VERSION 5.8 ;
BUSBITCHARS "[]" ;
DIVIDERCHAR "/" ;
UNITS
    DATABASE MICRONS 1000 ;
END UNITS

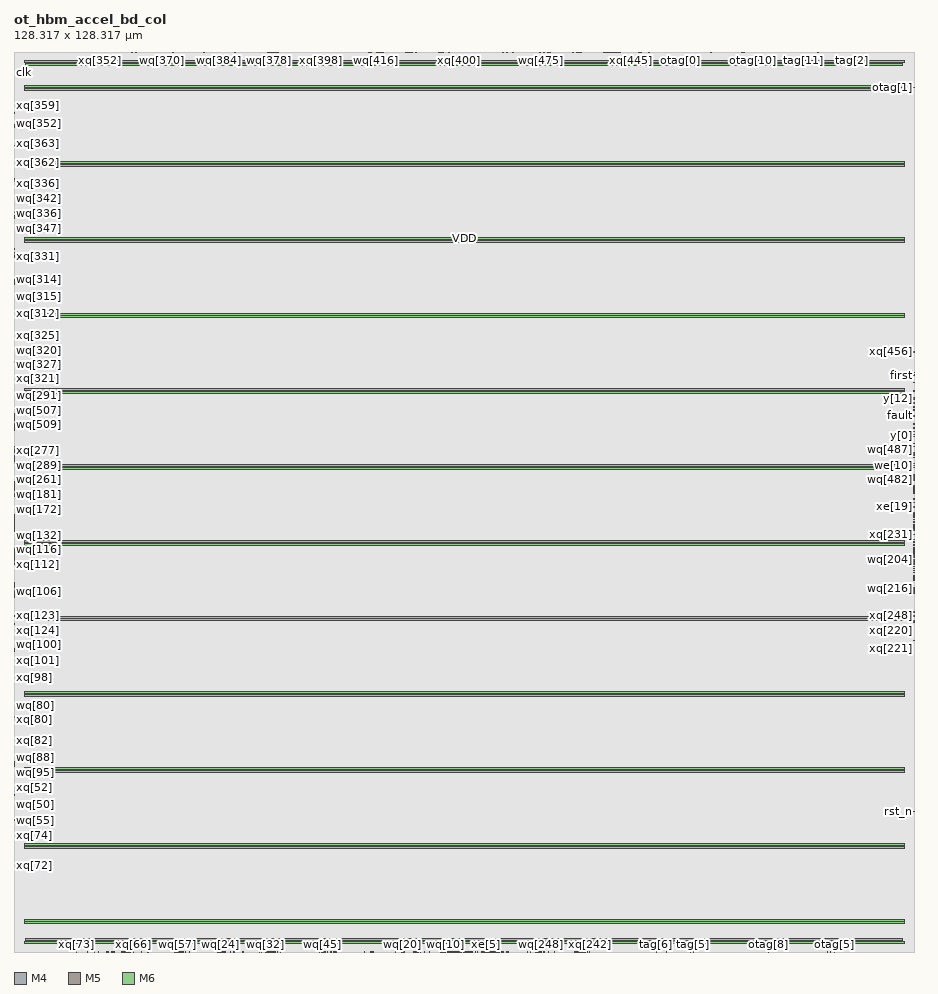
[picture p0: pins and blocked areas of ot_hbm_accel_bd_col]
MACRO ot_hbm_accel_bd_col
  FOREIGN ot_hbm_accel_bd_col 0 0 ;
  CLASS BLOCK ;
  SIZE 128.317 BY 128.317 ;
  PIN clk
    DIRECTION INPUT ;
    USE SIGNAL ;
    PORT
      LAYER M4 ;
        RECT  0 125.376 0.084 125.4 ;
    END
  END clk
  PIN fault
    DIRECTION OUTPUT ;
    USE SIGNAL ;
    PORT
      LAYER M4 ;
        RECT  128.233 76.416 128.317 76.44 ;
    END
  END fault
  PIN first
    DIRECTION INPUT ;
    USE SIGNAL ;
    PORT
      LAYER M4 ;
        RECT  128.233 82.176 128.317 82.2 ;
    END
  END first
  PIN fp4
    DIRECTION INPUT ;
    USE SIGNAL ;
    PORT
      LAYER M4 ;
        RECT  0 66.624 0.084 66.648 ;
    END
  END fp4
  PIN last
    DIRECTION INPUT ;
    USE SIGNAL ;
    PORT
      LAYER M4 ;
        RECT  128.233 82.368 128.317 82.392 ;
    END
  END last
  PIN otag[0]
    DIRECTION OUTPUT ;
    USE SIGNAL ;
    PORT
      LAYER M5 ;
        RECT  95.04 128.233 95.064 128.317 ;
    END
  END otag[0]
  PIN otag[10]
    DIRECTION OUTPUT ;
    USE SIGNAL ;
    PORT
      LAYER M5 ;
        RECT  105.408 128.233 105.432 128.317 ;
    END
  END otag[10]
  PIN otag[11]
    DIRECTION OUTPUT ;
    USE SIGNAL ;
    PORT
      LAYER M5 ;
        RECT  97.536 128.233 97.56 128.317 ;
    END
  END otag[11]
  PIN otag[12]
    DIRECTION OUTPUT ;
    USE SIGNAL ;
    PORT
      LAYER M5 ;
        RECT  97.344 128.233 97.368 128.317 ;
    END
  END otag[12]
  PIN otag[13]
    DIRECTION OUTPUT ;
    USE SIGNAL ;
    PORT
      LAYER M5 ;
        RECT  101.472 128.233 101.496 128.317 ;
    END
  END otag[13]
  PIN otag[14]
    DIRECTION OUTPUT ;
    USE SIGNAL ;
    PORT
      LAYER M5 ;
        RECT  111.744 128.233 111.768 128.317 ;
    END
  END otag[14]
  PIN otag[15]
    DIRECTION OUTPUT ;
    USE SIGNAL ;
    PORT
      LAYER M5 ;
        RECT  99.36 128.233 99.384 128.317 ;
    END
  END otag[15]
  PIN otag[1]
    DIRECTION OUTPUT ;
    USE SIGNAL ;
    PORT
      LAYER M4 ;
        RECT  128.233 123.264 128.317 123.288 ;
    END
  END otag[1]
  PIN otag[2]
    DIRECTION OUTPUT ;
    USE SIGNAL ;
    PORT
      LAYER M5 ;
        RECT  89.376 128.233 89.4 128.317 ;
    END
  END otag[2]
  PIN otag[3]
    DIRECTION OUTPUT ;
    USE SIGNAL ;
    PORT
      LAYER M5 ;
        RECT  90.528 128.233 90.552 128.317 ;
    END
  END otag[3]
  PIN otag[4]
    DIRECTION OUTPUT ;
    USE SIGNAL ;
    PORT
      LAYER M5 ;
        RECT  91.872 128.233 91.896 128.317 ;
    END
  END otag[4]
  PIN otag[5]
    DIRECTION OUTPUT ;
    USE SIGNAL ;
    PORT
      LAYER M5 ;
        RECT  117.024 0 117.048 0.084 ;
    END
  END otag[5]
  PIN otag[6]
    DIRECTION OUTPUT ;
    USE SIGNAL ;
    PORT
      LAYER M5 ;
        RECT  116.352 0 116.376 0.084 ;
    END
  END otag[6]
  PIN otag[7]
    DIRECTION OUTPUT ;
    USE SIGNAL ;
    PORT
      LAYER M5 ;
        RECT  98.976 128.233 99 128.317 ;
    END
  END otag[7]
  PIN otag[8]
    DIRECTION OUTPUT ;
    USE SIGNAL ;
    PORT
      LAYER M5 ;
        RECT  107.616 0 107.64 0.084 ;
    END
  END otag[8]
  PIN otag[9]
    DIRECTION OUTPUT ;
    USE SIGNAL ;
    PORT
      LAYER M5 ;
        RECT  115.968 0 115.992 0.084 ;
    END
  END otag[9]
  PIN ov
    DIRECTION OUTPUT ;
    USE SIGNAL ;
    PORT
      LAYER M4 ;
        RECT  128.233 82.56 128.317 82.584 ;
    END
  END ov
  PIN rst_n
    DIRECTION INPUT ;
    USE SIGNAL ;
    PORT
      LAYER M4 ;
        RECT  128.233 19.968 128.317 19.992 ;
    END
  END rst_n
  PIN tag[0]
    DIRECTION INPUT ;
    USE SIGNAL ;
    PORT
      LAYER M5 ;
        RECT  109.824 128.233 109.848 128.317 ;
    END
  END tag[0]
  PIN tag[10]
    DIRECTION INPUT ;
    USE SIGNAL ;
    PORT
      LAYER M5 ;
        RECT  104.064 128.233 104.088 128.317 ;
    END
  END tag[10]
  PIN tag[11]
    DIRECTION INPUT ;
    USE SIGNAL ;
    PORT
      LAYER M5 ;
        RECT  112.608 128.233 112.632 128.317 ;
    END
  END tag[11]
  PIN tag[12]
    DIRECTION INPUT ;
    USE SIGNAL ;
    PORT
      LAYER M5 ;
        RECT  114.624 128.233 114.648 128.317 ;
    END
  END tag[12]
  PIN tag[13]
    DIRECTION INPUT ;
    USE SIGNAL ;
    PORT
      LAYER M5 ;
        RECT  110.496 128.233 110.52 128.317 ;
    END
  END tag[13]
  PIN tag[14]
    DIRECTION INPUT ;
    USE SIGNAL ;
    PORT
      LAYER M5 ;
        RECT  107.904 128.233 107.928 128.317 ;
    END
  END tag[14]
  PIN tag[15]
    DIRECTION INPUT ;
    USE SIGNAL ;
    PORT
      LAYER M5 ;
        RECT  103.776 128.233 103.8 128.317 ;
    END
  END tag[15]
  PIN tag[1]
    DIRECTION INPUT ;
    USE SIGNAL ;
    PORT
      LAYER M5 ;
        RECT  107.328 128.233 107.352 128.317 ;
    END
  END tag[1]
  PIN tag[2]
    DIRECTION INPUT ;
    USE SIGNAL ;
    PORT
      LAYER M5 ;
        RECT  119.52 128.233 119.544 128.317 ;
    END
  END tag[2]
  PIN tag[3]
    DIRECTION INPUT ;
    USE SIGNAL ;
    PORT
      LAYER M5 ;
        RECT  111.264 128.233 111.288 128.317 ;
    END
  END tag[3]
  PIN tag[4]
    DIRECTION INPUT ;
    USE SIGNAL ;
    PORT
      LAYER M5 ;
        RECT  106.464 128.233 106.488 128.317 ;
    END
  END tag[4]
  PIN tag[5]
    DIRECTION INPUT ;
    USE SIGNAL ;
    PORT
      LAYER M5 ;
        RECT  96.864 0 96.888 0.084 ;
    END
  END tag[5]
  PIN tag[6]
    DIRECTION INPUT ;
    USE SIGNAL ;
    PORT
      LAYER M5 ;
        RECT  91.584 0 91.608 0.084 ;
    END
  END tag[6]
  PIN tag[7]
    DIRECTION INPUT ;
    USE SIGNAL ;
    PORT
      LAYER M5 ;
        RECT  117.024 128.233 117.048 128.317 ;
    END
  END tag[7]
  PIN tag[8]
    DIRECTION INPUT ;
    USE SIGNAL ;
    PORT
      LAYER M5 ;
        RECT  96.48 0 96.504 0.084 ;
    END
  END tag[8]
  PIN tag[9]
    DIRECTION INPUT ;
    USE SIGNAL ;
    PORT
      LAYER M5 ;
        RECT  93.024 0 93.048 0.084 ;
    END
  END tag[9]
  PIN v
    DIRECTION INPUT ;
    USE SIGNAL ;
    PORT
      LAYER M4 ;
        RECT  128.233 82.272 128.317 82.296 ;
    END
  END v
  PIN we[0]
    DIRECTION INPUT ;
    USE SIGNAL ;
    PORT
      LAYER M5 ;
        RECT  70.272 0 70.296 0.084 ;
    END
  END we[0]
  PIN we[10]
    DIRECTION INPUT ;
    USE SIGNAL ;
    PORT
      LAYER M4 ;
        RECT  128.233 69.408 128.317 69.432 ;
    END
  END we[10]
  PIN we[11]
    DIRECTION INPUT ;
    USE SIGNAL ;
    PORT
      LAYER M4 ;
        RECT  128.233 67.968 128.317 67.992 ;
    END
  END we[11]
  PIN we[12]
    DIRECTION INPUT ;
    USE SIGNAL ;
    PORT
      LAYER M4 ;
        RECT  128.233 67.488 128.317 67.512 ;
    END
  END we[12]
  PIN we[13]
    DIRECTION INPUT ;
    USE SIGNAL ;
    PORT
      LAYER M4 ;
        RECT  128.233 66.24 128.317 66.264 ;
    END
  END we[13]
  PIN we[14]
    DIRECTION INPUT ;
    USE SIGNAL ;
    PORT
      LAYER M4 ;
        RECT  128.233 65.376 128.317 65.4 ;
    END
  END we[14]
  PIN we[15]
    DIRECTION INPUT ;
    USE SIGNAL ;
    PORT
      LAYER M4 ;
        RECT  128.233 64.608 128.317 64.632 ;
    END
  END we[15]
  PIN we[16]
    DIRECTION INPUT ;
    USE SIGNAL ;
    PORT
      LAYER M4 ;
        RECT  128.233 64.032 128.317 64.056 ;
    END
  END we[16]
  PIN we[17]
    DIRECTION INPUT ;
    USE SIGNAL ;
    PORT
      LAYER M4 ;
        RECT  128.233 62.208 128.317 62.232 ;
    END
  END we[17]
  PIN we[18]
    DIRECTION INPUT ;
    USE SIGNAL ;
    PORT
      LAYER M4 ;
        RECT  128.233 62.496 128.317 62.52 ;
    END
  END we[18]
  PIN we[19]
    DIRECTION INPUT ;
    USE SIGNAL ;
    PORT
      LAYER M4 ;
        RECT  128.233 63.36 128.317 63.384 ;
    END
  END we[19]
  PIN we[1]
    DIRECTION INPUT ;
    USE SIGNAL ;
    PORT
      LAYER M5 ;
        RECT  69.12 0 69.144 0.084 ;
    END
  END we[1]
  PIN we[2]
    DIRECTION INPUT ;
    USE SIGNAL ;
    PORT
      LAYER M5 ;
        RECT  68.256 0 68.28 0.084 ;
    END
  END we[2]
  PIN we[3]
    DIRECTION INPUT ;
    USE SIGNAL ;
    PORT
      LAYER M5 ;
        RECT  68.928 0 68.952 0.084 ;
    END
  END we[3]
  PIN we[4]
    DIRECTION INPUT ;
    USE SIGNAL ;
    PORT
      LAYER M5 ;
        RECT  67.008 0 67.032 0.084 ;
    END
  END we[4]
  PIN we[5]
    DIRECTION INPUT ;
    USE SIGNAL ;
    PORT
      LAYER M5 ;
        RECT  67.2 0 67.224 0.084 ;
    END
  END we[5]
  PIN we[6]
    DIRECTION INPUT ;
    USE SIGNAL ;
    PORT
      LAYER M5 ;
        RECT  68.544 0 68.568 0.084 ;
    END
  END we[6]
  PIN we[7]
    DIRECTION INPUT ;
    USE SIGNAL ;
    PORT
      LAYER M5 ;
        RECT  66.624 0 66.648 0.084 ;
    END
  END we[7]
  PIN we[8]
    DIRECTION INPUT ;
    USE SIGNAL ;
    PORT
      LAYER M5 ;
        RECT  64.8 0 64.824 0.084 ;
    END
  END we[8]
  PIN we[9]
    DIRECTION INPUT ;
    USE SIGNAL ;
    PORT
      LAYER M5 ;
        RECT  65.088 0 65.112 0.084 ;
    END
  END we[9]
  PIN wq[0]
    DIRECTION INPUT ;
    USE SIGNAL ;
    PORT
      LAYER M5 ;
        RECT  63.84 0 63.864 0.084 ;
    END
  END wq[0]
  PIN wq[100]
    DIRECTION INPUT ;
    USE SIGNAL ;
    PORT
      LAYER M4 ;
        RECT  0 43.776 0.084 43.8 ;
    END
  END wq[100]
  PIN wq[101]
    DIRECTION INPUT ;
    USE SIGNAL ;
    PORT
      LAYER M4 ;
        RECT  0 43.392 0.084 43.416 ;
    END
  END wq[101]
  PIN wq[102]
    DIRECTION INPUT ;
    USE SIGNAL ;
    PORT
      LAYER M4 ;
        RECT  0 43.2 0.084 43.224 ;
    END
  END wq[102]
  PIN wq[103]
    DIRECTION INPUT ;
    USE SIGNAL ;
    PORT
      LAYER M4 ;
        RECT  0 44.64 0.084 44.664 ;
    END
  END wq[103]
  PIN wq[104]
    DIRECTION INPUT ;
    USE SIGNAL ;
    PORT
      LAYER M4 ;
        RECT  0 50.88 0.084 50.904 ;
    END
  END wq[104]
  PIN wq[105]
    DIRECTION INPUT ;
    USE SIGNAL ;
    PORT
      LAYER M4 ;
        RECT  0 51.552 0.084 51.576 ;
    END
  END wq[105]
  PIN wq[106]
    DIRECTION INPUT ;
    USE SIGNAL ;
    PORT
      LAYER M4 ;
        RECT  0 51.456 0.084 51.48 ;
    END
  END wq[106]
  PIN wq[107]
    DIRECTION INPUT ;
    USE SIGNAL ;
    PORT
      LAYER M4 ;
        RECT  0 51.936 0.084 51.96 ;
    END
  END wq[107]
  PIN wq[108]
    DIRECTION INPUT ;
    USE SIGNAL ;
    PORT
      LAYER M4 ;
        RECT  0 50.976 0.084 51 ;
    END
  END wq[108]
  PIN wq[109]
    DIRECTION INPUT ;
    USE SIGNAL ;
    PORT
      LAYER M4 ;
        RECT  0 51.36 0.084 51.384 ;
    END
  END wq[109]
  PIN wq[10]
    DIRECTION INPUT ;
    USE SIGNAL ;
    PORT
      LAYER M5 ;
        RECT  61.536 0 61.56 0.084 ;
    END
  END wq[10]
  PIN wq[110]
    DIRECTION INPUT ;
    USE SIGNAL ;
    PORT
      LAYER M4 ;
        RECT  0 51.648 0.084 51.672 ;
    END
  END wq[110]
  PIN wq[111]
    DIRECTION INPUT ;
    USE SIGNAL ;
    PORT
      LAYER M4 ;
        RECT  0 51.744 0.084 51.768 ;
    END
  END wq[111]
  PIN wq[112]
    DIRECTION INPUT ;
    USE SIGNAL ;
    PORT
      LAYER M4 ;
        RECT  0 52.416 0.084 52.44 ;
    END
  END wq[112]
  PIN wq[113]
    DIRECTION INPUT ;
    USE SIGNAL ;
    PORT
      LAYER M4 ;
        RECT  0 56.544 0.084 56.568 ;
    END
  END wq[113]
  PIN wq[114]
    DIRECTION INPUT ;
    USE SIGNAL ;
    PORT
      LAYER M4 ;
        RECT  0 56.832 0.084 56.856 ;
    END
  END wq[114]
  PIN wq[115]
    DIRECTION INPUT ;
    USE SIGNAL ;
    PORT
      LAYER M4 ;
        RECT  0 54.624 0.084 54.648 ;
    END
  END wq[115]
  PIN wq[116]
    DIRECTION INPUT ;
    USE SIGNAL ;
    PORT
      LAYER M4 ;
        RECT  0 57.312 0.084 57.336 ;
    END
  END wq[116]
  PIN wq[117]
    DIRECTION INPUT ;
    USE SIGNAL ;
    PORT
      LAYER M4 ;
        RECT  0 53.568 0.084 53.592 ;
    END
  END wq[117]
  PIN wq[118]
    DIRECTION INPUT ;
    USE SIGNAL ;
    PORT
      LAYER M4 ;
        RECT  0 56.256 0.084 56.28 ;
    END
  END wq[118]
  PIN wq[119]
    DIRECTION INPUT ;
    USE SIGNAL ;
    PORT
      LAYER M4 ;
        RECT  0 54.912 0.084 54.936 ;
    END
  END wq[119]
  PIN wq[11]
    DIRECTION INPUT ;
    USE SIGNAL ;
    PORT
      LAYER M5 ;
        RECT  64.416 0 64.44 0.084 ;
    END
  END wq[11]
  PIN wq[120]
    DIRECTION INPUT ;
    USE SIGNAL ;
    PORT
      LAYER M4 ;
        RECT  0 52.224 0.084 52.248 ;
    END
  END wq[120]
  PIN wq[121]
    DIRECTION INPUT ;
    USE SIGNAL ;
    PORT
      LAYER M4 ;
        RECT  0 52.32 0.084 52.344 ;
    END
  END wq[121]
  PIN wq[122]
    DIRECTION INPUT ;
    USE SIGNAL ;
    PORT
      LAYER M4 ;
        RECT  0 52.128 0.084 52.152 ;
    END
  END wq[122]
  PIN wq[123]
    DIRECTION INPUT ;
    USE SIGNAL ;
    PORT
      LAYER M4 ;
        RECT  0 50.496 0.084 50.52 ;
    END
  END wq[123]
  PIN wq[124]
    DIRECTION INPUT ;
    USE SIGNAL ;
    PORT
      LAYER M4 ;
        RECT  0 50.688 0.084 50.712 ;
    END
  END wq[124]
  PIN wq[125]
    DIRECTION INPUT ;
    USE SIGNAL ;
    PORT
      LAYER M4 ;
        RECT  0 50.592 0.084 50.616 ;
    END
  END wq[125]
  PIN wq[126]
    DIRECTION INPUT ;
    USE SIGNAL ;
    PORT
      LAYER M4 ;
        RECT  0 52.032 0.084 52.056 ;
    END
  END wq[126]
  PIN wq[127]
    DIRECTION INPUT ;
    USE SIGNAL ;
    PORT
      LAYER M4 ;
        RECT  0 49.824 0.084 49.848 ;
    END
  END wq[127]
  PIN wq[128]
    DIRECTION INPUT ;
    USE SIGNAL ;
    PORT
      LAYER M4 ;
        RECT  0 53.76 0.084 53.784 ;
    END
  END wq[128]
  PIN wq[129]
    DIRECTION INPUT ;
    USE SIGNAL ;
    PORT
      LAYER M4 ;
        RECT  0 58.368 0.084 58.392 ;
    END
  END wq[129]
  PIN wq[12]
    DIRECTION INPUT ;
    USE SIGNAL ;
    PORT
      LAYER M5 ;
        RECT  62.496 0 62.52 0.084 ;
    END
  END wq[12]
  PIN wq[130]
    DIRECTION INPUT ;
    USE SIGNAL ;
    PORT
      LAYER M4 ;
        RECT  0 57.792 0.084 57.816 ;
    END
  END wq[130]
  PIN wq[131]
    DIRECTION INPUT ;
    USE SIGNAL ;
    PORT
      LAYER M4 ;
        RECT  0 53.664 0.084 53.688 ;
    END
  END wq[131]
  PIN wq[132]
    DIRECTION INPUT ;
    USE SIGNAL ;
    PORT
      LAYER M4 ;
        RECT  0 59.328 0.084 59.352 ;
    END
  END wq[132]
  PIN wq[133]
    DIRECTION INPUT ;
    USE SIGNAL ;
    PORT
      LAYER M4 ;
        RECT  0 57.696 0.084 57.72 ;
    END
  END wq[133]
  PIN wq[134]
    DIRECTION INPUT ;
    USE SIGNAL ;
    PORT
      LAYER M4 ;
        RECT  0 58.464 0.084 58.488 ;
    END
  END wq[134]
  PIN wq[135]
    DIRECTION INPUT ;
    USE SIGNAL ;
    PORT
      LAYER M4 ;
        RECT  0 59.136 0.084 59.16 ;
    END
  END wq[135]
  PIN wq[136]
    DIRECTION INPUT ;
    USE SIGNAL ;
    PORT
      LAYER M4 ;
        RECT  0 59.04 0.084 59.064 ;
    END
  END wq[136]
  PIN wq[137]
    DIRECTION INPUT ;
    USE SIGNAL ;
    PORT
      LAYER M4 ;
        RECT  0 58.848 0.084 58.872 ;
    END
  END wq[137]
  PIN wq[138]
    DIRECTION INPUT ;
    USE SIGNAL ;
    PORT
      LAYER M4 ;
        RECT  0 58.752 0.084 58.776 ;
    END
  END wq[138]
  PIN wq[139]
    DIRECTION INPUT ;
    USE SIGNAL ;
    PORT
      LAYER M4 ;
        RECT  0 53.28 0.084 53.304 ;
    END
  END wq[139]
  PIN wq[13]
    DIRECTION INPUT ;
    USE SIGNAL ;
    PORT
      LAYER M5 ;
        RECT  62.592 0 62.616 0.084 ;
    END
  END wq[13]
  PIN wq[140]
    DIRECTION INPUT ;
    USE SIGNAL ;
    PORT
      LAYER M4 ;
        RECT  0 57.888 0.084 57.912 ;
    END
  END wq[140]
  PIN wq[141]
    DIRECTION INPUT ;
    USE SIGNAL ;
    PORT
      LAYER M4 ;
        RECT  0 57.408 0.084 57.432 ;
    END
  END wq[141]
  PIN wq[142]
    DIRECTION INPUT ;
    USE SIGNAL ;
    PORT
      LAYER M4 ;
        RECT  0 56.064 0.084 56.088 ;
    END
  END wq[142]
  PIN wq[143]
    DIRECTION INPUT ;
    USE SIGNAL ;
    PORT
      LAYER M4 ;
        RECT  0 59.808 0.084 59.832 ;
    END
  END wq[143]
  PIN wq[144]
    DIRECTION INPUT ;
    USE SIGNAL ;
    PORT
      LAYER M4 ;
        RECT  0 60.768 0.084 60.792 ;
    END
  END wq[144]
  PIN wq[145]
    DIRECTION INPUT ;
    USE SIGNAL ;
    PORT
      LAYER M4 ;
        RECT  0 60.48 0.084 60.504 ;
    END
  END wq[145]
  PIN wq[146]
    DIRECTION INPUT ;
    USE SIGNAL ;
    PORT
      LAYER M4 ;
        RECT  0 60.384 0.084 60.408 ;
    END
  END wq[146]
  PIN wq[147]
    DIRECTION INPUT ;
    USE SIGNAL ;
    PORT
      LAYER M4 ;
        RECT  0 60.576 0.084 60.6 ;
    END
  END wq[147]
  PIN wq[148]
    DIRECTION INPUT ;
    USE SIGNAL ;
    PORT
      LAYER M4 ;
        RECT  0 60.192 0.084 60.216 ;
    END
  END wq[148]
  PIN wq[149]
    DIRECTION INPUT ;
    USE SIGNAL ;
    PORT
      LAYER M4 ;
        RECT  0 60.288 0.084 60.312 ;
    END
  END wq[149]
  PIN wq[14]
    DIRECTION INPUT ;
    USE SIGNAL ;
    PORT
      LAYER M5 ;
        RECT  61.44 0 61.464 0.084 ;
    END
  END wq[14]
  PIN wq[150]
    DIRECTION INPUT ;
    USE SIGNAL ;
    PORT
      LAYER M4 ;
        RECT  0 60 0.084 60.024 ;
    END
  END wq[150]
  PIN wq[151]
    DIRECTION INPUT ;
    USE SIGNAL ;
    PORT
      LAYER M4 ;
        RECT  0 61.536 0.084 61.56 ;
    END
  END wq[151]
  PIN wq[152]
    DIRECTION INPUT ;
    USE SIGNAL ;
    PORT
      LAYER M4 ;
        RECT  0 57.6 0.084 57.624 ;
    END
  END wq[152]
  PIN wq[153]
    DIRECTION INPUT ;
    USE SIGNAL ;
    PORT
      LAYER M4 ;
        RECT  0 52.608 0.084 52.632 ;
    END
  END wq[153]
  PIN wq[154]
    DIRECTION INPUT ;
    USE SIGNAL ;
    PORT
      LAYER M4 ;
        RECT  0 59.232 0.084 59.256 ;
    END
  END wq[154]
  PIN wq[155]
    DIRECTION INPUT ;
    USE SIGNAL ;
    PORT
      LAYER M4 ;
        RECT  0 57.984 0.084 58.008 ;
    END
  END wq[155]
  PIN wq[156]
    DIRECTION INPUT ;
    USE SIGNAL ;
    PORT
      LAYER M4 ;
        RECT  0 58.176 0.084 58.2 ;
    END
  END wq[156]
  PIN wq[157]
    DIRECTION INPUT ;
    USE SIGNAL ;
    PORT
      LAYER M4 ;
        RECT  0 58.08 0.084 58.104 ;
    END
  END wq[157]
  PIN wq[158]
    DIRECTION INPUT ;
    USE SIGNAL ;
    PORT
      LAYER M4 ;
        RECT  0 53.856 0.084 53.88 ;
    END
  END wq[158]
  PIN wq[159]
    DIRECTION INPUT ;
    USE SIGNAL ;
    PORT
      LAYER M4 ;
        RECT  0 56.736 0.084 56.76 ;
    END
  END wq[159]
  PIN wq[15]
    DIRECTION INPUT ;
    USE SIGNAL ;
    PORT
      LAYER M5 ;
        RECT  64.992 0 65.016 0.084 ;
    END
  END wq[15]
  PIN wq[160]
    DIRECTION INPUT ;
    USE SIGNAL ;
    PORT
      LAYER M4 ;
        RECT  0 52.8 0.084 52.824 ;
    END
  END wq[160]
  PIN wq[161]
    DIRECTION INPUT ;
    USE SIGNAL ;
    PORT
      LAYER M4 ;
        RECT  0 61.248 0.084 61.272 ;
    END
  END wq[161]
  PIN wq[162]
    DIRECTION INPUT ;
    USE SIGNAL ;
    PORT
      LAYER M4 ;
        RECT  0 59.52 0.084 59.544 ;
    END
  END wq[162]
  PIN wq[163]
    DIRECTION INPUT ;
    USE SIGNAL ;
    PORT
      LAYER M4 ;
        RECT  0 62.496 0.084 62.52 ;
    END
  END wq[163]
  PIN wq[164]
    DIRECTION INPUT ;
    USE SIGNAL ;
    PORT
      LAYER M4 ;
        RECT  0 61.728 0.084 61.752 ;
    END
  END wq[164]
  PIN wq[165]
    DIRECTION INPUT ;
    USE SIGNAL ;
    PORT
      LAYER M4 ;
        RECT  0 52.512 0.084 52.536 ;
    END
  END wq[165]
  PIN wq[166]
    DIRECTION INPUT ;
    USE SIGNAL ;
    PORT
      LAYER M4 ;
        RECT  0 62.4 0.084 62.424 ;
    END
  END wq[166]
  PIN wq[167]
    DIRECTION INPUT ;
    USE SIGNAL ;
    PORT
      LAYER M4 ;
        RECT  0 63.36 0.084 63.384 ;
    END
  END wq[167]
  PIN wq[168]
    DIRECTION INPUT ;
    USE SIGNAL ;
    PORT
      LAYER M4 ;
        RECT  0 61.632 0.084 61.656 ;
    END
  END wq[168]
  PIN wq[169]
    DIRECTION INPUT ;
    USE SIGNAL ;
    PORT
      LAYER M4 ;
        RECT  0 64.608 0.084 64.632 ;
    END
  END wq[169]
  PIN wq[16]
    DIRECTION INPUT ;
    USE SIGNAL ;
    PORT
      LAYER M5 ;
        RECT  57.216 0 57.24 0.084 ;
    END
  END wq[16]
  PIN wq[170]
    DIRECTION INPUT ;
    USE SIGNAL ;
    PORT
      LAYER M4 ;
        RECT  0 64.224 0.084 64.248 ;
    END
  END wq[170]
  PIN wq[171]
    DIRECTION INPUT ;
    USE SIGNAL ;
    PORT
      LAYER M4 ;
        RECT  0 62.304 0.084 62.328 ;
    END
  END wq[171]
  PIN wq[172]
    DIRECTION INPUT ;
    USE SIGNAL ;
    PORT
      LAYER M4 ;
        RECT  0 63.072 0.084 63.096 ;
    END
  END wq[172]
  PIN wq[173]
    DIRECTION INPUT ;
    USE SIGNAL ;
    PORT
      LAYER M4 ;
        RECT  0 52.992 0.084 53.016 ;
    END
  END wq[173]
  PIN wq[174]
    DIRECTION INPUT ;
    USE SIGNAL ;
    PORT
      LAYER M4 ;
        RECT  0 63.936 0.084 63.96 ;
    END
  END wq[174]
  PIN wq[175]
    DIRECTION INPUT ;
    USE SIGNAL ;
    PORT
      LAYER M4 ;
        RECT  0 53.088 0.084 53.112 ;
    END
  END wq[175]
  PIN wq[176]
    DIRECTION INPUT ;
    USE SIGNAL ;
    PORT
      LAYER M4 ;
        RECT  0 64.8 0.084 64.824 ;
    END
  END wq[176]
  PIN wq[177]
    DIRECTION INPUT ;
    USE SIGNAL ;
    PORT
      LAYER M4 ;
        RECT  0 64.704 0.084 64.728 ;
    END
  END wq[177]
  PIN wq[178]
    DIRECTION INPUT ;
    USE SIGNAL ;
    PORT
      LAYER M4 ;
        RECT  0 59.424 0.084 59.448 ;
    END
  END wq[178]
  PIN wq[179]
    DIRECTION INPUT ;
    USE SIGNAL ;
    PORT
      LAYER M4 ;
        RECT  0 52.704 0.084 52.728 ;
    END
  END wq[179]
  PIN wq[17]
    DIRECTION INPUT ;
    USE SIGNAL ;
    PORT
      LAYER M5 ;
        RECT  57.312 0 57.336 0.084 ;
    END
  END wq[17]
  PIN wq[180]
    DIRECTION INPUT ;
    USE SIGNAL ;
    PORT
      LAYER M4 ;
        RECT  0 64.32 0.084 64.344 ;
    END
  END wq[180]
  PIN wq[181]
    DIRECTION INPUT ;
    USE SIGNAL ;
    PORT
      LAYER M4 ;
        RECT  0 64.128 0.084 64.152 ;
    END
  END wq[181]
  PIN wq[182]
    DIRECTION INPUT ;
    USE SIGNAL ;
    PORT
      LAYER M4 ;
        RECT  0 62.592 0.084 62.616 ;
    END
  END wq[182]
  PIN wq[183]
    DIRECTION INPUT ;
    USE SIGNAL ;
    PORT
      LAYER M4 ;
        RECT  0 63.168 0.084 63.192 ;
    END
  END wq[183]
  PIN wq[184]
    DIRECTION INPUT ;
    USE SIGNAL ;
    PORT
      LAYER M4 ;
        RECT  0 63.552 0.084 63.576 ;
    END
  END wq[184]
  PIN wq[185]
    DIRECTION INPUT ;
    USE SIGNAL ;
    PORT
      LAYER M4 ;
        RECT  0 60.96 0.084 60.984 ;
    END
  END wq[185]
  PIN wq[186]
    DIRECTION INPUT ;
    USE SIGNAL ;
    PORT
      LAYER M4 ;
        RECT  0 61.92 0.084 61.944 ;
    END
  END wq[186]
  PIN wq[187]
    DIRECTION INPUT ;
    USE SIGNAL ;
    PORT
      LAYER M4 ;
        RECT  0 62.784 0.084 62.808 ;
    END
  END wq[187]
  PIN wq[188]
    DIRECTION INPUT ;
    USE SIGNAL ;
    PORT
      LAYER M4 ;
        RECT  0 62.976 0.084 63 ;
    END
  END wq[188]
  PIN wq[189]
    DIRECTION INPUT ;
    USE SIGNAL ;
    PORT
      LAYER M4 ;
        RECT  0 63.456 0.084 63.48 ;
    END
  END wq[189]
  PIN wq[18]
    DIRECTION INPUT ;
    USE SIGNAL ;
    PORT
      LAYER M5 ;
        RECT  57.408 0 57.432 0.084 ;
    END
  END wq[18]
  PIN wq[190]
    DIRECTION INPUT ;
    USE SIGNAL ;
    PORT
      LAYER M4 ;
        RECT  0 63.648 0.084 63.672 ;
    END
  END wq[190]
  PIN wq[191]
    DIRECTION INPUT ;
    USE SIGNAL ;
    PORT
      LAYER M4 ;
        RECT  0 62.112 0.084 62.136 ;
    END
  END wq[191]
  PIN wq[192]
    DIRECTION INPUT ;
    USE SIGNAL ;
    PORT
      LAYER M5 ;
        RECT  62.4 128.233 62.424 128.317 ;
    END
  END wq[192]
  PIN wq[193]
    DIRECTION INPUT ;
    USE SIGNAL ;
    PORT
      LAYER M5 ;
        RECT  62.688 128.233 62.712 128.317 ;
    END
  END wq[193]
  PIN wq[194]
    DIRECTION INPUT ;
    USE SIGNAL ;
    PORT
      LAYER M5 ;
        RECT  62.496 128.233 62.52 128.317 ;
    END
  END wq[194]
  PIN wq[195]
    DIRECTION INPUT ;
    USE SIGNAL ;
    PORT
      LAYER M4 ;
        RECT  0 63.264 0.084 63.288 ;
    END
  END wq[195]
  PIN wq[196]
    DIRECTION INPUT ;
    USE SIGNAL ;
    PORT
      LAYER M4 ;
        RECT  0 63.84 0.084 63.864 ;
    END
  END wq[196]
  PIN wq[197]
    DIRECTION INPUT ;
    USE SIGNAL ;
    PORT
      LAYER M4 ;
        RECT  0 63.744 0.084 63.768 ;
    END
  END wq[197]
  PIN wq[198]
    DIRECTION INPUT ;
    USE SIGNAL ;
    PORT
      LAYER M4 ;
        RECT  0 62.688 0.084 62.712 ;
    END
  END wq[198]
  PIN wq[199]
    DIRECTION INPUT ;
    USE SIGNAL ;
    PORT
      LAYER M5 ;
        RECT  64.32 0 64.344 0.084 ;
    END
  END wq[199]
  PIN wq[19]
    DIRECTION INPUT ;
    USE SIGNAL ;
    PORT
      LAYER M5 ;
        RECT  51.168 0 51.192 0.084 ;
    END
  END wq[19]
  PIN wq[1]
    DIRECTION INPUT ;
    USE SIGNAL ;
    PORT
      LAYER M5 ;
        RECT  63.648 0 63.672 0.084 ;
    END
  END wq[1]
  PIN wq[200]
    DIRECTION INPUT ;
    USE SIGNAL ;
    PORT
      LAYER M4 ;
        RECT  128.233 56.256 128.317 56.28 ;
    END
  END wq[200]
  PIN wq[201]
    DIRECTION INPUT ;
    USE SIGNAL ;
    PORT
      LAYER M4 ;
        RECT  128.233 56.448 128.317 56.472 ;
    END
  END wq[201]
  PIN wq[202]
    DIRECTION INPUT ;
    USE SIGNAL ;
    PORT
      LAYER M4 ;
        RECT  128.233 56.832 128.317 56.856 ;
    END
  END wq[202]
  PIN wq[203]
    DIRECTION INPUT ;
    USE SIGNAL ;
    PORT
      LAYER M4 ;
        RECT  128.233 57.504 128.317 57.528 ;
    END
  END wq[203]
  PIN wq[204]
    DIRECTION INPUT ;
    USE SIGNAL ;
    PORT
      LAYER M4 ;
        RECT  128.233 55.968 128.317 55.992 ;
    END
  END wq[204]
  PIN wq[205]
    DIRECTION INPUT ;
    USE SIGNAL ;
    PORT
      LAYER M4 ;
        RECT  128.233 55.872 128.317 55.896 ;
    END
  END wq[205]
  PIN wq[206]
    DIRECTION INPUT ;
    USE SIGNAL ;
    PORT
      LAYER M4 ;
        RECT  128.233 56.544 128.317 56.568 ;
    END
  END wq[206]
  PIN wq[207]
    DIRECTION INPUT ;
    USE SIGNAL ;
    PORT
      LAYER M4 ;
        RECT  128.233 57.312 128.317 57.336 ;
    END
  END wq[207]
  PIN wq[208]
    DIRECTION INPUT ;
    USE SIGNAL ;
    PORT
      LAYER M5 ;
        RECT  68.832 0 68.856 0.084 ;
    END
  END wq[208]
  PIN wq[209]
    DIRECTION INPUT ;
    USE SIGNAL ;
    PORT
      LAYER M5 ;
        RECT  68.352 0 68.376 0.084 ;
    END
  END wq[209]
  PIN wq[20]
    DIRECTION INPUT ;
    USE SIGNAL ;
    PORT
      LAYER M5 ;
        RECT  55.392 0 55.416 0.084 ;
    END
  END wq[20]
  PIN wq[210]
    DIRECTION INPUT ;
    USE SIGNAL ;
    PORT
      LAYER M5 ;
        RECT  68.64 0 68.664 0.084 ;
    END
  END wq[210]
  PIN wq[211]
    DIRECTION INPUT ;
    USE SIGNAL ;
    PORT
      LAYER M5 ;
        RECT  69.504 0 69.528 0.084 ;
    END
  END wq[211]
  PIN wq[212]
    DIRECTION INPUT ;
    USE SIGNAL ;
    PORT
      LAYER M5 ;
        RECT  67.392 0 67.416 0.084 ;
    END
  END wq[212]
  PIN wq[213]
    DIRECTION INPUT ;
    USE SIGNAL ;
    PORT
      LAYER M5 ;
        RECT  67.104 0 67.128 0.084 ;
    END
  END wq[213]
  PIN wq[214]
    DIRECTION INPUT ;
    USE SIGNAL ;
    PORT
      LAYER M5 ;
        RECT  67.968 0 67.992 0.084 ;
    END
  END wq[214]
  PIN wq[215]
    DIRECTION INPUT ;
    USE SIGNAL ;
    PORT
      LAYER M5 ;
        RECT  70.464 0 70.488 0.084 ;
    END
  END wq[215]
  PIN wq[216]
    DIRECTION INPUT ;
    USE SIGNAL ;
    PORT
      LAYER M4 ;
        RECT  128.233 51.84 128.317 51.864 ;
    END
  END wq[216]
  PIN wq[217]
    DIRECTION INPUT ;
    USE SIGNAL ;
    PORT
      LAYER M4 ;
        RECT  128.233 51.936 128.317 51.96 ;
    END
  END wq[217]
  PIN wq[218]
    DIRECTION INPUT ;
    USE SIGNAL ;
    PORT
      LAYER M4 ;
        RECT  128.233 51.456 128.317 51.48 ;
    END
  END wq[218]
  PIN wq[219]
    DIRECTION INPUT ;
    USE SIGNAL ;
    PORT
      LAYER M4 ;
        RECT  128.233 51.552 128.317 51.576 ;
    END
  END wq[219]
  PIN wq[21]
    DIRECTION INPUT ;
    USE SIGNAL ;
    PORT
      LAYER M5 ;
        RECT  57.504 0 57.528 0.084 ;
    END
  END wq[21]
  PIN wq[220]
    DIRECTION INPUT ;
    USE SIGNAL ;
    PORT
      LAYER M4 ;
        RECT  128.233 51.264 128.317 51.288 ;
    END
  END wq[220]
  PIN wq[221]
    DIRECTION INPUT ;
    USE SIGNAL ;
    PORT
      LAYER M4 ;
        RECT  128.233 51.072 128.317 51.096 ;
    END
  END wq[221]
  PIN wq[222]
    DIRECTION INPUT ;
    USE SIGNAL ;
    PORT
      LAYER M4 ;
        RECT  128.233 51.168 128.317 51.192 ;
    END
  END wq[222]
  PIN wq[223]
    DIRECTION INPUT ;
    USE SIGNAL ;
    PORT
      LAYER M4 ;
        RECT  128.233 51.744 128.317 51.768 ;
    END
  END wq[223]
  PIN wq[224]
    DIRECTION INPUT ;
    USE SIGNAL ;
    PORT
      LAYER M4 ;
        RECT  128.233 58.368 128.317 58.392 ;
    END
  END wq[224]
  PIN wq[225]
    DIRECTION INPUT ;
    USE SIGNAL ;
    PORT
      LAYER M4 ;
        RECT  128.233 57.888 128.317 57.912 ;
    END
  END wq[225]
  PIN wq[226]
    DIRECTION INPUT ;
    USE SIGNAL ;
    PORT
      LAYER M4 ;
        RECT  128.233 57.408 128.317 57.432 ;
    END
  END wq[226]
  PIN wq[227]
    DIRECTION INPUT ;
    USE SIGNAL ;
    PORT
      LAYER M4 ;
        RECT  128.233 57.984 128.317 58.008 ;
    END
  END wq[227]
  PIN wq[228]
    DIRECTION INPUT ;
    USE SIGNAL ;
    PORT
      LAYER M4 ;
        RECT  128.233 57.216 128.317 57.24 ;
    END
  END wq[228]
  PIN wq[229]
    DIRECTION INPUT ;
    USE SIGNAL ;
    PORT
      LAYER M4 ;
        RECT  128.233 56.928 128.317 56.952 ;
    END
  END wq[229]
  PIN wq[22]
    DIRECTION INPUT ;
    USE SIGNAL ;
    PORT
      LAYER M5 ;
        RECT  57.696 0 57.72 0.084 ;
    END
  END wq[22]
  PIN wq[230]
    DIRECTION INPUT ;
    USE SIGNAL ;
    PORT
      LAYER M4 ;
        RECT  128.233 56.736 128.317 56.76 ;
    END
  END wq[230]
  PIN wq[231]
    DIRECTION INPUT ;
    USE SIGNAL ;
    PORT
      LAYER M4 ;
        RECT  128.233 58.752 128.317 58.776 ;
    END
  END wq[231]
  PIN wq[232]
    DIRECTION INPUT ;
    USE SIGNAL ;
    PORT
      LAYER M4 ;
        RECT  128.233 58.08 128.317 58.104 ;
    END
  END wq[232]
  PIN wq[233]
    DIRECTION INPUT ;
    USE SIGNAL ;
    PORT
      LAYER M4 ;
        RECT  128.233 58.464 128.317 58.488 ;
    END
  END wq[233]
  PIN wq[234]
    DIRECTION INPUT ;
    USE SIGNAL ;
    PORT
      LAYER M4 ;
        RECT  128.233 57.6 128.317 57.624 ;
    END
  END wq[234]
  PIN wq[235]
    DIRECTION INPUT ;
    USE SIGNAL ;
    PORT
      LAYER M4 ;
        RECT  128.233 58.56 128.317 58.584 ;
    END
  END wq[235]
  PIN wq[236]
    DIRECTION INPUT ;
    USE SIGNAL ;
    PORT
      LAYER M4 ;
        RECT  128.233 57.12 128.317 57.144 ;
    END
  END wq[236]
  PIN wq[237]
    DIRECTION INPUT ;
    USE SIGNAL ;
    PORT
      LAYER M4 ;
        RECT  128.233 57.024 128.317 57.048 ;
    END
  END wq[237]
  PIN wq[238]
    DIRECTION INPUT ;
    USE SIGNAL ;
    PORT
      LAYER M4 ;
        RECT  128.233 56.64 128.317 56.664 ;
    END
  END wq[238]
  PIN wq[239]
    DIRECTION INPUT ;
    USE SIGNAL ;
    PORT
      LAYER M4 ;
        RECT  128.233 60.48 128.317 60.504 ;
    END
  END wq[239]
  PIN wq[23]
    DIRECTION INPUT ;
    USE SIGNAL ;
    PORT
      LAYER M5 ;
        RECT  50.88 0 50.904 0.084 ;
    END
  END wq[23]
  PIN wq[240]
    DIRECTION INPUT ;
    USE SIGNAL ;
    PORT
      LAYER M5 ;
        RECT  79.968 0 79.992 0.084 ;
    END
  END wq[240]
  PIN wq[241]
    DIRECTION INPUT ;
    USE SIGNAL ;
    PORT
      LAYER M5 ;
        RECT  79.872 0 79.896 0.084 ;
    END
  END wq[241]
  PIN wq[242]
    DIRECTION INPUT ;
    USE SIGNAL ;
    PORT
      LAYER M5 ;
        RECT  80.064 0 80.088 0.084 ;
    END
  END wq[242]
  PIN wq[243]
    DIRECTION INPUT ;
    USE SIGNAL ;
    PORT
      LAYER M5 ;
        RECT  80.736 0 80.76 0.084 ;
    END
  END wq[243]
  PIN wq[244]
    DIRECTION INPUT ;
    USE SIGNAL ;
    PORT
      LAYER M5 ;
        RECT  80.544 0 80.568 0.084 ;
    END
  END wq[244]
  PIN wq[245]
    DIRECTION INPUT ;
    USE SIGNAL ;
    PORT
      LAYER M5 ;
        RECT  80.256 0 80.28 0.084 ;
    END
  END wq[245]
  PIN wq[246]
    DIRECTION INPUT ;
    USE SIGNAL ;
    PORT
      LAYER M5 ;
        RECT  80.352 0 80.376 0.084 ;
    END
  END wq[246]
  PIN wq[247]
    DIRECTION INPUT ;
    USE SIGNAL ;
    PORT
      LAYER M5 ;
        RECT  80.928 0 80.952 0.084 ;
    END
  END wq[247]
  PIN wq[248]
    DIRECTION INPUT ;
    USE SIGNAL ;
    PORT
      LAYER M5 ;
        RECT  75.168 0 75.192 0.084 ;
    END
  END wq[248]
  PIN wq[249]
    DIRECTION INPUT ;
    USE SIGNAL ;
    PORT
      LAYER M5 ;
        RECT  74.976 0 75 0.084 ;
    END
  END wq[249]
  PIN wq[24]
    DIRECTION INPUT ;
    USE SIGNAL ;
    PORT
      LAYER M5 ;
        RECT  29.376 0 29.4 0.084 ;
    END
  END wq[24]
  PIN wq[250]
    DIRECTION INPUT ;
    USE SIGNAL ;
    PORT
      LAYER M5 ;
        RECT  75.072 0 75.096 0.084 ;
    END
  END wq[250]
  PIN wq[251]
    DIRECTION INPUT ;
    USE SIGNAL ;
    PORT
      LAYER M5 ;
        RECT  75.552 0 75.576 0.084 ;
    END
  END wq[251]
  PIN wq[252]
    DIRECTION INPUT ;
    USE SIGNAL ;
    PORT
      LAYER M5 ;
        RECT  74.4 0 74.424 0.084 ;
    END
  END wq[252]
  PIN wq[253]
    DIRECTION INPUT ;
    USE SIGNAL ;
    PORT
      LAYER M5 ;
        RECT  74.784 0 74.808 0.084 ;
    END
  END wq[253]
  PIN wq[254]
    DIRECTION INPUT ;
    USE SIGNAL ;
    PORT
      LAYER M5 ;
        RECT  74.688 0 74.712 0.084 ;
    END
  END wq[254]
  PIN wq[255]
    DIRECTION INPUT ;
    USE SIGNAL ;
    PORT
      LAYER M5 ;
        RECT  76.224 0 76.248 0.084 ;
    END
  END wq[255]
  PIN wq[256]
    DIRECTION INPUT ;
    USE SIGNAL ;
    PORT
      LAYER M4 ;
        RECT  0 66.336 0.084 66.36 ;
    END
  END wq[256]
  PIN wq[257]
    DIRECTION INPUT ;
    USE SIGNAL ;
    PORT
      LAYER M4 ;
        RECT  0 68.928 0.084 68.952 ;
    END
  END wq[257]
  PIN wq[258]
    DIRECTION INPUT ;
    USE SIGNAL ;
    PORT
      LAYER M4 ;
        RECT  0 66.528 0.084 66.552 ;
    END
  END wq[258]
  PIN wq[259]
    DIRECTION INPUT ;
    USE SIGNAL ;
    PORT
      LAYER M4 ;
        RECT  0 64.896 0.084 64.92 ;
    END
  END wq[259]
  PIN wq[25]
    DIRECTION INPUT ;
    USE SIGNAL ;
    PORT
      LAYER M5 ;
        RECT  29.28 0 29.304 0.084 ;
    END
  END wq[25]
  PIN wq[260]
    DIRECTION INPUT ;
    USE SIGNAL ;
    PORT
      LAYER M4 ;
        RECT  0 66.816 0.084 66.84 ;
    END
  END wq[260]
  PIN wq[261]
    DIRECTION INPUT ;
    USE SIGNAL ;
    PORT
      LAYER M4 ;
        RECT  0 67.296 0.084 67.32 ;
    END
  END wq[261]
  PIN wq[262]
    DIRECTION INPUT ;
    USE SIGNAL ;
    PORT
      LAYER M4 ;
        RECT  0 67.008 0.084 67.032 ;
    END
  END wq[262]
  PIN wq[263]
    DIRECTION INPUT ;
    USE SIGNAL ;
    PORT
      LAYER M4 ;
        RECT  0 65.76 0.084 65.784 ;
    END
  END wq[263]
  PIN wq[264]
    DIRECTION INPUT ;
    USE SIGNAL ;
    PORT
      LAYER M4 ;
        RECT  0 68.64 0.084 68.664 ;
    END
  END wq[264]
  PIN wq[265]
    DIRECTION INPUT ;
    USE SIGNAL ;
    PORT
      LAYER M4 ;
        RECT  0 67.104 0.084 67.128 ;
    END
  END wq[265]
  PIN wq[266]
    DIRECTION INPUT ;
    USE SIGNAL ;
    PORT
      LAYER M4 ;
        RECT  0 67.2 0.084 67.224 ;
    END
  END wq[266]
  PIN wq[267]
    DIRECTION INPUT ;
    USE SIGNAL ;
    PORT
      LAYER M4 ;
        RECT  0 65.952 0.084 65.976 ;
    END
  END wq[267]
  PIN wq[268]
    DIRECTION INPUT ;
    USE SIGNAL ;
    PORT
      LAYER M4 ;
        RECT  0 68.064 0.084 68.088 ;
    END
  END wq[268]
  PIN wq[269]
    DIRECTION INPUT ;
    USE SIGNAL ;
    PORT
      LAYER M4 ;
        RECT  0 67.68 0.084 67.704 ;
    END
  END wq[269]
  PIN wq[26]
    DIRECTION INPUT ;
    USE SIGNAL ;
    PORT
      LAYER M5 ;
        RECT  29.568 0 29.592 0.084 ;
    END
  END wq[26]
  PIN wq[270]
    DIRECTION INPUT ;
    USE SIGNAL ;
    PORT
      LAYER M4 ;
        RECT  0 67.872 0.084 67.896 ;
    END
  END wq[270]
  PIN wq[271]
    DIRECTION INPUT ;
    USE SIGNAL ;
    PORT
      LAYER M4 ;
        RECT  0 65.856 0.084 65.88 ;
    END
  END wq[271]
  PIN wq[272]
    DIRECTION INPUT ;
    USE SIGNAL ;
    PORT
      LAYER M4 ;
        RECT  0 67.968 0.084 67.992 ;
    END
  END wq[272]
  PIN wq[273]
    DIRECTION INPUT ;
    USE SIGNAL ;
    PORT
      LAYER M4 ;
        RECT  0 67.392 0.084 67.416 ;
    END
  END wq[273]
  PIN wq[274]
    DIRECTION INPUT ;
    USE SIGNAL ;
    PORT
      LAYER M4 ;
        RECT  0 68.16 0.084 68.184 ;
    END
  END wq[274]
  PIN wq[275]
    DIRECTION INPUT ;
    USE SIGNAL ;
    PORT
      LAYER M4 ;
        RECT  0 66.912 0.084 66.936 ;
    END
  END wq[275]
  PIN wq[276]
    DIRECTION INPUT ;
    USE SIGNAL ;
    PORT
      LAYER M4 ;
        RECT  0 67.776 0.084 67.8 ;
    END
  END wq[276]
  PIN wq[277]
    DIRECTION INPUT ;
    USE SIGNAL ;
    PORT
      LAYER M4 ;
        RECT  0 67.488 0.084 67.512 ;
    END
  END wq[277]
  PIN wq[278]
    DIRECTION INPUT ;
    USE SIGNAL ;
    PORT
      LAYER M4 ;
        RECT  0 67.584 0.084 67.608 ;
    END
  END wq[278]
  PIN wq[279]
    DIRECTION INPUT ;
    USE SIGNAL ;
    PORT
      LAYER M4 ;
        RECT  0 64.416 0.084 64.44 ;
    END
  END wq[279]
  PIN wq[27]
    DIRECTION INPUT ;
    USE SIGNAL ;
    PORT
      LAYER M5 ;
        RECT  30.144 0 30.168 0.084 ;
    END
  END wq[27]
  PIN wq[280]
    DIRECTION INPUT ;
    USE SIGNAL ;
    PORT
      LAYER M4 ;
        RECT  0 60.864 0.084 60.888 ;
    END
  END wq[280]
  PIN wq[281]
    DIRECTION INPUT ;
    USE SIGNAL ;
    PORT
      LAYER M4 ;
        RECT  0 65.568 0.084 65.592 ;
    END
  END wq[281]
  PIN wq[282]
    DIRECTION INPUT ;
    USE SIGNAL ;
    PORT
      LAYER M4 ;
        RECT  0 65.28 0.084 65.304 ;
    END
  END wq[282]
  PIN wq[283]
    DIRECTION INPUT ;
    USE SIGNAL ;
    PORT
      LAYER M4 ;
        RECT  0 66.24 0.084 66.264 ;
    END
  END wq[283]
  PIN wq[284]
    DIRECTION INPUT ;
    USE SIGNAL ;
    PORT
      LAYER M4 ;
        RECT  0 68.544 0.084 68.568 ;
    END
  END wq[284]
  PIN wq[285]
    DIRECTION INPUT ;
    USE SIGNAL ;
    PORT
      LAYER M4 ;
        RECT  0 66.72 0.084 66.744 ;
    END
  END wq[285]
  PIN wq[286]
    DIRECTION INPUT ;
    USE SIGNAL ;
    PORT
      LAYER M4 ;
        RECT  0 64.992 0.084 65.016 ;
    END
  END wq[286]
  PIN wq[287]
    DIRECTION INPUT ;
    USE SIGNAL ;
    PORT
      LAYER M4 ;
        RECT  0 66.432 0.084 66.456 ;
    END
  END wq[287]
  PIN wq[288]
    DIRECTION INPUT ;
    USE SIGNAL ;
    PORT
      LAYER M4 ;
        RECT  0 68.448 0.084 68.472 ;
    END
  END wq[288]
  PIN wq[289]
    DIRECTION INPUT ;
    USE SIGNAL ;
    PORT
      LAYER M4 ;
        RECT  0 68.256 0.084 68.28 ;
    END
  END wq[289]
  PIN wq[28]
    DIRECTION INPUT ;
    USE SIGNAL ;
    PORT
      LAYER M5 ;
        RECT  29.856 0 29.88 0.084 ;
    END
  END wq[28]
  PIN wq[290]
    DIRECTION INPUT ;
    USE SIGNAL ;
    PORT
      LAYER M4 ;
        RECT  0 68.352 0.084 68.376 ;
    END
  END wq[290]
  PIN wq[291]
    DIRECTION INPUT ;
    USE SIGNAL ;
    PORT
      LAYER M4 ;
        RECT  0 79.296 0.084 79.32 ;
    END
  END wq[291]
  PIN wq[292]
    DIRECTION INPUT ;
    USE SIGNAL ;
    PORT
      LAYER M4 ;
        RECT  0 70.272 0.084 70.296 ;
    END
  END wq[292]
  PIN wq[293]
    DIRECTION INPUT ;
    USE SIGNAL ;
    PORT
      LAYER M4 ;
        RECT  0 70.08 0.084 70.104 ;
    END
  END wq[293]
  PIN wq[294]
    DIRECTION INPUT ;
    USE SIGNAL ;
    PORT
      LAYER M4 ;
        RECT  0 68.736 0.084 68.76 ;
    END
  END wq[294]
  PIN wq[295]
    DIRECTION INPUT ;
    USE SIGNAL ;
    PORT
      LAYER M4 ;
        RECT  0 69.504 0.084 69.528 ;
    END
  END wq[295]
  PIN wq[296]
    DIRECTION INPUT ;
    USE SIGNAL ;
    PORT
      LAYER M4 ;
        RECT  0 73.536 0.084 73.56 ;
    END
  END wq[296]
  PIN wq[297]
    DIRECTION INPUT ;
    USE SIGNAL ;
    PORT
      LAYER M4 ;
        RECT  0 73.344 0.084 73.368 ;
    END
  END wq[297]
  PIN wq[298]
    DIRECTION INPUT ;
    USE SIGNAL ;
    PORT
      LAYER M4 ;
        RECT  0 71.712 0.084 71.736 ;
    END
  END wq[298]
  PIN wq[299]
    DIRECTION INPUT ;
    USE SIGNAL ;
    PORT
      LAYER M4 ;
        RECT  0 70.848 0.084 70.872 ;
    END
  END wq[299]
  PIN wq[29]
    DIRECTION INPUT ;
    USE SIGNAL ;
    PORT
      LAYER M5 ;
        RECT  29.76 0 29.784 0.084 ;
    END
  END wq[29]
  PIN wq[2]
    DIRECTION INPUT ;
    USE SIGNAL ;
    PORT
      LAYER M5 ;
        RECT  63.552 0 63.576 0.084 ;
    END
  END wq[2]
  PIN wq[300]
    DIRECTION INPUT ;
    USE SIGNAL ;
    PORT
      LAYER M4 ;
        RECT  0 73.248 0.084 73.272 ;
    END
  END wq[300]
  PIN wq[301]
    DIRECTION INPUT ;
    USE SIGNAL ;
    PORT
      LAYER M4 ;
        RECT  0 72.096 0.084 72.12 ;
    END
  END wq[301]
  PIN wq[302]
    DIRECTION INPUT ;
    USE SIGNAL ;
    PORT
      LAYER M4 ;
        RECT  0 72.768 0.084 72.792 ;
    END
  END wq[302]
  PIN wq[303]
    DIRECTION INPUT ;
    USE SIGNAL ;
    PORT
      LAYER M4 ;
        RECT  0 69.696 0.084 69.72 ;
    END
  END wq[303]
  PIN wq[304]
    DIRECTION INPUT ;
    USE SIGNAL ;
    PORT
      LAYER M4 ;
        RECT  0 74.784 0.084 74.808 ;
    END
  END wq[304]
  PIN wq[305]
    DIRECTION INPUT ;
    USE SIGNAL ;
    PORT
      LAYER M4 ;
        RECT  0 74.592 0.084 74.616 ;
    END
  END wq[305]
  PIN wq[306]
    DIRECTION INPUT ;
    USE SIGNAL ;
    PORT
      LAYER M4 ;
        RECT  0 74.496 0.084 74.52 ;
    END
  END wq[306]
  PIN wq[307]
    DIRECTION INPUT ;
    USE SIGNAL ;
    PORT
      LAYER M4 ;
        RECT  0 74.4 0.084 74.424 ;
    END
  END wq[307]
  PIN wq[308]
    DIRECTION INPUT ;
    USE SIGNAL ;
    PORT
      LAYER M4 ;
        RECT  0 74.208 0.084 74.232 ;
    END
  END wq[308]
  PIN wq[309]
    DIRECTION INPUT ;
    USE SIGNAL ;
    PORT
      LAYER M4 ;
        RECT  0 74.112 0.084 74.136 ;
    END
  END wq[309]
  PIN wq[30]
    DIRECTION INPUT ;
    USE SIGNAL ;
    PORT
      LAYER M5 ;
        RECT  30.048 0 30.072 0.084 ;
    END
  END wq[30]
  PIN wq[310]
    DIRECTION INPUT ;
    USE SIGNAL ;
    PORT
      LAYER M4 ;
        RECT  0 74.304 0.084 74.328 ;
    END
  END wq[310]
  PIN wq[311]
    DIRECTION INPUT ;
    USE SIGNAL ;
    PORT
      LAYER M4 ;
        RECT  0 73.92 0.084 73.944 ;
    END
  END wq[311]
  PIN wq[312]
    DIRECTION INPUT ;
    USE SIGNAL ;
    PORT
      LAYER M4 ;
        RECT  0 96.288 0.084 96.312 ;
    END
  END wq[312]
  PIN wq[313]
    DIRECTION INPUT ;
    USE SIGNAL ;
    PORT
      LAYER M4 ;
        RECT  0 95.904 0.084 95.928 ;
    END
  END wq[313]
  PIN wq[314]
    DIRECTION INPUT ;
    USE SIGNAL ;
    PORT
      LAYER M4 ;
        RECT  0 95.808 0.084 95.832 ;
    END
  END wq[314]
  PIN wq[315]
    DIRECTION INPUT ;
    USE SIGNAL ;
    PORT
      LAYER M4 ;
        RECT  0 94.56 0.084 94.584 ;
    END
  END wq[315]
  PIN wq[316]
    DIRECTION INPUT ;
    USE SIGNAL ;
    PORT
      LAYER M4 ;
        RECT  0 95.52 0.084 95.544 ;
    END
  END wq[316]
  PIN wq[317]
    DIRECTION INPUT ;
    USE SIGNAL ;
    PORT
      LAYER M4 ;
        RECT  0 95.232 0.084 95.256 ;
    END
  END wq[317]
  PIN wq[318]
    DIRECTION INPUT ;
    USE SIGNAL ;
    PORT
      LAYER M4 ;
        RECT  0 96 0.084 96.024 ;
    END
  END wq[318]
  PIN wq[319]
    DIRECTION INPUT ;
    USE SIGNAL ;
    PORT
      LAYER M4 ;
        RECT  0 93.888 0.084 93.912 ;
    END
  END wq[319]
  PIN wq[31]
    DIRECTION INPUT ;
    USE SIGNAL ;
    PORT
      LAYER M5 ;
        RECT  35.232 0 35.256 0.084 ;
    END
  END wq[31]
  PIN wq[320]
    DIRECTION INPUT ;
    USE SIGNAL ;
    PORT
      LAYER M4 ;
        RECT  0 86.88 0.084 86.904 ;
    END
  END wq[320]
  PIN wq[321]
    DIRECTION INPUT ;
    USE SIGNAL ;
    PORT
      LAYER M4 ;
        RECT  0 86.784 0.084 86.808 ;
    END
  END wq[321]
  PIN wq[322]
    DIRECTION INPUT ;
    USE SIGNAL ;
    PORT
      LAYER M4 ;
        RECT  0 87.456 0.084 87.48 ;
    END
  END wq[322]
  PIN wq[323]
    DIRECTION INPUT ;
    USE SIGNAL ;
    PORT
      LAYER M4 ;
        RECT  0 86.496 0.084 86.52 ;
    END
  END wq[323]
  PIN wq[324]
    DIRECTION INPUT ;
    USE SIGNAL ;
    PORT
      LAYER M4 ;
        RECT  0 87.264 0.084 87.288 ;
    END
  END wq[324]
  PIN wq[325]
    DIRECTION INPUT ;
    USE SIGNAL ;
    PORT
      LAYER M4 ;
        RECT  0 87.36 0.084 87.384 ;
    END
  END wq[325]
  PIN wq[326]
    DIRECTION INPUT ;
    USE SIGNAL ;
    PORT
      LAYER M4 ;
        RECT  0 87.84 0.084 87.864 ;
    END
  END wq[326]
  PIN wq[327]
    DIRECTION INPUT ;
    USE SIGNAL ;
    PORT
      LAYER M4 ;
        RECT  0 84.864 0.084 84.888 ;
    END
  END wq[327]
  PIN wq[328]
    DIRECTION INPUT ;
    USE SIGNAL ;
    PORT
      LAYER M4 ;
        RECT  0 99.072 0.084 99.096 ;
    END
  END wq[328]
  PIN wq[329]
    DIRECTION INPUT ;
    USE SIGNAL ;
    PORT
      LAYER M4 ;
        RECT  0 98.88 0.084 98.904 ;
    END
  END wq[329]
  PIN wq[32]
    DIRECTION INPUT ;
    USE SIGNAL ;
    PORT
      LAYER M5 ;
        RECT  35.904 0 35.928 0.084 ;
    END
  END wq[32]
  PIN wq[330]
    DIRECTION INPUT ;
    USE SIGNAL ;
    PORT
      LAYER M4 ;
        RECT  0 98.976 0.084 99 ;
    END
  END wq[330]
  PIN wq[331]
    DIRECTION INPUT ;
    USE SIGNAL ;
    PORT
      LAYER M4 ;
        RECT  0 98.112 0.084 98.136 ;
    END
  END wq[331]
  PIN wq[332]
    DIRECTION INPUT ;
    USE SIGNAL ;
    PORT
      LAYER M4 ;
        RECT  0 99.264 0.084 99.288 ;
    END
  END wq[332]
  PIN wq[333]
    DIRECTION INPUT ;
    USE SIGNAL ;
    PORT
      LAYER M4 ;
        RECT  0 99.456 0.084 99.48 ;
    END
  END wq[333]
  PIN wq[334]
    DIRECTION INPUT ;
    USE SIGNAL ;
    PORT
      LAYER M4 ;
        RECT  0 99.36 0.084 99.384 ;
    END
  END wq[334]
  PIN wq[335]
    DIRECTION INPUT ;
    USE SIGNAL ;
    PORT
      LAYER M4 ;
        RECT  0 96.768 0.084 96.792 ;
    END
  END wq[335]
  PIN wq[336]
    DIRECTION INPUT ;
    USE SIGNAL ;
    PORT
      LAYER M4 ;
        RECT  0 106.464 0.084 106.488 ;
    END
  END wq[336]
  PIN wq[337]
    DIRECTION INPUT ;
    USE SIGNAL ;
    PORT
      LAYER M4 ;
        RECT  0 106.272 0.084 106.296 ;
    END
  END wq[337]
  PIN wq[338]
    DIRECTION INPUT ;
    USE SIGNAL ;
    PORT
      LAYER M4 ;
        RECT  0 106.56 0.084 106.584 ;
    END
  END wq[338]
  PIN wq[339]
    DIRECTION INPUT ;
    USE SIGNAL ;
    PORT
      LAYER M4 ;
        RECT  0 106.368 0.084 106.392 ;
    END
  END wq[339]
  PIN wq[33]
    DIRECTION INPUT ;
    USE SIGNAL ;
    PORT
      LAYER M5 ;
        RECT  36.096 0 36.12 0.084 ;
    END
  END wq[33]
  PIN wq[340]
    DIRECTION INPUT ;
    USE SIGNAL ;
    PORT
      LAYER M4 ;
        RECT  0 107.52 0.084 107.544 ;
    END
  END wq[340]
  PIN wq[341]
    DIRECTION INPUT ;
    USE SIGNAL ;
    PORT
      LAYER M4 ;
        RECT  0 107.616 0.084 107.64 ;
    END
  END wq[341]
  PIN wq[342]
    DIRECTION INPUT ;
    USE SIGNAL ;
    PORT
      LAYER M4 ;
        RECT  0 107.424 0.084 107.448 ;
    END
  END wq[342]
  PIN wq[343]
    DIRECTION INPUT ;
    USE SIGNAL ;
    PORT
      LAYER M4 ;
        RECT  0 106.176 0.084 106.2 ;
    END
  END wq[343]
  PIN wq[344]
    DIRECTION INPUT ;
    USE SIGNAL ;
    PORT
      LAYER M4 ;
        RECT  0 104.736 0.084 104.76 ;
    END
  END wq[344]
  PIN wq[345]
    DIRECTION INPUT ;
    USE SIGNAL ;
    PORT
      LAYER M4 ;
        RECT  0 104.64 0.084 104.664 ;
    END
  END wq[345]
  PIN wq[346]
    DIRECTION INPUT ;
    USE SIGNAL ;
    PORT
      LAYER M4 ;
        RECT  0 104.928 0.084 104.952 ;
    END
  END wq[346]
  PIN wq[347]
    DIRECTION INPUT ;
    USE SIGNAL ;
    PORT
      LAYER M4 ;
        RECT  0 104.256 0.084 104.28 ;
    END
  END wq[347]
  PIN wq[348]
    DIRECTION INPUT ;
    USE SIGNAL ;
    PORT
      LAYER M4 ;
        RECT  0 105.408 0.084 105.432 ;
    END
  END wq[348]
  PIN wq[349]
    DIRECTION INPUT ;
    USE SIGNAL ;
    PORT
      LAYER M4 ;
        RECT  0 105.504 0.084 105.528 ;
    END
  END wq[349]
  PIN wq[34]
    DIRECTION INPUT ;
    USE SIGNAL ;
    PORT
      LAYER M5 ;
        RECT  36 0 36.024 0.084 ;
    END
  END wq[34]
  PIN wq[350]
    DIRECTION INPUT ;
    USE SIGNAL ;
    PORT
      LAYER M4 ;
        RECT  0 105.12 0.084 105.144 ;
    END
  END wq[350]
  PIN wq[351]
    DIRECTION INPUT ;
    USE SIGNAL ;
    PORT
      LAYER M4 ;
        RECT  0 100.416 0.084 100.44 ;
    END
  END wq[351]
  PIN wq[352]
    DIRECTION INPUT ;
    USE SIGNAL ;
    PORT
      LAYER M4 ;
        RECT  0 118.08 0.084 118.104 ;
    END
  END wq[352]
  PIN wq[353]
    DIRECTION INPUT ;
    USE SIGNAL ;
    PORT
      LAYER M4 ;
        RECT  0 117.888 0.084 117.912 ;
    END
  END wq[353]
  PIN wq[354]
    DIRECTION INPUT ;
    USE SIGNAL ;
    PORT
      LAYER M4 ;
        RECT  0 117.696 0.084 117.72 ;
    END
  END wq[354]
  PIN wq[355]
    DIRECTION INPUT ;
    USE SIGNAL ;
    PORT
      LAYER M4 ;
        RECT  0 117.792 0.084 117.816 ;
    END
  END wq[355]
  PIN wq[356]
    DIRECTION INPUT ;
    USE SIGNAL ;
    PORT
      LAYER M4 ;
        RECT  0 116.64 0.084 116.664 ;
    END
  END wq[356]
  PIN wq[357]
    DIRECTION INPUT ;
    USE SIGNAL ;
    PORT
      LAYER M4 ;
        RECT  0 116.736 0.084 116.76 ;
    END
  END wq[357]
  PIN wq[358]
    DIRECTION INPUT ;
    USE SIGNAL ;
    PORT
      LAYER M4 ;
        RECT  0 117.12 0.084 117.144 ;
    END
  END wq[358]
  PIN wq[359]
    DIRECTION INPUT ;
    USE SIGNAL ;
    PORT
      LAYER M4 ;
        RECT  0 118.656 0.084 118.68 ;
    END
  END wq[359]
  PIN wq[35]
    DIRECTION INPUT ;
    USE SIGNAL ;
    PORT
      LAYER M5 ;
        RECT  36.192 0 36.216 0.084 ;
    END
  END wq[35]
  PIN wq[360]
    DIRECTION INPUT ;
    USE SIGNAL ;
    PORT
      LAYER M4 ;
        RECT  0 117.6 0.084 117.624 ;
    END
  END wq[360]
  PIN wq[361]
    DIRECTION INPUT ;
    USE SIGNAL ;
    PORT
      LAYER M4 ;
        RECT  0 117.504 0.084 117.528 ;
    END
  END wq[361]
  PIN wq[362]
    DIRECTION INPUT ;
    USE SIGNAL ;
    PORT
      LAYER M4 ;
        RECT  0 117.024 0.084 117.048 ;
    END
  END wq[362]
  PIN wq[363]
    DIRECTION INPUT ;
    USE SIGNAL ;
    PORT
      LAYER M4 ;
        RECT  0 116.928 0.084 116.952 ;
    END
  END wq[363]
  PIN wq[364]
    DIRECTION INPUT ;
    USE SIGNAL ;
    PORT
      LAYER M4 ;
        RECT  0 116.256 0.084 116.28 ;
    END
  END wq[364]
  PIN wq[365]
    DIRECTION INPUT ;
    USE SIGNAL ;
    PORT
      LAYER M4 ;
        RECT  0 116.448 0.084 116.472 ;
    END
  END wq[365]
  PIN wq[366]
    DIRECTION INPUT ;
    USE SIGNAL ;
    PORT
      LAYER M4 ;
        RECT  0 116.352 0.084 116.376 ;
    END
  END wq[366]
  PIN wq[367]
    DIRECTION INPUT ;
    USE SIGNAL ;
    PORT
      LAYER M4 ;
        RECT  0 116.832 0.084 116.856 ;
    END
  END wq[367]
  PIN wq[368]
    DIRECTION INPUT ;
    USE SIGNAL ;
    PORT
      LAYER M5 ;
        RECT  20.928 128.233 20.952 128.317 ;
    END
  END wq[368]
  PIN wq[369]
    DIRECTION INPUT ;
    USE SIGNAL ;
    PORT
      LAYER M5 ;
        RECT  20.832 128.233 20.856 128.317 ;
    END
  END wq[369]
  PIN wq[36]
    DIRECTION INPUT ;
    USE SIGNAL ;
    PORT
      LAYER M5 ;
        RECT  36.96 0 36.984 0.084 ;
    END
  END wq[36]
  PIN wq[370]
    DIRECTION INPUT ;
    USE SIGNAL ;
    PORT
      LAYER M5 ;
        RECT  21.12 128.233 21.144 128.317 ;
    END
  END wq[370]
  PIN wq[371]
    DIRECTION INPUT ;
    USE SIGNAL ;
    PORT
      LAYER M5 ;
        RECT  27.744 128.233 27.768 128.317 ;
    END
  END wq[371]
  PIN wq[372]
    DIRECTION INPUT ;
    USE SIGNAL ;
    PORT
      LAYER M5 ;
        RECT  21.504 128.233 21.528 128.317 ;
    END
  END wq[372]
  PIN wq[373]
    DIRECTION INPUT ;
    USE SIGNAL ;
    PORT
      LAYER M5 ;
        RECT  21.312 128.233 21.336 128.317 ;
    END
  END wq[373]
  PIN wq[374]
    DIRECTION INPUT ;
    USE SIGNAL ;
    PORT
      LAYER M5 ;
        RECT  21.216 128.233 21.24 128.317 ;
    END
  END wq[374]
  PIN wq[375]
    DIRECTION INPUT ;
    USE SIGNAL ;
    PORT
      LAYER M5 ;
        RECT  27.84 128.233 27.864 128.317 ;
    END
  END wq[375]
  PIN wq[376]
    DIRECTION INPUT ;
    USE SIGNAL ;
    PORT
      LAYER M5 ;
        RECT  36 128.233 36.024 128.317 ;
    END
  END wq[376]
  PIN wq[377]
    DIRECTION INPUT ;
    USE SIGNAL ;
    PORT
      LAYER M5 ;
        RECT  36.192 128.233 36.216 128.317 ;
    END
  END wq[377]
  PIN wq[378]
    DIRECTION INPUT ;
    USE SIGNAL ;
    PORT
      LAYER M5 ;
        RECT  36.384 128.233 36.408 128.317 ;
    END
  END wq[378]
  PIN wq[379]
    DIRECTION INPUT ;
    USE SIGNAL ;
    PORT
      LAYER M5 ;
        RECT  36.672 128.233 36.696 128.317 ;
    END
  END wq[379]
  PIN wq[37]
    DIRECTION INPUT ;
    USE SIGNAL ;
    PORT
      LAYER M5 ;
        RECT  36.864 0 36.888 0.084 ;
    END
  END wq[37]
  PIN wq[380]
    DIRECTION INPUT ;
    USE SIGNAL ;
    PORT
      LAYER M5 ;
        RECT  36.096 128.233 36.12 128.317 ;
    END
  END wq[380]
  PIN wq[381]
    DIRECTION INPUT ;
    USE SIGNAL ;
    PORT
      LAYER M5 ;
        RECT  36.288 128.233 36.312 128.317 ;
    END
  END wq[381]
  PIN wq[382]
    DIRECTION INPUT ;
    USE SIGNAL ;
    PORT
      LAYER M5 ;
        RECT  36.48 128.233 36.504 128.317 ;
    END
  END wq[382]
  PIN wq[383]
    DIRECTION INPUT ;
    USE SIGNAL ;
    PORT
      LAYER M5 ;
        RECT  36.576 128.233 36.6 128.317 ;
    END
  END wq[383]
  PIN wq[384]
    DIRECTION INPUT ;
    USE SIGNAL ;
    PORT
      LAYER M5 ;
        RECT  29.28 128.233 29.304 128.317 ;
    END
  END wq[384]
  PIN wq[385]
    DIRECTION INPUT ;
    USE SIGNAL ;
    PORT
      LAYER M5 ;
        RECT  29.184 128.233 29.208 128.317 ;
    END
  END wq[385]
  PIN wq[386]
    DIRECTION INPUT ;
    USE SIGNAL ;
    PORT
      LAYER M5 ;
        RECT  29.376 128.233 29.4 128.317 ;
    END
  END wq[386]
  PIN wq[387]
    DIRECTION INPUT ;
    USE SIGNAL ;
    PORT
      LAYER M5 ;
        RECT  29.472 128.233 29.496 128.317 ;
    END
  END wq[387]
  PIN wq[388]
    DIRECTION INPUT ;
    USE SIGNAL ;
    PORT
      LAYER M5 ;
        RECT  28.992 128.233 29.016 128.317 ;
    END
  END wq[388]
  PIN wq[389]
    DIRECTION INPUT ;
    USE SIGNAL ;
    PORT
      LAYER M5 ;
        RECT  29.088 128.233 29.112 128.317 ;
    END
  END wq[389]
  PIN wq[38]
    DIRECTION INPUT ;
    USE SIGNAL ;
    PORT
      LAYER M5 ;
        RECT  36.672 0 36.696 0.084 ;
    END
  END wq[38]
  PIN wq[390]
    DIRECTION INPUT ;
    USE SIGNAL ;
    PORT
      LAYER M5 ;
        RECT  29.568 128.233 29.592 128.317 ;
    END
  END wq[390]
  PIN wq[391]
    DIRECTION INPUT ;
    USE SIGNAL ;
    PORT
      LAYER M5 ;
        RECT  29.664 128.233 29.688 128.317 ;
    END
  END wq[391]
  PIN wq[392]
    DIRECTION INPUT ;
    USE SIGNAL ;
    PORT
      LAYER M5 ;
        RECT  49.248 128.233 49.272 128.317 ;
    END
  END wq[392]
  PIN wq[393]
    DIRECTION INPUT ;
    USE SIGNAL ;
    PORT
      LAYER M5 ;
        RECT  50.304 128.233 50.328 128.317 ;
    END
  END wq[393]
  PIN wq[394]
    DIRECTION INPUT ;
    USE SIGNAL ;
    PORT
      LAYER M5 ;
        RECT  50.208 128.233 50.232 128.317 ;
    END
  END wq[394]
  PIN wq[395]
    DIRECTION INPUT ;
    USE SIGNAL ;
    PORT
      LAYER M5 ;
        RECT  50.016 128.233 50.04 128.317 ;
    END
  END wq[395]
  PIN wq[396]
    DIRECTION INPUT ;
    USE SIGNAL ;
    PORT
      LAYER M5 ;
        RECT  50.688 128.233 50.712 128.317 ;
    END
  END wq[396]
  PIN wq[397]
    DIRECTION INPUT ;
    USE SIGNAL ;
    PORT
      LAYER M5 ;
        RECT  50.88 128.233 50.904 128.317 ;
    END
  END wq[397]
  PIN wq[398]
    DIRECTION INPUT ;
    USE SIGNAL ;
    PORT
      LAYER M5 ;
        RECT  49.536 128.233 49.56 128.317 ;
    END
  END wq[398]
  PIN wq[399]
    DIRECTION INPUT ;
    USE SIGNAL ;
    PORT
      LAYER M5 ;
        RECT  49.44 128.233 49.464 128.317 ;
    END
  END wq[399]
  PIN wq[39]
    DIRECTION INPUT ;
    USE SIGNAL ;
    PORT
      LAYER M5 ;
        RECT  36.288 0 36.312 0.084 ;
    END
  END wq[39]
  PIN wq[3]
    DIRECTION INPUT ;
    USE SIGNAL ;
    PORT
      LAYER M5 ;
        RECT  64.512 0 64.536 0.084 ;
    END
  END wq[3]
  PIN wq[400]
    DIRECTION INPUT ;
    USE SIGNAL ;
    PORT
      LAYER M5 ;
        RECT  60.864 128.233 60.888 128.317 ;
    END
  END wq[400]
  PIN wq[401]
    DIRECTION INPUT ;
    USE SIGNAL ;
    PORT
      LAYER M5 ;
        RECT  60.672 128.233 60.696 128.317 ;
    END
  END wq[401]
  PIN wq[402]
    DIRECTION INPUT ;
    USE SIGNAL ;
    PORT
      LAYER M5 ;
        RECT  60.96 128.233 60.984 128.317 ;
    END
  END wq[402]
  PIN wq[403]
    DIRECTION INPUT ;
    USE SIGNAL ;
    PORT
      LAYER M5 ;
        RECT  60.576 128.233 60.6 128.317 ;
    END
  END wq[403]
  PIN wq[404]
    DIRECTION INPUT ;
    USE SIGNAL ;
    PORT
      LAYER M5 ;
        RECT  61.248 128.233 61.272 128.317 ;
    END
  END wq[404]
  PIN wq[405]
    DIRECTION INPUT ;
    USE SIGNAL ;
    PORT
      LAYER M5 ;
        RECT  61.056 128.233 61.08 128.317 ;
    END
  END wq[405]
  PIN wq[406]
    DIRECTION INPUT ;
    USE SIGNAL ;
    PORT
      LAYER M5 ;
        RECT  61.152 128.233 61.176 128.317 ;
    END
  END wq[406]
  PIN wq[407]
    DIRECTION INPUT ;
    USE SIGNAL ;
    PORT
      LAYER M5 ;
        RECT  60.384 128.233 60.408 128.317 ;
    END
  END wq[407]
  PIN wq[408]
    DIRECTION INPUT ;
    USE SIGNAL ;
    PORT
      LAYER M5 ;
        RECT  50.592 128.233 50.616 128.317 ;
    END
  END wq[408]
  PIN wq[409]
    DIRECTION INPUT ;
    USE SIGNAL ;
    PORT
      LAYER M5 ;
        RECT  50.4 128.233 50.424 128.317 ;
    END
  END wq[409]
  PIN wq[40]
    DIRECTION INPUT ;
    USE SIGNAL ;
    PORT
      LAYER M5 ;
        RECT  44.064 0 44.088 0.084 ;
    END
  END wq[40]
  PIN wq[410]
    DIRECTION INPUT ;
    USE SIGNAL ;
    PORT
      LAYER M5 ;
        RECT  50.496 128.233 50.52 128.317 ;
    END
  END wq[410]
  PIN wq[411]
    DIRECTION INPUT ;
    USE SIGNAL ;
    PORT
      LAYER M5 ;
        RECT  52.032 128.233 52.056 128.317 ;
    END
  END wq[411]
  PIN wq[412]
    DIRECTION INPUT ;
    USE SIGNAL ;
    PORT
      LAYER M5 ;
        RECT  51.552 128.233 51.576 128.317 ;
    END
  END wq[412]
  PIN wq[413]
    DIRECTION INPUT ;
    USE SIGNAL ;
    PORT
      LAYER M5 ;
        RECT  50.976 128.233 51 128.317 ;
    END
  END wq[413]
  PIN wq[414]
    DIRECTION INPUT ;
    USE SIGNAL ;
    PORT
      LAYER M5 ;
        RECT  49.344 128.233 49.368 128.317 ;
    END
  END wq[414]
  PIN wq[415]
    DIRECTION INPUT ;
    USE SIGNAL ;
    PORT
      LAYER M5 ;
        RECT  52.896 128.233 52.92 128.317 ;
    END
  END wq[415]
  PIN wq[416]
    DIRECTION INPUT ;
    USE SIGNAL ;
    PORT
      LAYER M5 ;
        RECT  51.648 128.233 51.672 128.317 ;
    END
  END wq[416]
  PIN wq[417]
    DIRECTION INPUT ;
    USE SIGNAL ;
    PORT
      LAYER M5 ;
        RECT  51.936 128.233 51.96 128.317 ;
    END
  END wq[417]
  PIN wq[418]
    DIRECTION INPUT ;
    USE SIGNAL ;
    PORT
      LAYER M5 ;
        RECT  52.128 128.233 52.152 128.317 ;
    END
  END wq[418]
  PIN wq[419]
    DIRECTION INPUT ;
    USE SIGNAL ;
    PORT
      LAYER M5 ;
        RECT  51.744 128.233 51.768 128.317 ;
    END
  END wq[419]
  PIN wq[41]
    DIRECTION INPUT ;
    USE SIGNAL ;
    PORT
      LAYER M5 ;
        RECT  44.256 0 44.28 0.084 ;
    END
  END wq[41]
  PIN wq[420]
    DIRECTION INPUT ;
    USE SIGNAL ;
    PORT
      LAYER M5 ;
        RECT  52.8 128.233 52.824 128.317 ;
    END
  END wq[420]
  PIN wq[421]
    DIRECTION INPUT ;
    USE SIGNAL ;
    PORT
      LAYER M5 ;
        RECT  52.512 128.233 52.536 128.317 ;
    END
  END wq[421]
  PIN wq[422]
    DIRECTION INPUT ;
    USE SIGNAL ;
    PORT
      LAYER M5 ;
        RECT  52.704 128.233 52.728 128.317 ;
    END
  END wq[422]
  PIN wq[423]
    DIRECTION INPUT ;
    USE SIGNAL ;
    PORT
      LAYER M5 ;
        RECT  51.84 128.233 51.864 128.317 ;
    END
  END wq[423]
  PIN wq[424]
    DIRECTION INPUT ;
    USE SIGNAL ;
    PORT
      LAYER M5 ;
        RECT  69.216 128.233 69.24 128.317 ;
    END
  END wq[424]
  PIN wq[425]
    DIRECTION INPUT ;
    USE SIGNAL ;
    PORT
      LAYER M5 ;
        RECT  69.12 128.233 69.144 128.317 ;
    END
  END wq[425]
  PIN wq[426]
    DIRECTION INPUT ;
    USE SIGNAL ;
    PORT
      LAYER M5 ;
        RECT  69.312 128.233 69.336 128.317 ;
    END
  END wq[426]
  PIN wq[427]
    DIRECTION INPUT ;
    USE SIGNAL ;
    PORT
      LAYER M5 ;
        RECT  70.272 128.233 70.296 128.317 ;
    END
  END wq[427]
  PIN wq[428]
    DIRECTION INPUT ;
    USE SIGNAL ;
    PORT
      LAYER M5 ;
        RECT  69.792 128.233 69.816 128.317 ;
    END
  END wq[428]
  PIN wq[429]
    DIRECTION INPUT ;
    USE SIGNAL ;
    PORT
      LAYER M5 ;
        RECT  69.696 128.233 69.72 128.317 ;
    END
  END wq[429]
  PIN wq[42]
    DIRECTION INPUT ;
    USE SIGNAL ;
    PORT
      LAYER M5 ;
        RECT  44.448 0 44.472 0.084 ;
    END
  END wq[42]
  PIN wq[430]
    DIRECTION INPUT ;
    USE SIGNAL ;
    PORT
      LAYER M5 ;
        RECT  69.408 128.233 69.432 128.317 ;
    END
  END wq[430]
  PIN wq[431]
    DIRECTION INPUT ;
    USE SIGNAL ;
    PORT
      LAYER M5 ;
        RECT  72.192 128.233 72.216 128.317 ;
    END
  END wq[431]
  PIN wq[432]
    DIRECTION INPUT ;
    USE SIGNAL ;
    PORT
      LAYER M5 ;
        RECT  82.752 128.233 82.776 128.317 ;
    END
  END wq[432]
  PIN wq[433]
    DIRECTION INPUT ;
    USE SIGNAL ;
    PORT
      LAYER M5 ;
        RECT  83.616 128.233 83.64 128.317 ;
    END
  END wq[433]
  PIN wq[434]
    DIRECTION INPUT ;
    USE SIGNAL ;
    PORT
      LAYER M5 ;
        RECT  83.328 128.233 83.352 128.317 ;
    END
  END wq[434]
  PIN wq[435]
    DIRECTION INPUT ;
    USE SIGNAL ;
    PORT
      LAYER M5 ;
        RECT  86.784 128.233 86.808 128.317 ;
    END
  END wq[435]
  PIN wq[436]
    DIRECTION INPUT ;
    USE SIGNAL ;
    PORT
      LAYER M5 ;
        RECT  83.136 128.233 83.16 128.317 ;
    END
  END wq[436]
  PIN wq[437]
    DIRECTION INPUT ;
    USE SIGNAL ;
    PORT
      LAYER M5 ;
        RECT  83.232 128.233 83.256 128.317 ;
    END
  END wq[437]
  PIN wq[438]
    DIRECTION INPUT ;
    USE SIGNAL ;
    PORT
      LAYER M5 ;
        RECT  83.52 128.233 83.544 128.317 ;
    END
  END wq[438]
  PIN wq[439]
    DIRECTION INPUT ;
    USE SIGNAL ;
    PORT
      LAYER M5 ;
        RECT  86.208 128.233 86.232 128.317 ;
    END
  END wq[439]
  PIN wq[43]
    DIRECTION INPUT ;
    USE SIGNAL ;
    PORT
      LAYER M5 ;
        RECT  44.64 0 44.664 0.084 ;
    END
  END wq[43]
  PIN wq[440]
    DIRECTION INPUT ;
    USE SIGNAL ;
    PORT
      LAYER M5 ;
        RECT  83.904 128.233 83.928 128.317 ;
    END
  END wq[440]
  PIN wq[441]
    DIRECTION INPUT ;
    USE SIGNAL ;
    PORT
      LAYER M5 ;
        RECT  84.288 128.233 84.312 128.317 ;
    END
  END wq[441]
  PIN wq[442]
    DIRECTION INPUT ;
    USE SIGNAL ;
    PORT
      LAYER M5 ;
        RECT  84 128.233 84.024 128.317 ;
    END
  END wq[442]
  PIN wq[443]
    DIRECTION INPUT ;
    USE SIGNAL ;
    PORT
      LAYER M5 ;
        RECT  85.248 128.233 85.272 128.317 ;
    END
  END wq[443]
  PIN wq[444]
    DIRECTION INPUT ;
    USE SIGNAL ;
    PORT
      LAYER M5 ;
        RECT  84.672 128.233 84.696 128.317 ;
    END
  END wq[444]
  PIN wq[445]
    DIRECTION INPUT ;
    USE SIGNAL ;
    PORT
      LAYER M5 ;
        RECT  84.48 128.233 84.504 128.317 ;
    END
  END wq[445]
  PIN wq[446]
    DIRECTION INPUT ;
    USE SIGNAL ;
    PORT
      LAYER M5 ;
        RECT  84.768 128.233 84.792 128.317 ;
    END
  END wq[446]
  PIN wq[447]
    DIRECTION INPUT ;
    USE SIGNAL ;
    PORT
      LAYER M5 ;
        RECT  85.632 128.233 85.656 128.317 ;
    END
  END wq[447]
  PIN wq[448]
    DIRECTION INPUT ;
    USE SIGNAL ;
    PORT
      LAYER M5 ;
        RECT  84.096 128.233 84.12 128.317 ;
    END
  END wq[448]
  PIN wq[449]
    DIRECTION INPUT ;
    USE SIGNAL ;
    PORT
      LAYER M5 ;
        RECT  85.152 128.233 85.176 128.317 ;
    END
  END wq[449]
  PIN wq[44]
    DIRECTION INPUT ;
    USE SIGNAL ;
    PORT
      LAYER M5 ;
        RECT  43.872 0 43.896 0.084 ;
    END
  END wq[44]
  PIN wq[450]
    DIRECTION INPUT ;
    USE SIGNAL ;
    PORT
      LAYER M5 ;
        RECT  84.192 128.233 84.216 128.317 ;
    END
  END wq[450]
  PIN wq[451]
    DIRECTION INPUT ;
    USE SIGNAL ;
    PORT
      LAYER M5 ;
        RECT  85.536 128.233 85.56 128.317 ;
    END
  END wq[451]
  PIN wq[452]
    DIRECTION INPUT ;
    USE SIGNAL ;
    PORT
      LAYER M5 ;
        RECT  84.384 128.233 84.408 128.317 ;
    END
  END wq[452]
  PIN wq[453]
    DIRECTION INPUT ;
    USE SIGNAL ;
    PORT
      LAYER M5 ;
        RECT  83.712 128.233 83.736 128.317 ;
    END
  END wq[453]
  PIN wq[454]
    DIRECTION INPUT ;
    USE SIGNAL ;
    PORT
      LAYER M5 ;
        RECT  82.848 128.233 82.872 128.317 ;
    END
  END wq[454]
  PIN wq[455]
    DIRECTION INPUT ;
    USE SIGNAL ;
    PORT
      LAYER M5 ;
        RECT  85.824 128.233 85.848 128.317 ;
    END
  END wq[455]
  PIN wq[456]
    DIRECTION INPUT ;
    USE SIGNAL ;
    PORT
      LAYER M5 ;
        RECT  82.368 128.233 82.392 128.317 ;
    END
  END wq[456]
  PIN wq[457]
    DIRECTION INPUT ;
    USE SIGNAL ;
    PORT
      LAYER M5 ;
        RECT  82.56 128.233 82.584 128.317 ;
    END
  END wq[457]
  PIN wq[458]
    DIRECTION INPUT ;
    USE SIGNAL ;
    PORT
      LAYER M5 ;
        RECT  82.176 128.233 82.2 128.317 ;
    END
  END wq[458]
  PIN wq[459]
    DIRECTION INPUT ;
    USE SIGNAL ;
    PORT
      LAYER M5 ;
        RECT  82.464 128.233 82.488 128.317 ;
    END
  END wq[459]
  PIN wq[45]
    DIRECTION INPUT ;
    USE SIGNAL ;
    PORT
      LAYER M5 ;
        RECT  43.968 0 43.992 0.084 ;
    END
  END wq[45]
  PIN wq[460]
    DIRECTION INPUT ;
    USE SIGNAL ;
    PORT
      LAYER M5 ;
        RECT  80.832 128.233 80.856 128.317 ;
    END
  END wq[460]
  PIN wq[461]
    DIRECTION INPUT ;
    USE SIGNAL ;
    PORT
      LAYER M5 ;
        RECT  80.736 128.233 80.76 128.317 ;
    END
  END wq[461]
  PIN wq[462]
    DIRECTION INPUT ;
    USE SIGNAL ;
    PORT
      LAYER M5 ;
        RECT  81.504 128.233 81.528 128.317 ;
    END
  END wq[462]
  PIN wq[463]
    DIRECTION INPUT ;
    USE SIGNAL ;
    PORT
      LAYER M5 ;
        RECT  82.656 128.233 82.68 128.317 ;
    END
  END wq[463]
  PIN wq[464]
    DIRECTION INPUT ;
    USE SIGNAL ;
    PORT
      LAYER M5 ;
        RECT  85.056 128.233 85.08 128.317 ;
    END
  END wq[464]
  PIN wq[465]
    DIRECTION INPUT ;
    USE SIGNAL ;
    PORT
      LAYER M5 ;
        RECT  86.592 128.233 86.616 128.317 ;
    END
  END wq[465]
  PIN wq[466]
    DIRECTION INPUT ;
    USE SIGNAL ;
    PORT
      LAYER M5 ;
        RECT  84.576 128.233 84.6 128.317 ;
    END
  END wq[466]
  PIN wq[467]
    DIRECTION INPUT ;
    USE SIGNAL ;
    PORT
      LAYER M5 ;
        RECT  85.44 128.233 85.464 128.317 ;
    END
  END wq[467]
  PIN wq[468]
    DIRECTION INPUT ;
    USE SIGNAL ;
    PORT
      LAYER M5 ;
        RECT  84.864 128.233 84.888 128.317 ;
    END
  END wq[468]
  PIN wq[469]
    DIRECTION INPUT ;
    USE SIGNAL ;
    PORT
      LAYER M5 ;
        RECT  84.96 128.233 84.984 128.317 ;
    END
  END wq[469]
  PIN wq[46]
    DIRECTION INPUT ;
    USE SIGNAL ;
    PORT
      LAYER M5 ;
        RECT  44.352 0 44.376 0.084 ;
    END
  END wq[46]
  PIN wq[470]
    DIRECTION INPUT ;
    USE SIGNAL ;
    PORT
      LAYER M5 ;
        RECT  86.496 128.233 86.52 128.317 ;
    END
  END wq[470]
  PIN wq[471]
    DIRECTION INPUT ;
    USE SIGNAL ;
    PORT
      LAYER M5 ;
        RECT  86.112 128.233 86.136 128.317 ;
    END
  END wq[471]
  PIN wq[472]
    DIRECTION INPUT ;
    USE SIGNAL ;
    PORT
      LAYER M5 ;
        RECT  76.416 128.233 76.44 128.317 ;
    END
  END wq[472]
  PIN wq[473]
    DIRECTION INPUT ;
    USE SIGNAL ;
    PORT
      LAYER M5 ;
        RECT  76.32 128.233 76.344 128.317 ;
    END
  END wq[473]
  PIN wq[474]
    DIRECTION INPUT ;
    USE SIGNAL ;
    PORT
      LAYER M5 ;
        RECT  76.032 128.233 76.056 128.317 ;
    END
  END wq[474]
  PIN wq[475]
    DIRECTION INPUT ;
    USE SIGNAL ;
    PORT
      LAYER M5 ;
        RECT  75.168 128.233 75.192 128.317 ;
    END
  END wq[475]
  PIN wq[476]
    DIRECTION INPUT ;
    USE SIGNAL ;
    PORT
      LAYER M5 ;
        RECT  74.976 128.233 75 128.317 ;
    END
  END wq[476]
  PIN wq[477]
    DIRECTION INPUT ;
    USE SIGNAL ;
    PORT
      LAYER M5 ;
        RECT  74.88 128.233 74.904 128.317 ;
    END
  END wq[477]
  PIN wq[478]
    DIRECTION INPUT ;
    USE SIGNAL ;
    PORT
      LAYER M5 ;
        RECT  75.072 128.233 75.096 128.317 ;
    END
  END wq[478]
  PIN wq[479]
    DIRECTION INPUT ;
    USE SIGNAL ;
    PORT
      LAYER M5 ;
        RECT  75.552 128.233 75.576 128.317 ;
    END
  END wq[479]
  PIN wq[47]
    DIRECTION INPUT ;
    USE SIGNAL ;
    PORT
      LAYER M5 ;
        RECT  45.216 0 45.24 0.084 ;
    END
  END wq[47]
  PIN wq[480]
    DIRECTION INPUT ;
    USE SIGNAL ;
    PORT
      LAYER M4 ;
        RECT  128.233 67.2 128.317 67.224 ;
    END
  END wq[480]
  PIN wq[481]
    DIRECTION INPUT ;
    USE SIGNAL ;
    PORT
      LAYER M4 ;
        RECT  128.233 67.776 128.317 67.8 ;
    END
  END wq[481]
  PIN wq[482]
    DIRECTION INPUT ;
    USE SIGNAL ;
    PORT
      LAYER M4 ;
        RECT  128.233 67.296 128.317 67.32 ;
    END
  END wq[482]
  PIN wq[483]
    DIRECTION INPUT ;
    USE SIGNAL ;
    PORT
      LAYER M4 ;
        RECT  128.233 67.872 128.317 67.896 ;
    END
  END wq[483]
  PIN wq[484]
    DIRECTION INPUT ;
    USE SIGNAL ;
    PORT
      LAYER M5 ;
        RECT  64.032 128.233 64.056 128.317 ;
    END
  END wq[484]
  PIN wq[485]
    DIRECTION INPUT ;
    USE SIGNAL ;
    PORT
      LAYER M5 ;
        RECT  63.936 128.233 63.96 128.317 ;
    END
  END wq[485]
  PIN wq[486]
    DIRECTION INPUT ;
    USE SIGNAL ;
    PORT
      LAYER M4 ;
        RECT  128.233 67.584 128.317 67.608 ;
    END
  END wq[486]
  PIN wq[487]
    DIRECTION INPUT ;
    USE SIGNAL ;
    PORT
      LAYER M4 ;
        RECT  128.233 70.464 128.317 70.488 ;
    END
  END wq[487]
  PIN wq[488]
    DIRECTION INPUT ;
    USE SIGNAL ;
    PORT
      LAYER M4 ;
        RECT  0 69.216 0.084 69.24 ;
    END
  END wq[488]
  PIN wq[489]
    DIRECTION INPUT ;
    USE SIGNAL ;
    PORT
      LAYER M4 ;
        RECT  0 68.832 0.084 68.856 ;
    END
  END wq[489]
  PIN wq[48]
    DIRECTION INPUT ;
    USE SIGNAL ;
    PORT
      LAYER M4 ;
        RECT  0 20.832 0.084 20.856 ;
    END
  END wq[48]
  PIN wq[490]
    DIRECTION INPUT ;
    USE SIGNAL ;
    PORT
      LAYER M4 ;
        RECT  0 69.312 0.084 69.336 ;
    END
  END wq[490]
  PIN wq[491]
    DIRECTION INPUT ;
    USE SIGNAL ;
    PORT
      LAYER M5 ;
        RECT  55.776 128.233 55.8 128.317 ;
    END
  END wq[491]
  PIN wq[492]
    DIRECTION INPUT ;
    USE SIGNAL ;
    PORT
      LAYER M5 ;
        RECT  55.968 128.233 55.992 128.317 ;
    END
  END wq[492]
  PIN wq[493]
    DIRECTION INPUT ;
    USE SIGNAL ;
    PORT
      LAYER M5 ;
        RECT  56.352 128.233 56.376 128.317 ;
    END
  END wq[493]
  PIN wq[494]
    DIRECTION INPUT ;
    USE SIGNAL ;
    PORT
      LAYER M5 ;
        RECT  56.16 128.233 56.184 128.317 ;
    END
  END wq[494]
  PIN wq[495]
    DIRECTION INPUT ;
    USE SIGNAL ;
    PORT
      LAYER M5 ;
        RECT  55.872 128.233 55.896 128.317 ;
    END
  END wq[495]
  PIN wq[496]
    DIRECTION INPUT ;
    USE SIGNAL ;
    PORT
      LAYER M4 ;
        RECT  0 69.12 0.084 69.144 ;
    END
  END wq[496]
  PIN wq[497]
    DIRECTION INPUT ;
    USE SIGNAL ;
    PORT
      LAYER M4 ;
        RECT  0 69.024 0.084 69.048 ;
    END
  END wq[497]
  PIN wq[498]
    DIRECTION INPUT ;
    USE SIGNAL ;
    PORT
      LAYER M4 ;
        RECT  0 69.408 0.084 69.432 ;
    END
  END wq[498]
  PIN wq[499]
    DIRECTION INPUT ;
    USE SIGNAL ;
    PORT
      LAYER M4 ;
        RECT  0 71.52 0.084 71.544 ;
    END
  END wq[499]
  PIN wq[49]
    DIRECTION INPUT ;
    USE SIGNAL ;
    PORT
      LAYER M4 ;
        RECT  0 20.736 0.084 20.76 ;
    END
  END wq[49]
  PIN wq[4]
    DIRECTION INPUT ;
    USE SIGNAL ;
    PORT
      LAYER M5 ;
        RECT  62.976 0 63 0.084 ;
    END
  END wq[4]
  PIN wq[500]
    DIRECTION INPUT ;
    USE SIGNAL ;
    PORT
      LAYER M4 ;
        RECT  0 69.792 0.084 69.816 ;
    END
  END wq[500]
  PIN wq[501]
    DIRECTION INPUT ;
    USE SIGNAL ;
    PORT
      LAYER M4 ;
        RECT  0 69.6 0.084 69.624 ;
    END
  END wq[501]
  PIN wq[502]
    DIRECTION INPUT ;
    USE SIGNAL ;
    PORT
      LAYER M4 ;
        RECT  0 69.888 0.084 69.912 ;
    END
  END wq[502]
  PIN wq[503]
    DIRECTION INPUT ;
    USE SIGNAL ;
    PORT
      LAYER M4 ;
        RECT  0 71.616 0.084 71.64 ;
    END
  END wq[503]
  PIN wq[504]
    DIRECTION INPUT ;
    USE SIGNAL ;
    PORT
      LAYER M4 ;
        RECT  0 76.224 0.084 76.248 ;
    END
  END wq[504]
  PIN wq[505]
    DIRECTION INPUT ;
    USE SIGNAL ;
    PORT
      LAYER M4 ;
        RECT  0 75.744 0.084 75.768 ;
    END
  END wq[505]
  PIN wq[506]
    DIRECTION INPUT ;
    USE SIGNAL ;
    PORT
      LAYER M4 ;
        RECT  0 75.456 0.084 75.48 ;
    END
  END wq[506]
  PIN wq[507]
    DIRECTION INPUT ;
    USE SIGNAL ;
    PORT
      LAYER M4 ;
        RECT  0 76.128 0.084 76.152 ;
    END
  END wq[507]
  PIN wq[508]
    DIRECTION INPUT ;
    USE SIGNAL ;
    PORT
      LAYER M4 ;
        RECT  0 75.264 0.084 75.288 ;
    END
  END wq[508]
  PIN wq[509]
    DIRECTION INPUT ;
    USE SIGNAL ;
    PORT
      LAYER M4 ;
        RECT  0 75.168 0.084 75.192 ;
    END
  END wq[509]
  PIN wq[50]
    DIRECTION INPUT ;
    USE SIGNAL ;
    PORT
      LAYER M4 ;
        RECT  0 21.024 0.084 21.048 ;
    END
  END wq[50]
  PIN wq[510]
    DIRECTION INPUT ;
    USE SIGNAL ;
    PORT
      LAYER M4 ;
        RECT  0 75.552 0.084 75.576 ;
    END
  END wq[510]
  PIN wq[511]
    DIRECTION INPUT ;
    USE SIGNAL ;
    PORT
      LAYER M4 ;
        RECT  0 80.928 0.084 80.952 ;
    END
  END wq[511]
  PIN wq[51]
    DIRECTION INPUT ;
    USE SIGNAL ;
    PORT
      LAYER M4 ;
        RECT  0 20.448 0.084 20.472 ;
    END
  END wq[51]
  PIN wq[52]
    DIRECTION INPUT ;
    USE SIGNAL ;
    PORT
      LAYER M4 ;
        RECT  0 21.408 0.084 21.432 ;
    END
  END wq[52]
  PIN wq[53]
    DIRECTION INPUT ;
    USE SIGNAL ;
    PORT
      LAYER M4 ;
        RECT  0 21.6 0.084 21.624 ;
    END
  END wq[53]
  PIN wq[54]
    DIRECTION INPUT ;
    USE SIGNAL ;
    PORT
      LAYER M4 ;
        RECT  0 21.312 0.084 21.336 ;
    END
  END wq[54]
  PIN wq[55]
    DIRECTION INPUT ;
    USE SIGNAL ;
    PORT
      LAYER M4 ;
        RECT  0 19.872 0.084 19.896 ;
    END
  END wq[55]
  PIN wq[56]
    DIRECTION INPUT ;
    USE SIGNAL ;
    PORT
      LAYER M5 ;
        RECT  23.424 0 23.448 0.084 ;
    END
  END wq[56]
  PIN wq[57]
    DIRECTION INPUT ;
    USE SIGNAL ;
    PORT
      LAYER M5 ;
        RECT  23.328 0 23.352 0.084 ;
    END
  END wq[57]
  PIN wq[58]
    DIRECTION INPUT ;
    USE SIGNAL ;
    PORT
      LAYER M5 ;
        RECT  23.52 0 23.544 0.084 ;
    END
  END wq[58]
  PIN wq[59]
    DIRECTION INPUT ;
    USE SIGNAL ;
    PORT
      LAYER M5 ;
        RECT  23.04 0 23.064 0.084 ;
    END
  END wq[59]
  PIN wq[5]
    DIRECTION INPUT ;
    USE SIGNAL ;
    PORT
      LAYER M5 ;
        RECT  62.784 0 62.808 0.084 ;
    END
  END wq[5]
  PIN wq[60]
    DIRECTION INPUT ;
    USE SIGNAL ;
    PORT
      LAYER M5 ;
        RECT  23.616 0 23.64 0.084 ;
    END
  END wq[60]
  PIN wq[61]
    DIRECTION INPUT ;
    USE SIGNAL ;
    PORT
      LAYER M5 ;
        RECT  23.808 0 23.832 0.084 ;
    END
  END wq[61]
  PIN wq[62]
    DIRECTION INPUT ;
    USE SIGNAL ;
    PORT
      LAYER M5 ;
        RECT  24.096 0 24.12 0.084 ;
    END
  END wq[62]
  PIN wq[63]
    DIRECTION INPUT ;
    USE SIGNAL ;
    PORT
      LAYER M5 ;
        RECT  22.944 0 22.968 0.084 ;
    END
  END wq[63]
  PIN wq[64]
    DIRECTION INPUT ;
    USE SIGNAL ;
    PORT
      LAYER M5 ;
        RECT  15.648 0 15.672 0.084 ;
    END
  END wq[64]
  PIN wq[65]
    DIRECTION INPUT ;
    USE SIGNAL ;
    PORT
      LAYER M5 ;
        RECT  15.744 0 15.768 0.084 ;
    END
  END wq[65]
  PIN wq[66]
    DIRECTION INPUT ;
    USE SIGNAL ;
    PORT
      LAYER M5 ;
        RECT  15.84 0 15.864 0.084 ;
    END
  END wq[66]
  PIN wq[67]
    DIRECTION INPUT ;
    USE SIGNAL ;
    PORT
      LAYER M5 ;
        RECT  15.936 0 15.96 0.084 ;
    END
  END wq[67]
  PIN wq[68]
    DIRECTION INPUT ;
    USE SIGNAL ;
    PORT
      LAYER M5 ;
        RECT  16.608 0 16.632 0.084 ;
    END
  END wq[68]
  PIN wq[69]
    DIRECTION INPUT ;
    USE SIGNAL ;
    PORT
      LAYER M5 ;
        RECT  16.416 0 16.44 0.084 ;
    END
  END wq[69]
  PIN wq[6]
    DIRECTION INPUT ;
    USE SIGNAL ;
    PORT
      LAYER M5 ;
        RECT  63.264 0 63.288 0.084 ;
    END
  END wq[6]
  PIN wq[70]
    DIRECTION INPUT ;
    USE SIGNAL ;
    PORT
      LAYER M5 ;
        RECT  16.224 0 16.248 0.084 ;
    END
  END wq[70]
  PIN wq[71]
    DIRECTION INPUT ;
    USE SIGNAL ;
    PORT
      LAYER M5 ;
        RECT  16.032 0 16.056 0.084 ;
    END
  END wq[71]
  PIN wq[72]
    DIRECTION INPUT ;
    USE SIGNAL ;
    PORT
      LAYER M5 ;
        RECT  13.344 0 13.368 0.084 ;
    END
  END wq[72]
  PIN wq[73]
    DIRECTION INPUT ;
    USE SIGNAL ;
    PORT
      LAYER M5 ;
        RECT  13.92 0 13.944 0.084 ;
    END
  END wq[73]
  PIN wq[74]
    DIRECTION INPUT ;
    USE SIGNAL ;
    PORT
      LAYER M5 ;
        RECT  13.44 0 13.464 0.084 ;
    END
  END wq[74]
  PIN wq[75]
    DIRECTION INPUT ;
    USE SIGNAL ;
    PORT
      LAYER M5 ;
        RECT  12 0 12.024 0.084 ;
    END
  END wq[75]
  PIN wq[76]
    DIRECTION INPUT ;
    USE SIGNAL ;
    PORT
      LAYER M5 ;
        RECT  14.112 0 14.136 0.084 ;
    END
  END wq[76]
  PIN wq[77]
    DIRECTION INPUT ;
    USE SIGNAL ;
    PORT
      LAYER M5 ;
        RECT  14.208 0 14.232 0.084 ;
    END
  END wq[77]
  PIN wq[78]
    DIRECTION INPUT ;
    USE SIGNAL ;
    PORT
      LAYER M5 ;
        RECT  13.248 0 13.272 0.084 ;
    END
  END wq[78]
  PIN wq[79]
    DIRECTION INPUT ;
    USE SIGNAL ;
    PORT
      LAYER M5 ;
        RECT  11.52 0 11.544 0.084 ;
    END
  END wq[79]
  PIN wq[7]
    DIRECTION INPUT ;
    USE SIGNAL ;
    PORT
      LAYER M5 ;
        RECT  65.28 0 65.304 0.084 ;
    END
  END wq[7]
  PIN wq[80]
    DIRECTION INPUT ;
    USE SIGNAL ;
    PORT
      LAYER M4 ;
        RECT  0 35.136 0.084 35.16 ;
    END
  END wq[80]
  PIN wq[81]
    DIRECTION INPUT ;
    USE SIGNAL ;
    PORT
      LAYER M4 ;
        RECT  0 35.04 0.084 35.064 ;
    END
  END wq[81]
  PIN wq[82]
    DIRECTION INPUT ;
    USE SIGNAL ;
    PORT
      LAYER M4 ;
        RECT  0 35.424 0.084 35.448 ;
    END
  END wq[82]
  PIN wq[83]
    DIRECTION INPUT ;
    USE SIGNAL ;
    PORT
      LAYER M4 ;
        RECT  0 34.56 0.084 34.584 ;
    END
  END wq[83]
  PIN wq[84]
    DIRECTION INPUT ;
    USE SIGNAL ;
    PORT
      LAYER M4 ;
        RECT  0 34.656 0.084 34.68 ;
    END
  END wq[84]
  PIN wq[85]
    DIRECTION INPUT ;
    USE SIGNAL ;
    PORT
      LAYER M4 ;
        RECT  0 35.328 0.084 35.352 ;
    END
  END wq[85]
  PIN wq[86]
    DIRECTION INPUT ;
    USE SIGNAL ;
    PORT
      LAYER M4 ;
        RECT  0 35.232 0.084 35.256 ;
    END
  END wq[86]
  PIN wq[87]
    DIRECTION INPUT ;
    USE SIGNAL ;
    PORT
      LAYER M4 ;
        RECT  0 34.944 0.084 34.968 ;
    END
  END wq[87]
  PIN wq[88]
    DIRECTION INPUT ;
    USE SIGNAL ;
    PORT
      LAYER M4 ;
        RECT  0 26.592 0.084 26.616 ;
    END
  END wq[88]
  PIN wq[89]
    DIRECTION INPUT ;
    USE SIGNAL ;
    PORT
      LAYER M4 ;
        RECT  0 26.688 0.084 26.712 ;
    END
  END wq[89]
  PIN wq[8]
    DIRECTION INPUT ;
    USE SIGNAL ;
    PORT
      LAYER M5 ;
        RECT  63.168 0 63.192 0.084 ;
    END
  END wq[8]
  PIN wq[90]
    DIRECTION INPUT ;
    USE SIGNAL ;
    PORT
      LAYER M4 ;
        RECT  0 26.784 0.084 26.808 ;
    END
  END wq[90]
  PIN wq[91]
    DIRECTION INPUT ;
    USE SIGNAL ;
    PORT
      LAYER M4 ;
        RECT  0 26.112 0.084 26.136 ;
    END
  END wq[91]
  PIN wq[92]
    DIRECTION INPUT ;
    USE SIGNAL ;
    PORT
      LAYER M4 ;
        RECT  0 26.496 0.084 26.52 ;
    END
  END wq[92]
  PIN wq[93]
    DIRECTION INPUT ;
    USE SIGNAL ;
    PORT
      LAYER M4 ;
        RECT  0 26.88 0.084 26.904 ;
    END
  END wq[93]
  PIN wq[94]
    DIRECTION INPUT ;
    USE SIGNAL ;
    PORT
      LAYER M4 ;
        RECT  0 27.264 0.084 27.288 ;
    END
  END wq[94]
  PIN wq[95]
    DIRECTION INPUT ;
    USE SIGNAL ;
    PORT
      LAYER M4 ;
        RECT  0 25.536 0.084 25.56 ;
    END
  END wq[95]
  PIN wq[96]
    DIRECTION INPUT ;
    USE SIGNAL ;
    PORT
      LAYER M4 ;
        RECT  0 43.296 0.084 43.32 ;
    END
  END wq[96]
  PIN wq[97]
    DIRECTION INPUT ;
    USE SIGNAL ;
    PORT
      LAYER M4 ;
        RECT  0 43.584 0.084 43.608 ;
    END
  END wq[97]
  PIN wq[98]
    DIRECTION INPUT ;
    USE SIGNAL ;
    PORT
      LAYER M4 ;
        RECT  0 43.488 0.084 43.512 ;
    END
  END wq[98]
  PIN wq[99]
    DIRECTION INPUT ;
    USE SIGNAL ;
    PORT
      LAYER M4 ;
        RECT  0 44.448 0.084 44.472 ;
    END
  END wq[99]
  PIN wq[9]
    DIRECTION INPUT ;
    USE SIGNAL ;
    PORT
      LAYER M5 ;
        RECT  63.456 0 63.48 0.084 ;
    END
  END wq[9]
  PIN xe[0]
    DIRECTION INPUT ;
    USE SIGNAL ;
    PORT
      LAYER M5 ;
        RECT  70.176 0 70.2 0.084 ;
    END
  END xe[0]
  PIN xe[10]
    DIRECTION INPUT ;
    USE SIGNAL ;
    PORT
      LAYER M4 ;
        RECT  128.233 69.312 128.317 69.336 ;
    END
  END xe[10]
  PIN xe[11]
    DIRECTION INPUT ;
    USE SIGNAL ;
    PORT
      LAYER M4 ;
        RECT  128.233 68.064 128.317 68.088 ;
    END
  END xe[11]
  PIN xe[12]
    DIRECTION INPUT ;
    USE SIGNAL ;
    PORT
      LAYER M4 ;
        RECT  128.233 67.392 128.317 67.416 ;
    END
  END xe[12]
  PIN xe[13]
    DIRECTION INPUT ;
    USE SIGNAL ;
    PORT
      LAYER M4 ;
        RECT  128.233 66.336 128.317 66.36 ;
    END
  END xe[13]
  PIN xe[14]
    DIRECTION INPUT ;
    USE SIGNAL ;
    PORT
      LAYER M4 ;
        RECT  128.233 65.568 128.317 65.592 ;
    END
  END xe[14]
  PIN xe[15]
    DIRECTION INPUT ;
    USE SIGNAL ;
    PORT
      LAYER M4 ;
        RECT  128.233 64.512 128.317 64.536 ;
    END
  END xe[15]
  PIN xe[16]
    DIRECTION INPUT ;
    USE SIGNAL ;
    PORT
      LAYER M4 ;
        RECT  128.233 64.128 128.317 64.152 ;
    END
  END xe[16]
  PIN xe[17]
    DIRECTION INPUT ;
    USE SIGNAL ;
    PORT
      LAYER M4 ;
        RECT  128.233 62.304 128.317 62.328 ;
    END
  END xe[17]
  PIN xe[18]
    DIRECTION INPUT ;
    USE SIGNAL ;
    PORT
      LAYER M4 ;
        RECT  128.233 62.4 128.317 62.424 ;
    END
  END xe[18]
  PIN xe[19]
    DIRECTION INPUT ;
    USE SIGNAL ;
    PORT
      LAYER M4 ;
        RECT  128.233 63.456 128.317 63.48 ;
    END
  END xe[19]
  PIN xe[1]
    DIRECTION INPUT ;
    USE SIGNAL ;
    PORT
      LAYER M5 ;
        RECT  69.216 0 69.24 0.084 ;
    END
  END xe[1]
  PIN xe[2]
    DIRECTION INPUT ;
    USE SIGNAL ;
    PORT
      LAYER M5 ;
        RECT  68.16 0 68.184 0.084 ;
    END
  END xe[2]
  PIN xe[3]
    DIRECTION INPUT ;
    USE SIGNAL ;
    PORT
      LAYER M5 ;
        RECT  68.736 0 68.76 0.084 ;
    END
  END xe[3]
  PIN xe[4]
    DIRECTION INPUT ;
    USE SIGNAL ;
    PORT
      LAYER M5 ;
        RECT  67.488 0 67.512 0.084 ;
    END
  END xe[4]
  PIN xe[5]
    DIRECTION INPUT ;
    USE SIGNAL ;
    PORT
      LAYER M5 ;
        RECT  67.296 0 67.32 0.084 ;
    END
  END xe[5]
  PIN xe[6]
    DIRECTION INPUT ;
    USE SIGNAL ;
    PORT
      LAYER M5 ;
        RECT  68.448 0 68.472 0.084 ;
    END
  END xe[6]
  PIN xe[7]
    DIRECTION INPUT ;
    USE SIGNAL ;
    PORT
      LAYER M5 ;
        RECT  66.72 0 66.744 0.084 ;
    END
  END xe[7]
  PIN xe[8]
    DIRECTION INPUT ;
    USE SIGNAL ;
    PORT
      LAYER M5 ;
        RECT  64.896 0 64.92 0.084 ;
    END
  END xe[8]
  PIN xe[9]
    DIRECTION INPUT ;
    USE SIGNAL ;
    PORT
      LAYER M5 ;
        RECT  65.184 0 65.208 0.084 ;
    END
  END xe[9]
  PIN xq[0]
    DIRECTION INPUT ;
    USE SIGNAL ;
    PORT
      LAYER M5 ;
        RECT  66.048 0 66.072 0.084 ;
    END
  END xq[0]
  PIN xq[100]
    DIRECTION INPUT ;
    USE SIGNAL ;
    PORT
      LAYER M4 ;
        RECT  0 43.104 0.084 43.128 ;
    END
  END xq[100]
  PIN xq[101]
    DIRECTION INPUT ;
    USE SIGNAL ;
    PORT
      LAYER M4 ;
        RECT  0 42.72 0.084 42.744 ;
    END
  END xq[101]
  PIN xq[102]
    DIRECTION INPUT ;
    USE SIGNAL ;
    PORT
      LAYER M4 ;
        RECT  0 42.528 0.084 42.552 ;
    END
  END xq[102]
  PIN xq[103]
    DIRECTION INPUT ;
    USE SIGNAL ;
    PORT
      LAYER M4 ;
        RECT  0 44.256 0.084 44.28 ;
    END
  END xq[103]
  PIN xq[104]
    DIRECTION INPUT ;
    USE SIGNAL ;
    PORT
      LAYER M4 ;
        RECT  0 50.784 0.084 50.808 ;
    END
  END xq[104]
  PIN xq[105]
    DIRECTION INPUT ;
    USE SIGNAL ;
    PORT
      LAYER M4 ;
        RECT  0 51.072 0.084 51.096 ;
    END
  END xq[105]
  PIN xq[106]
    DIRECTION INPUT ;
    USE SIGNAL ;
    PORT
      LAYER M4 ;
        RECT  0 49.92 0.084 49.944 ;
    END
  END xq[106]
  PIN xq[107]
    DIRECTION INPUT ;
    USE SIGNAL ;
    PORT
      LAYER M4 ;
        RECT  0 48.96 0.084 48.984 ;
    END
  END xq[107]
  PIN xq[108]
    DIRECTION INPUT ;
    USE SIGNAL ;
    PORT
      LAYER M4 ;
        RECT  0 50.4 0.084 50.424 ;
    END
  END xq[108]
  PIN xq[109]
    DIRECTION INPUT ;
    USE SIGNAL ;
    PORT
      LAYER M4 ;
        RECT  0 47.808 0.084 47.832 ;
    END
  END xq[109]
  PIN xq[10]
    DIRECTION INPUT ;
    USE SIGNAL ;
    PORT
      LAYER M5 ;
        RECT  62.208 0 62.232 0.084 ;
    END
  END xq[10]
  PIN xq[110]
    DIRECTION INPUT ;
    USE SIGNAL ;
    PORT
      LAYER M4 ;
        RECT  0 49.728 0.084 49.752 ;
    END
  END xq[110]
  PIN xq[111]
    DIRECTION INPUT ;
    USE SIGNAL ;
    PORT
      LAYER M4 ;
        RECT  0 51.84 0.084 51.864 ;
    END
  END xq[111]
  PIN xq[112]
    DIRECTION INPUT ;
    USE SIGNAL ;
    PORT
      LAYER M4 ;
        RECT  0 55.2 0.084 55.224 ;
    END
  END xq[112]
  PIN xq[113]
    DIRECTION INPUT ;
    USE SIGNAL ;
    PORT
      LAYER M4 ;
        RECT  0 55.008 0.084 55.032 ;
    END
  END xq[113]
  PIN xq[114]
    DIRECTION INPUT ;
    USE SIGNAL ;
    PORT
      LAYER M4 ;
        RECT  0 55.296 0.084 55.32 ;
    END
  END xq[114]
  PIN xq[115]
    DIRECTION INPUT ;
    USE SIGNAL ;
    PORT
      LAYER M4 ;
        RECT  0 54.528 0.084 54.552 ;
    END
  END xq[115]
  PIN xq[116]
    DIRECTION INPUT ;
    USE SIGNAL ;
    PORT
      LAYER M4 ;
        RECT  0 57.12 0.084 57.144 ;
    END
  END xq[116]
  PIN xq[117]
    DIRECTION INPUT ;
    USE SIGNAL ;
    PORT
      LAYER M4 ;
        RECT  0 56.16 0.084 56.184 ;
    END
  END xq[117]
  PIN xq[118]
    DIRECTION INPUT ;
    USE SIGNAL ;
    PORT
      LAYER M4 ;
        RECT  0 57.504 0.084 57.528 ;
    END
  END xq[118]
  PIN xq[119]
    DIRECTION INPUT ;
    USE SIGNAL ;
    PORT
      LAYER M4 ;
        RECT  0 54.048 0.084 54.072 ;
    END
  END xq[119]
  PIN xq[11]
    DIRECTION INPUT ;
    USE SIGNAL ;
    PORT
      LAYER M5 ;
        RECT  59.232 0 59.256 0.084 ;
    END
  END xq[11]
  PIN xq[120]
    DIRECTION INPUT ;
    USE SIGNAL ;
    PORT
      LAYER M4 ;
        RECT  0 52.896 0.084 52.92 ;
    END
  END xq[120]
  PIN xq[121]
    DIRECTION INPUT ;
    USE SIGNAL ;
    PORT
      LAYER M4 ;
        RECT  0 51.168 0.084 51.192 ;
    END
  END xq[121]
  PIN xq[122]
    DIRECTION INPUT ;
    USE SIGNAL ;
    PORT
      LAYER M4 ;
        RECT  0 53.184 0.084 53.208 ;
    END
  END xq[122]
  PIN xq[123]
    DIRECTION INPUT ;
    USE SIGNAL ;
    PORT
      LAYER M4 ;
        RECT  0 47.904 0.084 47.928 ;
    END
  END xq[123]
  PIN xq[124]
    DIRECTION INPUT ;
    USE SIGNAL ;
    PORT
      LAYER M4 ;
        RECT  0 46.944 0.084 46.968 ;
    END
  END xq[124]
  PIN xq[125]
    DIRECTION INPUT ;
    USE SIGNAL ;
    PORT
      LAYER M4 ;
        RECT  0 46.08 0.084 46.104 ;
    END
  END xq[125]
  PIN xq[126]
    DIRECTION INPUT ;
    USE SIGNAL ;
    PORT
      LAYER M4 ;
        RECT  0 46.752 0.084 46.776 ;
    END
  END xq[126]
  PIN xq[127]
    DIRECTION INPUT ;
    USE SIGNAL ;
    PORT
      LAYER M4 ;
        RECT  0 49.152 0.084 49.176 ;
    END
  END xq[127]
  PIN xq[128]
    DIRECTION INPUT ;
    USE SIGNAL ;
    PORT
      LAYER M4 ;
        RECT  0 56.928 0.084 56.952 ;
    END
  END xq[128]
  PIN xq[129]
    DIRECTION INPUT ;
    USE SIGNAL ;
    PORT
      LAYER M4 ;
        RECT  0 55.392 0.084 55.416 ;
    END
  END xq[129]
  PIN xq[12]
    DIRECTION INPUT ;
    USE SIGNAL ;
    PORT
      LAYER M5 ;
        RECT  57.888 0 57.912 0.084 ;
    END
  END xq[12]
  PIN xq[130]
    DIRECTION INPUT ;
    USE SIGNAL ;
    PORT
      LAYER M4 ;
        RECT  0 53.952 0.084 53.976 ;
    END
  END xq[130]
  PIN xq[131]
    DIRECTION INPUT ;
    USE SIGNAL ;
    PORT
      LAYER M4 ;
        RECT  0 55.776 0.084 55.8 ;
    END
  END xq[131]
  PIN xq[132]
    DIRECTION INPUT ;
    USE SIGNAL ;
    PORT
      LAYER M4 ;
        RECT  0 59.616 0.084 59.64 ;
    END
  END xq[132]
  PIN xq[133]
    DIRECTION INPUT ;
    USE SIGNAL ;
    PORT
      LAYER M4 ;
        RECT  0 58.56 0.084 58.584 ;
    END
  END xq[133]
  PIN xq[134]
    DIRECTION INPUT ;
    USE SIGNAL ;
    PORT
      LAYER M4 ;
        RECT  0 58.272 0.084 58.296 ;
    END
  END xq[134]
  PIN xq[135]
    DIRECTION INPUT ;
    USE SIGNAL ;
    PORT
      LAYER M4 ;
        RECT  0 59.712 0.084 59.736 ;
    END
  END xq[135]
  PIN xq[136]
    DIRECTION INPUT ;
    USE SIGNAL ;
    PORT
      LAYER M4 ;
        RECT  0 61.152 0.084 61.176 ;
    END
  END xq[136]
  PIN xq[137]
    DIRECTION INPUT ;
    USE SIGNAL ;
    PORT
      LAYER M4 ;
        RECT  0 60.672 0.084 60.696 ;
    END
  END xq[137]
  PIN xq[138]
    DIRECTION INPUT ;
    USE SIGNAL ;
    PORT
      LAYER M4 ;
        RECT  0 53.472 0.084 53.496 ;
    END
  END xq[138]
  PIN xq[139]
    DIRECTION INPUT ;
    USE SIGNAL ;
    PORT
      LAYER M4 ;
        RECT  0 56.448 0.084 56.472 ;
    END
  END xq[139]
  PIN xq[13]
    DIRECTION INPUT ;
    USE SIGNAL ;
    PORT
      LAYER M5 ;
        RECT  58.56 0 58.584 0.084 ;
    END
  END xq[13]
  PIN xq[140]
    DIRECTION INPUT ;
    USE SIGNAL ;
    PORT
      LAYER M4 ;
        RECT  0 54.72 0.084 54.744 ;
    END
  END xq[140]
  PIN xq[141]
    DIRECTION INPUT ;
    USE SIGNAL ;
    PORT
      LAYER M4 ;
        RECT  0 55.488 0.084 55.512 ;
    END
  END xq[141]
  PIN xq[142]
    DIRECTION INPUT ;
    USE SIGNAL ;
    PORT
      LAYER M4 ;
        RECT  0 55.104 0.084 55.128 ;
    END
  END xq[142]
  PIN xq[143]
    DIRECTION INPUT ;
    USE SIGNAL ;
    PORT
      LAYER M4 ;
        RECT  0 61.344 0.084 61.368 ;
    END
  END xq[143]
  PIN xq[144]
    DIRECTION INPUT ;
    USE SIGNAL ;
    PORT
      LAYER M4 ;
        RECT  0 64.032 0.084 64.056 ;
    END
  END xq[144]
  PIN xq[145]
    DIRECTION INPUT ;
    USE SIGNAL ;
    PORT
      LAYER M4 ;
        RECT  0 62.88 0.084 62.904 ;
    END
  END xq[145]
  PIN xq[146]
    DIRECTION INPUT ;
    USE SIGNAL ;
    PORT
      LAYER M4 ;
        RECT  0 61.056 0.084 61.08 ;
    END
  END xq[146]
  PIN xq[147]
    DIRECTION INPUT ;
    USE SIGNAL ;
    PORT
      LAYER M4 ;
        RECT  0 54.24 0.084 54.264 ;
    END
  END xq[147]
  PIN xq[148]
    DIRECTION INPUT ;
    USE SIGNAL ;
    PORT
      LAYER M4 ;
        RECT  0 55.68 0.084 55.704 ;
    END
  END xq[148]
  PIN xq[149]
    DIRECTION INPUT ;
    USE SIGNAL ;
    PORT
      LAYER M4 ;
        RECT  0 55.872 0.084 55.896 ;
    END
  END xq[149]
  PIN xq[14]
    DIRECTION INPUT ;
    USE SIGNAL ;
    PORT
      LAYER M5 ;
        RECT  58.464 0 58.488 0.084 ;
    END
  END xq[14]
  PIN xq[150]
    DIRECTION INPUT ;
    USE SIGNAL ;
    PORT
      LAYER M4 ;
        RECT  0 57.216 0.084 57.24 ;
    END
  END xq[150]
  PIN xq[151]
    DIRECTION INPUT ;
    USE SIGNAL ;
    PORT
      LAYER M4 ;
        RECT  0 60.096 0.084 60.12 ;
    END
  END xq[151]
  PIN xq[152]
    DIRECTION INPUT ;
    USE SIGNAL ;
    PORT
      LAYER M4 ;
        RECT  0 55.968 0.084 55.992 ;
    END
  END xq[152]
  PIN xq[153]
    DIRECTION INPUT ;
    USE SIGNAL ;
    PORT
      LAYER M4 ;
        RECT  0 55.584 0.084 55.608 ;
    END
  END xq[153]
  PIN xq[154]
    DIRECTION INPUT ;
    USE SIGNAL ;
    PORT
      LAYER M4 ;
        RECT  0 54.144 0.084 54.168 ;
    END
  END xq[154]
  PIN xq[155]
    DIRECTION INPUT ;
    USE SIGNAL ;
    PORT
      LAYER M4 ;
        RECT  0 51.264 0.084 51.288 ;
    END
  END xq[155]
  PIN xq[156]
    DIRECTION INPUT ;
    USE SIGNAL ;
    PORT
      LAYER M4 ;
        RECT  0 49.632 0.084 49.656 ;
    END
  END xq[156]
  PIN xq[157]
    DIRECTION INPUT ;
    USE SIGNAL ;
    PORT
      LAYER M4 ;
        RECT  0 48.576 0.084 48.6 ;
    END
  END xq[157]
  PIN xq[158]
    DIRECTION INPUT ;
    USE SIGNAL ;
    PORT
      LAYER M4 ;
        RECT  0 50.304 0.084 50.328 ;
    END
  END xq[158]
  PIN xq[159]
    DIRECTION INPUT ;
    USE SIGNAL ;
    PORT
      LAYER M4 ;
        RECT  0 56.64 0.084 56.664 ;
    END
  END xq[159]
  PIN xq[15]
    DIRECTION INPUT ;
    USE SIGNAL ;
    PORT
      LAYER M5 ;
        RECT  64.704 0 64.728 0.084 ;
    END
  END xq[15]
  PIN xq[160]
    DIRECTION INPUT ;
    USE SIGNAL ;
    PORT
      LAYER M4 ;
        RECT  0 64.512 0.084 64.536 ;
    END
  END xq[160]
  PIN xq[161]
    DIRECTION INPUT ;
    USE SIGNAL ;
    PORT
      LAYER M4 ;
        RECT  0 61.824 0.084 61.848 ;
    END
  END xq[161]
  PIN xq[162]
    DIRECTION INPUT ;
    USE SIGNAL ;
    PORT
      LAYER M4 ;
        RECT  0 62.208 0.084 62.232 ;
    END
  END xq[162]
  PIN xq[163]
    DIRECTION INPUT ;
    USE SIGNAL ;
    PORT
      LAYER M4 ;
        RECT  0 59.904 0.084 59.928 ;
    END
  END xq[163]
  PIN xq[164]
    DIRECTION INPUT ;
    USE SIGNAL ;
    PORT
      LAYER M4 ;
        RECT  0 58.944 0.084 58.968 ;
    END
  END xq[164]
  PIN xq[165]
    DIRECTION INPUT ;
    USE SIGNAL ;
    PORT
      LAYER M4 ;
        RECT  0 54.336 0.084 54.36 ;
    END
  END xq[165]
  PIN xq[166]
    DIRECTION INPUT ;
    USE SIGNAL ;
    PORT
      LAYER M4 ;
        RECT  0 57.024 0.084 57.048 ;
    END
  END xq[166]
  PIN xq[167]
    DIRECTION INPUT ;
    USE SIGNAL ;
    PORT
      LAYER M4 ;
        RECT  0 65.088 0.084 65.112 ;
    END
  END xq[167]
  PIN xq[168]
    DIRECTION INPUT ;
    USE SIGNAL ;
    PORT
      LAYER M4 ;
        RECT  0 65.376 0.084 65.4 ;
    END
  END xq[168]
  PIN xq[169]
    DIRECTION INPUT ;
    USE SIGNAL ;
    PORT
      LAYER M4 ;
        RECT  0 65.664 0.084 65.688 ;
    END
  END xq[169]
  PIN xq[16]
    DIRECTION INPUT ;
    USE SIGNAL ;
    PORT
      LAYER M5 ;
        RECT  56.928 0 56.952 0.084 ;
    END
  END xq[16]
  PIN xq[170]
    DIRECTION INPUT ;
    USE SIGNAL ;
    PORT
      LAYER M4 ;
        RECT  0 65.472 0.084 65.496 ;
    END
  END xq[170]
  PIN xq[171]
    DIRECTION INPUT ;
    USE SIGNAL ;
    PORT
      LAYER M4 ;
        RECT  0 58.656 0.084 58.68 ;
    END
  END xq[171]
  PIN xq[172]
    DIRECTION INPUT ;
    USE SIGNAL ;
    PORT
      LAYER M4 ;
        RECT  0 54.816 0.084 54.84 ;
    END
  END xq[172]
  PIN xq[173]
    DIRECTION INPUT ;
    USE SIGNAL ;
    PORT
      LAYER M4 ;
        RECT  0 54.432 0.084 54.456 ;
    END
  END xq[173]
  PIN xq[174]
    DIRECTION INPUT ;
    USE SIGNAL ;
    PORT
      LAYER M4 ;
        RECT  0 56.352 0.084 56.376 ;
    END
  END xq[174]
  PIN xq[175]
    DIRECTION INPUT ;
    USE SIGNAL ;
    PORT
      LAYER M4 ;
        RECT  0 53.376 0.084 53.4 ;
    END
  END xq[175]
  PIN xq[176]
    DIRECTION INPUT ;
    USE SIGNAL ;
    PORT
      LAYER M4 ;
        RECT  0 66.048 0.084 66.072 ;
    END
  END xq[176]
  PIN xq[177]
    DIRECTION INPUT ;
    USE SIGNAL ;
    PORT
      LAYER M4 ;
        RECT  0 65.184 0.084 65.208 ;
    END
  END xq[177]
  PIN xq[178]
    DIRECTION INPUT ;
    USE SIGNAL ;
    PORT
      LAYER M4 ;
        RECT  0 66.144 0.084 66.168 ;
    END
  END xq[178]
  PIN xq[179]
    DIRECTION INPUT ;
    USE SIGNAL ;
    PORT
      LAYER M4 ;
        RECT  0 62.016 0.084 62.04 ;
    END
  END xq[179]
  PIN xq[17]
    DIRECTION INPUT ;
    USE SIGNAL ;
    PORT
      LAYER M5 ;
        RECT  57.12 0 57.144 0.084 ;
    END
  END xq[17]
  PIN xq[180]
    DIRECTION INPUT ;
    USE SIGNAL ;
    PORT
      LAYER M4 ;
        RECT  0 61.44 0.084 61.464 ;
    END
  END xq[180]
  PIN xq[181]
    DIRECTION INPUT ;
    USE SIGNAL ;
    PORT
      LAYER M5 ;
        RECT  50.016 0 50.04 0.084 ;
    END
  END xq[181]
  PIN xq[182]
    DIRECTION INPUT ;
    USE SIGNAL ;
    PORT
      LAYER M5 ;
        RECT  49.92 0 49.944 0.084 ;
    END
  END xq[182]
  PIN xq[183]
    DIRECTION INPUT ;
    USE SIGNAL ;
    PORT
      LAYER M5 ;
        RECT  56.064 128.233 56.088 128.317 ;
    END
  END xq[183]
  PIN xq[184]
    DIRECTION INPUT ;
    USE SIGNAL ;
    PORT
      LAYER M5 ;
        RECT  57.888 128.233 57.912 128.317 ;
    END
  END xq[184]
  PIN xq[185]
    DIRECTION INPUT ;
    USE SIGNAL ;
    PORT
      LAYER M5 ;
        RECT  58.272 128.233 58.296 128.317 ;
    END
  END xq[185]
  PIN xq[186]
    DIRECTION INPUT ;
    USE SIGNAL ;
    PORT
      LAYER M5 ;
        RECT  57.216 128.233 57.24 128.317 ;
    END
  END xq[186]
  PIN xq[187]
    DIRECTION INPUT ;
    USE SIGNAL ;
    PORT
      LAYER M5 ;
        RECT  60.864 0 60.888 0.084 ;
    END
  END xq[187]
  PIN xq[188]
    DIRECTION INPUT ;
    USE SIGNAL ;
    PORT
      LAYER M5 ;
        RECT  62.304 0 62.328 0.084 ;
    END
  END xq[188]
  PIN xq[189]
    DIRECTION INPUT ;
    USE SIGNAL ;
    PORT
      LAYER M5 ;
        RECT  62.4 0 62.424 0.084 ;
    END
  END xq[189]
  PIN xq[18]
    DIRECTION INPUT ;
    USE SIGNAL ;
    PORT
      LAYER M5 ;
        RECT  54.432 0 54.456 0.084 ;
    END
  END xq[18]
  PIN xq[190]
    DIRECTION INPUT ;
    USE SIGNAL ;
    PORT
      LAYER M5 ;
        RECT  61.152 0 61.176 0.084 ;
    END
  END xq[190]
  PIN xq[191]
    DIRECTION INPUT ;
    USE SIGNAL ;
    PORT
      LAYER M5 ;
        RECT  61.824 0 61.848 0.084 ;
    END
  END xq[191]
  PIN xq[192]
    DIRECTION INPUT ;
    USE SIGNAL ;
    PORT
      LAYER M4 ;
        RECT  128.233 65.664 128.317 65.688 ;
    END
  END xq[192]
  PIN xq[193]
    DIRECTION INPUT ;
    USE SIGNAL ;
    PORT
      LAYER M4 ;
        RECT  128.233 65.472 128.317 65.496 ;
    END
  END xq[193]
  PIN xq[194]
    DIRECTION INPUT ;
    USE SIGNAL ;
    PORT
      LAYER M4 ;
        RECT  128.233 65.76 128.317 65.784 ;
    END
  END xq[194]
  PIN xq[195]
    DIRECTION INPUT ;
    USE SIGNAL ;
    PORT
      LAYER M5 ;
        RECT  63.744 0 63.768 0.084 ;
    END
  END xq[195]
  PIN xq[196]
    DIRECTION INPUT ;
    USE SIGNAL ;
    PORT
      LAYER M5 ;
        RECT  62.688 0 62.712 0.084 ;
    END
  END xq[196]
  PIN xq[197]
    DIRECTION INPUT ;
    USE SIGNAL ;
    PORT
      LAYER M5 ;
        RECT  63.072 0 63.096 0.084 ;
    END
  END xq[197]
  PIN xq[198]
    DIRECTION INPUT ;
    USE SIGNAL ;
    PORT
      LAYER M5 ;
        RECT  63.36 0 63.384 0.084 ;
    END
  END xq[198]
  PIN xq[199]
    DIRECTION INPUT ;
    USE SIGNAL ;
    PORT
      LAYER M4 ;
        RECT  128.233 62.112 128.317 62.136 ;
    END
  END xq[199]
  PIN xq[19]
    DIRECTION INPUT ;
    USE SIGNAL ;
    PORT
      LAYER M5 ;
        RECT  55.296 0 55.32 0.084 ;
    END
  END xq[19]
  PIN xq[1]
    DIRECTION INPUT ;
    USE SIGNAL ;
    PORT
      LAYER M5 ;
        RECT  67.872 0 67.896 0.084 ;
    END
  END xq[1]
  PIN xq[200]
    DIRECTION INPUT ;
    USE SIGNAL ;
    PORT
      LAYER M4 ;
        RECT  128.233 53.664 128.317 53.688 ;
    END
  END xq[200]
  PIN xq[201]
    DIRECTION INPUT ;
    USE SIGNAL ;
    PORT
      LAYER M4 ;
        RECT  128.233 55.2 128.317 55.224 ;
    END
  END xq[201]
  PIN xq[202]
    DIRECTION INPUT ;
    USE SIGNAL ;
    PORT
      LAYER M4 ;
        RECT  128.233 54.72 128.317 54.744 ;
    END
  END xq[202]
  PIN xq[203]
    DIRECTION INPUT ;
    USE SIGNAL ;
    PORT
      LAYER M4 ;
        RECT  128.233 54.144 128.317 54.168 ;
    END
  END xq[203]
  PIN xq[204]
    DIRECTION INPUT ;
    USE SIGNAL ;
    PORT
      LAYER M5 ;
        RECT  73.248 0 73.272 0.084 ;
    END
  END xq[204]
  PIN xq[205]
    DIRECTION INPUT ;
    USE SIGNAL ;
    PORT
      LAYER M5 ;
        RECT  73.632 0 73.656 0.084 ;
    END
  END xq[205]
  PIN xq[206]
    DIRECTION INPUT ;
    USE SIGNAL ;
    PORT
      LAYER M4 ;
        RECT  128.233 54.336 128.317 54.36 ;
    END
  END xq[206]
  PIN xq[207]
    DIRECTION INPUT ;
    USE SIGNAL ;
    PORT
      LAYER M4 ;
        RECT  128.233 55.296 128.317 55.32 ;
    END
  END xq[207]
  PIN xq[208]
    DIRECTION INPUT ;
    USE SIGNAL ;
    PORT
      LAYER M4 ;
        RECT  128.233 61.632 128.317 61.656 ;
    END
  END xq[208]
  PIN xq[209]
    DIRECTION INPUT ;
    USE SIGNAL ;
    PORT
      LAYER M4 ;
        RECT  128.233 61.92 128.317 61.944 ;
    END
  END xq[209]
  PIN xq[20]
    DIRECTION INPUT ;
    USE SIGNAL ;
    PORT
      LAYER M5 ;
        RECT  55.2 0 55.224 0.084 ;
    END
  END xq[20]
  PIN xq[210]
    DIRECTION INPUT ;
    USE SIGNAL ;
    PORT
      LAYER M4 ;
        RECT  128.233 60.192 128.317 60.216 ;
    END
  END xq[210]
  PIN xq[211]
    DIRECTION INPUT ;
    USE SIGNAL ;
    PORT
      LAYER M5 ;
        RECT  69.696 0 69.72 0.084 ;
    END
  END xq[211]
  PIN xq[212]
    DIRECTION INPUT ;
    USE SIGNAL ;
    PORT
      LAYER M5 ;
        RECT  68.064 0 68.088 0.084 ;
    END
  END xq[212]
  PIN xq[213]
    DIRECTION INPUT ;
    USE SIGNAL ;
    PORT
      LAYER M5 ;
        RECT  67.68 0 67.704 0.084 ;
    END
  END xq[213]
  PIN xq[214]
    DIRECTION INPUT ;
    USE SIGNAL ;
    PORT
      LAYER M5 ;
        RECT  67.584 0 67.608 0.084 ;
    END
  END xq[214]
  PIN xq[215]
    DIRECTION INPUT ;
    USE SIGNAL ;
    PORT
      LAYER M4 ;
        RECT  128.233 61.344 128.317 61.368 ;
    END
  END xq[215]
  PIN xq[216]
    DIRECTION INPUT ;
    USE SIGNAL ;
    PORT
      LAYER M4 ;
        RECT  128.233 53.28 128.317 53.304 ;
    END
  END xq[216]
  PIN xq[217]
    DIRECTION INPUT ;
    USE SIGNAL ;
    PORT
      LAYER M4 ;
        RECT  128.233 53.088 128.317 53.112 ;
    END
  END xq[217]
  PIN xq[218]
    DIRECTION INPUT ;
    USE SIGNAL ;
    PORT
      LAYER M4 ;
        RECT  128.233 53.184 128.317 53.208 ;
    END
  END xq[218]
  PIN xq[219]
    DIRECTION INPUT ;
    USE SIGNAL ;
    PORT
      LAYER M4 ;
        RECT  128.233 47.232 128.317 47.256 ;
    END
  END xq[219]
  PIN xq[21]
    DIRECTION INPUT ;
    USE SIGNAL ;
    PORT
      LAYER M5 ;
        RECT  55.584 0 55.608 0.084 ;
    END
  END xq[21]
  PIN xq[220]
    DIRECTION INPUT ;
    USE SIGNAL ;
    PORT
      LAYER M4 ;
        RECT  128.233 46.944 128.317 46.968 ;
    END
  END xq[220]
  PIN xq[221]
    DIRECTION INPUT ;
    USE SIGNAL ;
    PORT
      LAYER M4 ;
        RECT  128.233 44.352 128.317 44.376 ;
    END
  END xq[221]
  PIN xq[222]
    DIRECTION INPUT ;
    USE SIGNAL ;
    PORT
      LAYER M4 ;
        RECT  128.233 47.04 128.317 47.064 ;
    END
  END xq[222]
  PIN xq[223]
    DIRECTION INPUT ;
    USE SIGNAL ;
    PORT
      LAYER M4 ;
        RECT  128.233 52.992 128.317 53.016 ;
    END
  END xq[223]
  PIN xq[224]
    DIRECTION INPUT ;
    USE SIGNAL ;
    PORT
      LAYER M4 ;
        RECT  128.233 61.248 128.317 61.272 ;
    END
  END xq[224]
  PIN xq[225]
    DIRECTION INPUT ;
    USE SIGNAL ;
    PORT
      LAYER M4 ;
        RECT  128.233 60.672 128.317 60.696 ;
    END
  END xq[225]
  PIN xq[226]
    DIRECTION INPUT ;
    USE SIGNAL ;
    PORT
      LAYER M4 ;
        RECT  128.233 60.96 128.317 60.984 ;
    END
  END xq[226]
  PIN xq[227]
    DIRECTION INPUT ;
    USE SIGNAL ;
    PORT
      LAYER M4 ;
        RECT  128.233 56.352 128.317 56.376 ;
    END
  END xq[227]
  PIN xq[228]
    DIRECTION INPUT ;
    USE SIGNAL ;
    PORT
      LAYER M4 ;
        RECT  128.233 55.488 128.317 55.512 ;
    END
  END xq[228]
  PIN xq[229]
    DIRECTION INPUT ;
    USE SIGNAL ;
    PORT
      LAYER M4 ;
        RECT  128.233 55.584 128.317 55.608 ;
    END
  END xq[229]
  PIN xq[22]
    DIRECTION INPUT ;
    USE SIGNAL ;
    PORT
      LAYER M5 ;
        RECT  55.488 0 55.512 0.084 ;
    END
  END xq[22]
  PIN xq[230]
    DIRECTION INPUT ;
    USE SIGNAL ;
    PORT
      LAYER M4 ;
        RECT  128.233 55.776 128.317 55.8 ;
    END
  END xq[230]
  PIN xq[231]
    DIRECTION INPUT ;
    USE SIGNAL ;
    PORT
      LAYER M4 ;
        RECT  128.233 59.52 128.317 59.544 ;
    END
  END xq[231]
  PIN xq[232]
    DIRECTION INPUT ;
    USE SIGNAL ;
    PORT
      LAYER M4 ;
        RECT  128.233 60.384 128.317 60.408 ;
    END
  END xq[232]
  PIN xq[233]
    DIRECTION INPUT ;
    USE SIGNAL ;
    PORT
      LAYER M4 ;
        RECT  128.233 60.288 128.317 60.312 ;
    END
  END xq[233]
  PIN xq[234]
    DIRECTION INPUT ;
    USE SIGNAL ;
    PORT
      LAYER M4 ;
        RECT  128.233 60.096 128.317 60.12 ;
    END
  END xq[234]
  PIN xq[235]
    DIRECTION INPUT ;
    USE SIGNAL ;
    PORT
      LAYER M4 ;
        RECT  128.233 54.912 128.317 54.936 ;
    END
  END xq[235]
  PIN xq[236]
    DIRECTION INPUT ;
    USE SIGNAL ;
    PORT
      LAYER M4 ;
        RECT  128.233 53.376 128.317 53.4 ;
    END
  END xq[236]
  PIN xq[237]
    DIRECTION INPUT ;
    USE SIGNAL ;
    PORT
      LAYER M4 ;
        RECT  128.233 53.568 128.317 53.592 ;
    END
  END xq[237]
  PIN xq[238]
    DIRECTION INPUT ;
    USE SIGNAL ;
    PORT
      LAYER M4 ;
        RECT  128.233 53.472 128.317 53.496 ;
    END
  END xq[238]
  PIN xq[239]
    DIRECTION INPUT ;
    USE SIGNAL ;
    PORT
      LAYER M4 ;
        RECT  128.233 60.768 128.317 60.792 ;
    END
  END xq[239]
  PIN xq[23]
    DIRECTION INPUT ;
    USE SIGNAL ;
    PORT
      LAYER M5 ;
        RECT  51.072 0 51.096 0.084 ;
    END
  END xq[23]
  PIN xq[240]
    DIRECTION INPUT ;
    USE SIGNAL ;
    PORT
      LAYER M5 ;
        RECT  81.024 0 81.048 0.084 ;
    END
  END xq[240]
  PIN xq[241]
    DIRECTION INPUT ;
    USE SIGNAL ;
    PORT
      LAYER M5 ;
        RECT  80.832 0 80.856 0.084 ;
    END
  END xq[241]
  PIN xq[242]
    DIRECTION INPUT ;
    USE SIGNAL ;
    PORT
      LAYER M5 ;
        RECT  82.08 0 82.104 0.084 ;
    END
  END xq[242]
  PIN xq[243]
    DIRECTION INPUT ;
    USE SIGNAL ;
    PORT
      LAYER M5 ;
        RECT  81.792 0 81.816 0.084 ;
    END
  END xq[243]
  PIN xq[244]
    DIRECTION INPUT ;
    USE SIGNAL ;
    PORT
      LAYER M5 ;
        RECT  80.64 0 80.664 0.084 ;
    END
  END xq[244]
  PIN xq[245]
    DIRECTION INPUT ;
    USE SIGNAL ;
    PORT
      LAYER M5 ;
        RECT  81.408 0 81.432 0.084 ;
    END
  END xq[245]
  PIN xq[246]
    DIRECTION INPUT ;
    USE SIGNAL ;
    PORT
      LAYER M5 ;
        RECT  81.12 0 81.144 0.084 ;
    END
  END xq[246]
  PIN xq[247]
    DIRECTION INPUT ;
    USE SIGNAL ;
    PORT
      LAYER M5 ;
        RECT  80.448 0 80.472 0.084 ;
    END
  END xq[247]
  PIN xq[248]
    DIRECTION INPUT ;
    USE SIGNAL ;
    PORT
      LAYER M4 ;
        RECT  128.233 47.904 128.317 47.928 ;
    END
  END xq[248]
  PIN xq[249]
    DIRECTION INPUT ;
    USE SIGNAL ;
    PORT
      LAYER M4 ;
        RECT  128.233 47.136 128.317 47.16 ;
    END
  END xq[249]
  PIN xq[24]
    DIRECTION INPUT ;
    USE SIGNAL ;
    PORT
      LAYER M5 ;
        RECT  28.992 0 29.016 0.084 ;
    END
  END xq[24]
  PIN xq[250]
    DIRECTION INPUT ;
    USE SIGNAL ;
    PORT
      LAYER M4 ;
        RECT  128.233 48.48 128.317 48.504 ;
    END
  END xq[250]
  PIN xq[251]
    DIRECTION INPUT ;
    USE SIGNAL ;
    PORT
      LAYER M5 ;
        RECT  76.992 0 77.016 0.084 ;
    END
  END xq[251]
  PIN xq[252]
    DIRECTION INPUT ;
    USE SIGNAL ;
    PORT
      LAYER M5 ;
        RECT  74.592 0 74.616 0.084 ;
    END
  END xq[252]
  PIN xq[253]
    DIRECTION INPUT ;
    USE SIGNAL ;
    PORT
      LAYER M5 ;
        RECT  74.88 0 74.904 0.084 ;
    END
  END xq[253]
  PIN xq[254]
    DIRECTION INPUT ;
    USE SIGNAL ;
    PORT
      LAYER M5 ;
        RECT  74.496 0 74.52 0.084 ;
    END
  END xq[254]
  PIN xq[255]
    DIRECTION INPUT ;
    USE SIGNAL ;
    PORT
      LAYER M4 ;
        RECT  128.233 48.384 128.317 48.408 ;
    END
  END xq[255]
  PIN xq[256]
    DIRECTION INPUT ;
    USE SIGNAL ;
    PORT
      LAYER M4 ;
        RECT  0 69.984 0.084 70.008 ;
    END
  END xq[256]
  PIN xq[257]
    DIRECTION INPUT ;
    USE SIGNAL ;
    PORT
      LAYER M4 ;
        RECT  0 70.368 0.084 70.392 ;
    END
  END xq[257]
  PIN xq[258]
    DIRECTION INPUT ;
    USE SIGNAL ;
    PORT
      LAYER M4 ;
        RECT  0 70.464 0.084 70.488 ;
    END
  END xq[258]
  PIN xq[259]
    DIRECTION INPUT ;
    USE SIGNAL ;
    PORT
      LAYER M4 ;
        RECT  0 72.864 0.084 72.888 ;
    END
  END xq[259]
  PIN xq[25]
    DIRECTION INPUT ;
    USE SIGNAL ;
    PORT
      LAYER M5 ;
        RECT  29.088 0 29.112 0.084 ;
    END
  END xq[25]
  PIN xq[260]
    DIRECTION INPUT ;
    USE SIGNAL ;
    PORT
      LAYER M4 ;
        RECT  0 74.016 0.084 74.04 ;
    END
  END xq[260]
  PIN xq[261]
    DIRECTION INPUT ;
    USE SIGNAL ;
    PORT
      LAYER M4 ;
        RECT  0 73.44 0.084 73.464 ;
    END
  END xq[261]
  PIN xq[262]
    DIRECTION INPUT ;
    USE SIGNAL ;
    PORT
      LAYER M4 ;
        RECT  0 72.672 0.084 72.696 ;
    END
  END xq[262]
  PIN xq[263]
    DIRECTION INPUT ;
    USE SIGNAL ;
    PORT
      LAYER M4 ;
        RECT  0 70.56 0.084 70.584 ;
    END
  END xq[263]
  PIN xq[264]
    DIRECTION INPUT ;
    USE SIGNAL ;
    PORT
      LAYER M4 ;
        RECT  0 70.752 0.084 70.776 ;
    END
  END xq[264]
  PIN xq[265]
    DIRECTION INPUT ;
    USE SIGNAL ;
    PORT
      LAYER M4 ;
        RECT  0 70.944 0.084 70.968 ;
    END
  END xq[265]
  PIN xq[266]
    DIRECTION INPUT ;
    USE SIGNAL ;
    PORT
      LAYER M4 ;
        RECT  0 70.656 0.084 70.68 ;
    END
  END xq[266]
  PIN xq[267]
    DIRECTION INPUT ;
    USE SIGNAL ;
    PORT
      LAYER M4 ;
        RECT  0 71.136 0.084 71.16 ;
    END
  END xq[267]
  PIN xq[268]
    DIRECTION INPUT ;
    USE SIGNAL ;
    PORT
      LAYER M4 ;
        RECT  0 72.384 0.084 72.408 ;
    END
  END xq[268]
  PIN xq[269]
    DIRECTION INPUT ;
    USE SIGNAL ;
    PORT
      LAYER M4 ;
        RECT  0 72.288 0.084 72.312 ;
    END
  END xq[269]
  PIN xq[26]
    DIRECTION INPUT ;
    USE SIGNAL ;
    PORT
      LAYER M5 ;
        RECT  29.184 0 29.208 0.084 ;
    END
  END xq[26]
  PIN xq[270]
    DIRECTION INPUT ;
    USE SIGNAL ;
    PORT
      LAYER M4 ;
        RECT  0 70.176 0.084 70.2 ;
    END
  END xq[270]
  PIN xq[271]
    DIRECTION INPUT ;
    USE SIGNAL ;
    PORT
      LAYER M4 ;
        RECT  0 71.328 0.084 71.352 ;
    END
  END xq[271]
  PIN xq[272]
    DIRECTION INPUT ;
    USE SIGNAL ;
    PORT
      LAYER M4 ;
        RECT  0 75.072 0.084 75.096 ;
    END
  END xq[272]
  PIN xq[273]
    DIRECTION INPUT ;
    USE SIGNAL ;
    PORT
      LAYER M4 ;
        RECT  0 76.32 0.084 76.344 ;
    END
  END xq[273]
  PIN xq[274]
    DIRECTION INPUT ;
    USE SIGNAL ;
    PORT
      LAYER M4 ;
        RECT  0 76.512 0.084 76.536 ;
    END
  END xq[274]
  PIN xq[275]
    DIRECTION INPUT ;
    USE SIGNAL ;
    PORT
      LAYER M4 ;
        RECT  0 76.608 0.084 76.632 ;
    END
  END xq[275]
  PIN xq[276]
    DIRECTION INPUT ;
    USE SIGNAL ;
    PORT
      LAYER M4 ;
        RECT  0 72 0.084 72.024 ;
    END
  END xq[276]
  PIN xq[277]
    DIRECTION INPUT ;
    USE SIGNAL ;
    PORT
      LAYER M4 ;
        RECT  0 71.424 0.084 71.448 ;
    END
  END xq[277]
  PIN xq[278]
    DIRECTION INPUT ;
    USE SIGNAL ;
    PORT
      LAYER M4 ;
        RECT  0 76.704 0.084 76.728 ;
    END
  END xq[278]
  PIN xq[279]
    DIRECTION INPUT ;
    USE SIGNAL ;
    PORT
      LAYER M4 ;
        RECT  0 76.992 0.084 77.016 ;
    END
  END xq[279]
  PIN xq[27]
    DIRECTION INPUT ;
    USE SIGNAL ;
    PORT
      LAYER M5 ;
        RECT  31.296 0 31.32 0.084 ;
    END
  END xq[27]
  PIN xq[280]
    DIRECTION INPUT ;
    USE SIGNAL ;
    PORT
      LAYER M4 ;
        RECT  0 77.28 0.084 77.304 ;
    END
  END xq[280]
  PIN xq[281]
    DIRECTION INPUT ;
    USE SIGNAL ;
    PORT
      LAYER M4 ;
        RECT  0 77.376 0.084 77.4 ;
    END
  END xq[281]
  PIN xq[282]
    DIRECTION INPUT ;
    USE SIGNAL ;
    PORT
      LAYER M4 ;
        RECT  0 77.472 0.084 77.496 ;
    END
  END xq[282]
  PIN xq[283]
    DIRECTION INPUT ;
    USE SIGNAL ;
    PORT
      LAYER M4 ;
        RECT  0 77.568 0.084 77.592 ;
    END
  END xq[283]
  PIN xq[284]
    DIRECTION INPUT ;
    USE SIGNAL ;
    PORT
      LAYER M4 ;
        RECT  0 77.664 0.084 77.688 ;
    END
  END xq[284]
  PIN xq[285]
    DIRECTION INPUT ;
    USE SIGNAL ;
    PORT
      LAYER M4 ;
        RECT  0 77.76 0.084 77.784 ;
    END
  END xq[285]
  PIN xq[286]
    DIRECTION INPUT ;
    USE SIGNAL ;
    PORT
      LAYER M4 ;
        RECT  0 77.856 0.084 77.88 ;
    END
  END xq[286]
  PIN xq[287]
    DIRECTION INPUT ;
    USE SIGNAL ;
    PORT
      LAYER M4 ;
        RECT  0 77.952 0.084 77.976 ;
    END
  END xq[287]
  PIN xq[288]
    DIRECTION INPUT ;
    USE SIGNAL ;
    PORT
      LAYER M4 ;
        RECT  0 78.144 0.084 78.168 ;
    END
  END xq[288]
  PIN xq[289]
    DIRECTION INPUT ;
    USE SIGNAL ;
    PORT
      LAYER M4 ;
        RECT  0 78.24 0.084 78.264 ;
    END
  END xq[289]
  PIN xq[28]
    DIRECTION INPUT ;
    USE SIGNAL ;
    PORT
      LAYER M5 ;
        RECT  32.64 0 32.664 0.084 ;
    END
  END xq[28]
  PIN xq[290]
    DIRECTION INPUT ;
    USE SIGNAL ;
    PORT
      LAYER M4 ;
        RECT  0 78.336 0.084 78.36 ;
    END
  END xq[290]
  PIN xq[291]
    DIRECTION INPUT ;
    USE SIGNAL ;
    PORT
      LAYER M4 ;
        RECT  0 71.04 0.084 71.064 ;
    END
  END xq[291]
  PIN xq[292]
    DIRECTION INPUT ;
    USE SIGNAL ;
    PORT
      LAYER M4 ;
        RECT  0 71.808 0.084 71.832 ;
    END
  END xq[292]
  PIN xq[293]
    DIRECTION INPUT ;
    USE SIGNAL ;
    PORT
      LAYER M4 ;
        RECT  0 72.192 0.084 72.216 ;
    END
  END xq[293]
  PIN xq[294]
    DIRECTION INPUT ;
    USE SIGNAL ;
    PORT
      LAYER M4 ;
        RECT  0 72.48 0.084 72.504 ;
    END
  END xq[294]
  PIN xq[295]
    DIRECTION INPUT ;
    USE SIGNAL ;
    PORT
      LAYER M4 ;
        RECT  0 78.432 0.084 78.456 ;
    END
  END xq[295]
  PIN xq[296]
    DIRECTION INPUT ;
    USE SIGNAL ;
    PORT
      LAYER M4 ;
        RECT  0 78.528 0.084 78.552 ;
    END
  END xq[296]
  PIN xq[297]
    DIRECTION INPUT ;
    USE SIGNAL ;
    PORT
      LAYER M4 ;
        RECT  0 78.72 0.084 78.744 ;
    END
  END xq[297]
  PIN xq[298]
    DIRECTION INPUT ;
    USE SIGNAL ;
    PORT
      LAYER M4 ;
        RECT  0 78.816 0.084 78.84 ;
    END
  END xq[298]
  PIN xq[299]
    DIRECTION INPUT ;
    USE SIGNAL ;
    PORT
      LAYER M4 ;
        RECT  0 71.232 0.084 71.256 ;
    END
  END xq[299]
  PIN xq[29]
    DIRECTION INPUT ;
    USE SIGNAL ;
    PORT
      LAYER M5 ;
        RECT  31.392 0 31.416 0.084 ;
    END
  END xq[29]
  PIN xq[2]
    DIRECTION INPUT ;
    USE SIGNAL ;
    PORT
      LAYER M5 ;
        RECT  67.776 0 67.8 0.084 ;
    END
  END xq[2]
  PIN xq[300]
    DIRECTION INPUT ;
    USE SIGNAL ;
    PORT
      LAYER M4 ;
        RECT  0 73.152 0.084 73.176 ;
    END
  END xq[300]
  PIN xq[301]
    DIRECTION INPUT ;
    USE SIGNAL ;
    PORT
      LAYER M4 ;
        RECT  0 73.056 0.084 73.08 ;
    END
  END xq[301]
  PIN xq[302]
    DIRECTION INPUT ;
    USE SIGNAL ;
    PORT
      LAYER M4 ;
        RECT  0 72.576 0.084 72.6 ;
    END
  END xq[302]
  PIN xq[303]
    DIRECTION INPUT ;
    USE SIGNAL ;
    PORT
      LAYER M4 ;
        RECT  0 78.912 0.084 78.936 ;
    END
  END xq[303]
  PIN xq[304]
    DIRECTION INPUT ;
    USE SIGNAL ;
    PORT
      LAYER M4 ;
        RECT  0 77.184 0.084 77.208 ;
    END
  END xq[304]
  PIN xq[305]
    DIRECTION INPUT ;
    USE SIGNAL ;
    PORT
      LAYER M4 ;
        RECT  0 76.896 0.084 76.92 ;
    END
  END xq[305]
  PIN xq[306]
    DIRECTION INPUT ;
    USE SIGNAL ;
    PORT
      LAYER M4 ;
        RECT  0 78.624 0.084 78.648 ;
    END
  END xq[306]
  PIN xq[307]
    DIRECTION INPUT ;
    USE SIGNAL ;
    PORT
      LAYER M4 ;
        RECT  0 76.032 0.084 76.056 ;
    END
  END xq[307]
  PIN xq[308]
    DIRECTION INPUT ;
    USE SIGNAL ;
    PORT
      LAYER M4 ;
        RECT  0 74.688 0.084 74.712 ;
    END
  END xq[308]
  PIN xq[309]
    DIRECTION INPUT ;
    USE SIGNAL ;
    PORT
      LAYER M4 ;
        RECT  0 74.88 0.084 74.904 ;
    END
  END xq[309]
  PIN xq[30]
    DIRECTION INPUT ;
    USE SIGNAL ;
    PORT
      LAYER M5 ;
        RECT  30.912 0 30.936 0.084 ;
    END
  END xq[30]
  PIN xq[310]
    DIRECTION INPUT ;
    USE SIGNAL ;
    PORT
      LAYER M4 ;
        RECT  0 74.976 0.084 75 ;
    END
  END xq[310]
  PIN xq[311]
    DIRECTION INPUT ;
    USE SIGNAL ;
    PORT
      LAYER M4 ;
        RECT  0 75.36 0.084 75.384 ;
    END
  END xq[311]
  PIN xq[312]
    DIRECTION INPUT ;
    USE SIGNAL ;
    PORT
      LAYER M4 ;
        RECT  0 89.856 0.084 89.88 ;
    END
  END xq[312]
  PIN xq[313]
    DIRECTION INPUT ;
    USE SIGNAL ;
    PORT
      LAYER M4 ;
        RECT  0 93.408 0.084 93.432 ;
    END
  END xq[313]
  PIN xq[314]
    DIRECTION INPUT ;
    USE SIGNAL ;
    PORT
      LAYER M4 ;
        RECT  0 91.872 0.084 91.896 ;
    END
  END xq[314]
  PIN xq[315]
    DIRECTION INPUT ;
    USE SIGNAL ;
    PORT
      LAYER M4 ;
        RECT  0 95.136 0.084 95.16 ;
    END
  END xq[315]
  PIN xq[316]
    DIRECTION INPUT ;
    USE SIGNAL ;
    PORT
      LAYER M4 ;
        RECT  0 95.424 0.084 95.448 ;
    END
  END xq[316]
  PIN xq[317]
    DIRECTION INPUT ;
    USE SIGNAL ;
    PORT
      LAYER M4 ;
        RECT  0 95.328 0.084 95.352 ;
    END
  END xq[317]
  PIN xq[318]
    DIRECTION INPUT ;
    USE SIGNAL ;
    PORT
      LAYER M4 ;
        RECT  0 95.04 0.084 95.064 ;
    END
  END xq[318]
  PIN xq[319]
    DIRECTION INPUT ;
    USE SIGNAL ;
    PORT
      LAYER M4 ;
        RECT  0 92.736 0.084 92.76 ;
    END
  END xq[319]
  PIN xq[31]
    DIRECTION INPUT ;
    USE SIGNAL ;
    PORT
      LAYER M5 ;
        RECT  34.944 0 34.968 0.084 ;
    END
  END xq[31]
  PIN xq[320]
    DIRECTION INPUT ;
    USE SIGNAL ;
    PORT
      LAYER M4 ;
        RECT  0 82.368 0.084 82.392 ;
    END
  END xq[320]
  PIN xq[321]
    DIRECTION INPUT ;
    USE SIGNAL ;
    PORT
      LAYER M4 ;
        RECT  0 82.848 0.084 82.872 ;
    END
  END xq[321]
  PIN xq[322]
    DIRECTION INPUT ;
    USE SIGNAL ;
    PORT
      LAYER M4 ;
        RECT  0 81.216 0.084 81.24 ;
    END
  END xq[322]
  PIN xq[323]
    DIRECTION INPUT ;
    USE SIGNAL ;
    PORT
      LAYER M4 ;
        RECT  0 86.688 0.084 86.712 ;
    END
  END xq[323]
  PIN xq[324]
    DIRECTION INPUT ;
    USE SIGNAL ;
    PORT
      LAYER M4 ;
        RECT  0 87.744 0.084 87.768 ;
    END
  END xq[324]
  PIN xq[325]
    DIRECTION INPUT ;
    USE SIGNAL ;
    PORT
      LAYER M4 ;
        RECT  0 87.936 0.084 87.96 ;
    END
  END xq[325]
  PIN xq[326]
    DIRECTION INPUT ;
    USE SIGNAL ;
    PORT
      LAYER M4 ;
        RECT  0 88.128 0.084 88.152 ;
    END
  END xq[326]
  PIN xq[327]
    DIRECTION INPUT ;
    USE SIGNAL ;
    PORT
      LAYER M4 ;
        RECT  0 84.096 0.084 84.12 ;
    END
  END xq[327]
  PIN xq[328]
    DIRECTION INPUT ;
    USE SIGNAL ;
    PORT
      LAYER M4 ;
        RECT  0 98.688 0.084 98.712 ;
    END
  END xq[328]
  PIN xq[329]
    DIRECTION INPUT ;
    USE SIGNAL ;
    PORT
      LAYER M4 ;
        RECT  0 97.248 0.084 97.272 ;
    END
  END xq[329]
  PIN xq[32]
    DIRECTION INPUT ;
    USE SIGNAL ;
    PORT
      LAYER M5 ;
        RECT  36.48 0 36.504 0.084 ;
    END
  END xq[32]
  PIN xq[330]
    DIRECTION INPUT ;
    USE SIGNAL ;
    PORT
      LAYER M4 ;
        RECT  0 97.728 0.084 97.752 ;
    END
  END xq[330]
  PIN xq[331]
    DIRECTION INPUT ;
    USE SIGNAL ;
    PORT
      LAYER M4 ;
        RECT  0 99.168 0.084 99.192 ;
    END
  END xq[331]
  PIN xq[332]
    DIRECTION INPUT ;
    USE SIGNAL ;
    PORT
      LAYER M4 ;
        RECT  0 100.32 0.084 100.344 ;
    END
  END xq[332]
  PIN xq[333]
    DIRECTION INPUT ;
    USE SIGNAL ;
    PORT
      LAYER M4 ;
        RECT  0 99.84 0.084 99.864 ;
    END
  END xq[333]
  PIN xq[334]
    DIRECTION INPUT ;
    USE SIGNAL ;
    PORT
      LAYER M4 ;
        RECT  0 99.648 0.084 99.672 ;
    END
  END xq[334]
  PIN xq[335]
    DIRECTION INPUT ;
    USE SIGNAL ;
    PORT
      LAYER M4 ;
        RECT  0 96.672 0.084 96.696 ;
    END
  END xq[335]
  PIN xq[336]
    DIRECTION INPUT ;
    USE SIGNAL ;
    PORT
      LAYER M4 ;
        RECT  0 109.536 0.084 109.56 ;
    END
  END xq[336]
  PIN xq[337]
    DIRECTION INPUT ;
    USE SIGNAL ;
    PORT
      LAYER M4 ;
        RECT  0 109.824 0.084 109.848 ;
    END
  END xq[337]
  PIN xq[338]
    DIRECTION INPUT ;
    USE SIGNAL ;
    PORT
      LAYER M4 ;
        RECT  0 110.208 0.084 110.232 ;
    END
  END xq[338]
  PIN xq[339]
    DIRECTION INPUT ;
    USE SIGNAL ;
    PORT
      LAYER M4 ;
        RECT  0 110.016 0.084 110.04 ;
    END
  END xq[339]
  PIN xq[33]
    DIRECTION INPUT ;
    USE SIGNAL ;
    PORT
      LAYER M5 ;
        RECT  36.768 0 36.792 0.084 ;
    END
  END xq[33]
  PIN xq[340]
    DIRECTION INPUT ;
    USE SIGNAL ;
    PORT
      LAYER M4 ;
        RECT  0 110.304 0.084 110.328 ;
    END
  END xq[340]
  PIN xq[341]
    DIRECTION INPUT ;
    USE SIGNAL ;
    PORT
      LAYER M4 ;
        RECT  0 109.92 0.084 109.944 ;
    END
  END xq[341]
  PIN xq[342]
    DIRECTION INPUT ;
    USE SIGNAL ;
    PORT
      LAYER M4 ;
        RECT  0 110.112 0.084 110.136 ;
    END
  END xq[342]
  PIN xq[343]
    DIRECTION INPUT ;
    USE SIGNAL ;
    PORT
      LAYER M4 ;
        RECT  0 105.888 0.084 105.912 ;
    END
  END xq[343]
  PIN xq[344]
    DIRECTION INPUT ;
    USE SIGNAL ;
    PORT
      LAYER M4 ;
        RECT  0 102.72 0.084 102.744 ;
    END
  END xq[344]
  PIN xq[345]
    DIRECTION INPUT ;
    USE SIGNAL ;
    PORT
      LAYER M4 ;
        RECT  0 101.664 0.084 101.688 ;
    END
  END xq[345]
  PIN xq[346]
    DIRECTION INPUT ;
    USE SIGNAL ;
    PORT
      LAYER M4 ;
        RECT  0 101.76 0.084 101.784 ;
    END
  END xq[346]
  PIN xq[347]
    DIRECTION INPUT ;
    USE SIGNAL ;
    PORT
      LAYER M4 ;
        RECT  0 105.312 0.084 105.336 ;
    END
  END xq[347]
  PIN xq[348]
    DIRECTION INPUT ;
    USE SIGNAL ;
    PORT
      LAYER M4 ;
        RECT  0 105.792 0.084 105.816 ;
    END
  END xq[348]
  PIN xq[349]
    DIRECTION INPUT ;
    USE SIGNAL ;
    PORT
      LAYER M4 ;
        RECT  0 105.696 0.084 105.72 ;
    END
  END xq[349]
  PIN xq[34]
    DIRECTION INPUT ;
    USE SIGNAL ;
    PORT
      LAYER M5 ;
        RECT  36.384 0 36.408 0.084 ;
    END
  END xq[34]
  PIN xq[350]
    DIRECTION INPUT ;
    USE SIGNAL ;
    PORT
      LAYER M4 ;
        RECT  0 105.6 0.084 105.624 ;
    END
  END xq[350]
  PIN xq[351]
    DIRECTION INPUT ;
    USE SIGNAL ;
    PORT
      LAYER M4 ;
        RECT  0 100.224 0.084 100.248 ;
    END
  END xq[351]
  PIN xq[352]
    DIRECTION INPUT ;
    USE SIGNAL ;
    PORT
      LAYER M5 ;
        RECT  12.192 128.233 12.216 128.317 ;
    END
  END xq[352]
  PIN xq[353]
    DIRECTION INPUT ;
    USE SIGNAL ;
    PORT
      LAYER M5 ;
        RECT  12.288 128.233 12.312 128.317 ;
    END
  END xq[353]
  PIN xq[354]
    DIRECTION INPUT ;
    USE SIGNAL ;
    PORT
      LAYER M5 ;
        RECT  14.688 128.233 14.712 128.317 ;
    END
  END xq[354]
  PIN xq[355]
    DIRECTION INPUT ;
    USE SIGNAL ;
    PORT
      LAYER M5 ;
        RECT  16.512 128.233 16.536 128.317 ;
    END
  END xq[355]
  PIN xq[356]
    DIRECTION INPUT ;
    USE SIGNAL ;
    PORT
      LAYER M5 ;
        RECT  16.32 128.233 16.344 128.317 ;
    END
  END xq[356]
  PIN xq[357]
    DIRECTION INPUT ;
    USE SIGNAL ;
    PORT
      LAYER M5 ;
        RECT  16.896 128.233 16.92 128.317 ;
    END
  END xq[357]
  PIN xq[358]
    DIRECTION INPUT ;
    USE SIGNAL ;
    PORT
      LAYER M5 ;
        RECT  16.8 128.233 16.824 128.317 ;
    END
  END xq[358]
  PIN xq[359]
    DIRECTION INPUT ;
    USE SIGNAL ;
    PORT
      LAYER M4 ;
        RECT  0 119.616 0.084 119.64 ;
    END
  END xq[359]
  PIN xq[35]
    DIRECTION INPUT ;
    USE SIGNAL ;
    PORT
      LAYER M5 ;
        RECT  38.016 0 38.04 0.084 ;
    END
  END xq[35]
  PIN xq[360]
    DIRECTION INPUT ;
    USE SIGNAL ;
    PORT
      LAYER M4 ;
        RECT  0 114.432 0.084 114.456 ;
    END
  END xq[360]
  PIN xq[361]
    DIRECTION INPUT ;
    USE SIGNAL ;
    PORT
      LAYER M4 ;
        RECT  0 115.488 0.084 115.512 ;
    END
  END xq[361]
  PIN xq[362]
    DIRECTION INPUT ;
    USE SIGNAL ;
    PORT
      LAYER M4 ;
        RECT  0 113.664 0.084 113.688 ;
    END
  END xq[362]
  PIN xq[363]
    DIRECTION INPUT ;
    USE SIGNAL ;
    PORT
      LAYER M4 ;
        RECT  0 115.296 0.084 115.32 ;
    END
  END xq[363]
  PIN xq[364]
    DIRECTION INPUT ;
    USE SIGNAL ;
    PORT
      LAYER M4 ;
        RECT  0 114.144 0.084 114.168 ;
    END
  END xq[364]
  PIN xq[365]
    DIRECTION INPUT ;
    USE SIGNAL ;
    PORT
      LAYER M4 ;
        RECT  0 114.912 0.084 114.936 ;
    END
  END xq[365]
  PIN xq[366]
    DIRECTION INPUT ;
    USE SIGNAL ;
    PORT
      LAYER M5 ;
        RECT  17.376 128.233 17.4 128.317 ;
    END
  END xq[366]
  PIN xq[367]
    DIRECTION INPUT ;
    USE SIGNAL ;
    PORT
      LAYER M4 ;
        RECT  0 116.544 0.084 116.568 ;
    END
  END xq[367]
  PIN xq[368]
    DIRECTION INPUT ;
    USE SIGNAL ;
    PORT
      LAYER M5 ;
        RECT  21.408 128.233 21.432 128.317 ;
    END
  END xq[368]
  PIN xq[369]
    DIRECTION INPUT ;
    USE SIGNAL ;
    PORT
      LAYER M5 ;
        RECT  21.024 128.233 21.048 128.317 ;
    END
  END xq[369]
  PIN xq[36]
    DIRECTION INPUT ;
    USE SIGNAL ;
    PORT
      LAYER M5 ;
        RECT  37.536 0 37.56 0.084 ;
    END
  END xq[36]
  PIN xq[370]
    DIRECTION INPUT ;
    USE SIGNAL ;
    PORT
      LAYER M5 ;
        RECT  21.6 128.233 21.624 128.317 ;
    END
  END xq[370]
  PIN xq[371]
    DIRECTION INPUT ;
    USE SIGNAL ;
    PORT
      LAYER M5 ;
        RECT  22.656 128.233 22.68 128.317 ;
    END
  END xq[371]
  PIN xq[372]
    DIRECTION INPUT ;
    USE SIGNAL ;
    PORT
      LAYER M5 ;
        RECT  22.848 128.233 22.872 128.317 ;
    END
  END xq[372]
  PIN xq[373]
    DIRECTION INPUT ;
    USE SIGNAL ;
    PORT
      LAYER M5 ;
        RECT  23.424 128.233 23.448 128.317 ;
    END
  END xq[373]
  PIN xq[374]
    DIRECTION INPUT ;
    USE SIGNAL ;
    PORT
      LAYER M5 ;
        RECT  23.328 128.233 23.352 128.317 ;
    END
  END xq[374]
  PIN xq[375]
    DIRECTION INPUT ;
    USE SIGNAL ;
    PORT
      LAYER M5 ;
        RECT  27.072 128.233 27.096 128.317 ;
    END
  END xq[375]
  PIN xq[376]
    DIRECTION INPUT ;
    USE SIGNAL ;
    PORT
      LAYER M5 ;
        RECT  36.96 128.233 36.984 128.317 ;
    END
  END xq[376]
  PIN xq[377]
    DIRECTION INPUT ;
    USE SIGNAL ;
    PORT
      LAYER M5 ;
        RECT  36.864 128.233 36.888 128.317 ;
    END
  END xq[377]
  PIN xq[378]
    DIRECTION INPUT ;
    USE SIGNAL ;
    PORT
      LAYER M5 ;
        RECT  37.344 128.233 37.368 128.317 ;
    END
  END xq[378]
  PIN xq[379]
    DIRECTION INPUT ;
    USE SIGNAL ;
    PORT
      LAYER M5 ;
        RECT  37.632 128.233 37.656 128.317 ;
    END
  END xq[379]
  PIN xq[37]
    DIRECTION INPUT ;
    USE SIGNAL ;
    PORT
      LAYER M5 ;
        RECT  37.248 0 37.272 0.084 ;
    END
  END xq[37]
  PIN xq[380]
    DIRECTION INPUT ;
    USE SIGNAL ;
    PORT
      LAYER M5 ;
        RECT  36.768 128.233 36.792 128.317 ;
    END
  END xq[380]
  PIN xq[381]
    DIRECTION INPUT ;
    USE SIGNAL ;
    PORT
      LAYER M5 ;
        RECT  37.536 128.233 37.56 128.317 ;
    END
  END xq[381]
  PIN xq[382]
    DIRECTION INPUT ;
    USE SIGNAL ;
    PORT
      LAYER M5 ;
        RECT  37.152 128.233 37.176 128.317 ;
    END
  END xq[382]
  PIN xq[383]
    DIRECTION INPUT ;
    USE SIGNAL ;
    PORT
      LAYER M5 ;
        RECT  37.056 128.233 37.08 128.317 ;
    END
  END xq[383]
  PIN xq[384]
    DIRECTION INPUT ;
    USE SIGNAL ;
    PORT
      LAYER M5 ;
        RECT  29.952 128.233 29.976 128.317 ;
    END
  END xq[384]
  PIN xq[385]
    DIRECTION INPUT ;
    USE SIGNAL ;
    PORT
      LAYER M5 ;
        RECT  29.76 128.233 29.784 128.317 ;
    END
  END xq[385]
  PIN xq[386]
    DIRECTION INPUT ;
    USE SIGNAL ;
    PORT
      LAYER M5 ;
        RECT  30.144 128.233 30.168 128.317 ;
    END
  END xq[386]
  PIN xq[387]
    DIRECTION INPUT ;
    USE SIGNAL ;
    PORT
      LAYER M5 ;
        RECT  30.528 128.233 30.552 128.317 ;
    END
  END xq[387]
  PIN xq[388]
    DIRECTION INPUT ;
    USE SIGNAL ;
    PORT
      LAYER M5 ;
        RECT  31.488 128.233 31.512 128.317 ;
    END
  END xq[388]
  PIN xq[389]
    DIRECTION INPUT ;
    USE SIGNAL ;
    PORT
      LAYER M5 ;
        RECT  31.296 128.233 31.32 128.317 ;
    END
  END xq[389]
  PIN xq[38]
    DIRECTION INPUT ;
    USE SIGNAL ;
    PORT
      LAYER M5 ;
        RECT  37.056 0 37.08 0.084 ;
    END
  END xq[38]
  PIN xq[390]
    DIRECTION INPUT ;
    USE SIGNAL ;
    PORT
      LAYER M5 ;
        RECT  30.432 128.233 30.456 128.317 ;
    END
  END xq[390]
  PIN xq[391]
    DIRECTION INPUT ;
    USE SIGNAL ;
    PORT
      LAYER M5 ;
        RECT  30.336 128.233 30.36 128.317 ;
    END
  END xq[391]
  PIN xq[392]
    DIRECTION INPUT ;
    USE SIGNAL ;
    PORT
      LAYER M5 ;
        RECT  47.52 128.233 47.544 128.317 ;
    END
  END xq[392]
  PIN xq[393]
    DIRECTION INPUT ;
    USE SIGNAL ;
    PORT
      LAYER M5 ;
        RECT  45.12 128.233 45.144 128.317 ;
    END
  END xq[393]
  PIN xq[394]
    DIRECTION INPUT ;
    USE SIGNAL ;
    PORT
      LAYER M5 ;
        RECT  46.56 128.233 46.584 128.317 ;
    END
  END xq[394]
  PIN xq[395]
    DIRECTION INPUT ;
    USE SIGNAL ;
    PORT
      LAYER M5 ;
        RECT  44.256 128.233 44.28 128.317 ;
    END
  END xq[395]
  PIN xq[396]
    DIRECTION INPUT ;
    USE SIGNAL ;
    PORT
      LAYER M5 ;
        RECT  43.872 128.233 43.896 128.317 ;
    END
  END xq[396]
  PIN xq[397]
    DIRECTION INPUT ;
    USE SIGNAL ;
    PORT
      LAYER M5 ;
        RECT  43.68 128.233 43.704 128.317 ;
    END
  END xq[397]
  PIN xq[398]
    DIRECTION INPUT ;
    USE SIGNAL ;
    PORT
      LAYER M5 ;
        RECT  43.776 128.233 43.8 128.317 ;
    END
  END xq[398]
  PIN xq[399]
    DIRECTION INPUT ;
    USE SIGNAL ;
    PORT
      LAYER M5 ;
        RECT  49.728 128.233 49.752 128.317 ;
    END
  END xq[399]
  PIN xq[39]
    DIRECTION INPUT ;
    USE SIGNAL ;
    PORT
      LAYER M5 ;
        RECT  36.576 0 36.6 0.084 ;
    END
  END xq[39]
  PIN xq[3]
    DIRECTION INPUT ;
    USE SIGNAL ;
    PORT
      LAYER M5 ;
        RECT  64.128 0 64.152 0.084 ;
    END
  END xq[3]
  PIN xq[400]
    DIRECTION INPUT ;
    USE SIGNAL ;
    PORT
      LAYER M5 ;
        RECT  63.456 128.233 63.48 128.317 ;
    END
  END xq[400]
  PIN xq[401]
    DIRECTION INPUT ;
    USE SIGNAL ;
    PORT
      LAYER M5 ;
        RECT  62.016 128.233 62.04 128.317 ;
    END
  END xq[401]
  PIN xq[402]
    DIRECTION INPUT ;
    USE SIGNAL ;
    PORT
      LAYER M5 ;
        RECT  62.208 128.233 62.232 128.317 ;
    END
  END xq[402]
  PIN xq[403]
    DIRECTION INPUT ;
    USE SIGNAL ;
    PORT
      LAYER M5 ;
        RECT  62.112 128.233 62.136 128.317 ;
    END
  END xq[403]
  PIN xq[404]
    DIRECTION INPUT ;
    USE SIGNAL ;
    PORT
      LAYER M5 ;
        RECT  61.824 128.233 61.848 128.317 ;
    END
  END xq[404]
  PIN xq[405]
    DIRECTION INPUT ;
    USE SIGNAL ;
    PORT
      LAYER M5 ;
        RECT  62.592 128.233 62.616 128.317 ;
    END
  END xq[405]
  PIN xq[406]
    DIRECTION INPUT ;
    USE SIGNAL ;
    PORT
      LAYER M5 ;
        RECT  61.92 128.233 61.944 128.317 ;
    END
  END xq[406]
  PIN xq[407]
    DIRECTION INPUT ;
    USE SIGNAL ;
    PORT
      LAYER M5 ;
        RECT  60.768 128.233 60.792 128.317 ;
    END
  END xq[407]
  PIN xq[408]
    DIRECTION INPUT ;
    USE SIGNAL ;
    PORT
      LAYER M5 ;
        RECT  49.056 128.233 49.08 128.317 ;
    END
  END xq[408]
  PIN xq[409]
    DIRECTION INPUT ;
    USE SIGNAL ;
    PORT
      LAYER M5 ;
        RECT  48.768 128.233 48.792 128.317 ;
    END
  END xq[409]
  PIN xq[40]
    DIRECTION INPUT ;
    USE SIGNAL ;
    PORT
      LAYER M5 ;
        RECT  45.696 0 45.72 0.084 ;
    END
  END xq[40]
  PIN xq[410]
    DIRECTION INPUT ;
    USE SIGNAL ;
    PORT
      LAYER M5 ;
        RECT  48.864 128.233 48.888 128.317 ;
    END
  END xq[410]
  PIN xq[411]
    DIRECTION INPUT ;
    USE SIGNAL ;
    PORT
      LAYER M5 ;
        RECT  49.632 128.233 49.656 128.317 ;
    END
  END xq[411]
  PIN xq[412]
    DIRECTION INPUT ;
    USE SIGNAL ;
    PORT
      LAYER M5 ;
        RECT  49.824 128.233 49.848 128.317 ;
    END
  END xq[412]
  PIN xq[413]
    DIRECTION INPUT ;
    USE SIGNAL ;
    PORT
      LAYER M5 ;
        RECT  49.92 128.233 49.944 128.317 ;
    END
  END xq[413]
  PIN xq[414]
    DIRECTION INPUT ;
    USE SIGNAL ;
    PORT
      LAYER M5 ;
        RECT  50.112 128.233 50.136 128.317 ;
    END
  END xq[414]
  PIN xq[415]
    DIRECTION INPUT ;
    USE SIGNAL ;
    PORT
      LAYER M5 ;
        RECT  53.664 128.233 53.688 128.317 ;
    END
  END xq[415]
  PIN xq[416]
    DIRECTION INPUT ;
    USE SIGNAL ;
    PORT
      LAYER M5 ;
        RECT  52.416 128.233 52.44 128.317 ;
    END
  END xq[416]
  PIN xq[417]
    DIRECTION INPUT ;
    USE SIGNAL ;
    PORT
      LAYER M5 ;
        RECT  52.32 128.233 52.344 128.317 ;
    END
  END xq[417]
  PIN xq[418]
    DIRECTION INPUT ;
    USE SIGNAL ;
    PORT
      LAYER M5 ;
        RECT  52.608 128.233 52.632 128.317 ;
    END
  END xq[418]
  PIN xq[419]
    DIRECTION INPUT ;
    USE SIGNAL ;
    PORT
      LAYER M5 ;
        RECT  54.336 128.233 54.36 128.317 ;
    END
  END xq[419]
  PIN xq[41]
    DIRECTION INPUT ;
    USE SIGNAL ;
    PORT
      LAYER M5 ;
        RECT  45.504 0 45.528 0.084 ;
    END
  END xq[41]
  PIN xq[420]
    DIRECTION INPUT ;
    USE SIGNAL ;
    PORT
      LAYER M5 ;
        RECT  54.432 128.233 54.456 128.317 ;
    END
  END xq[420]
  PIN xq[421]
    DIRECTION INPUT ;
    USE SIGNAL ;
    PORT
      LAYER M5 ;
        RECT  53.856 128.233 53.88 128.317 ;
    END
  END xq[421]
  PIN xq[422]
    DIRECTION INPUT ;
    USE SIGNAL ;
    PORT
      LAYER M5 ;
        RECT  53.76 128.233 53.784 128.317 ;
    END
  END xq[422]
  PIN xq[423]
    DIRECTION INPUT ;
    USE SIGNAL ;
    PORT
      LAYER M5 ;
        RECT  52.224 128.233 52.248 128.317 ;
    END
  END xq[423]
  PIN xq[424]
    DIRECTION INPUT ;
    USE SIGNAL ;
    PORT
      LAYER M5 ;
        RECT  71.232 128.233 71.256 128.317 ;
    END
  END xq[424]
  PIN xq[425]
    DIRECTION INPUT ;
    USE SIGNAL ;
    PORT
      LAYER M5 ;
        RECT  71.136 128.233 71.16 128.317 ;
    END
  END xq[425]
  PIN xq[426]
    DIRECTION INPUT ;
    USE SIGNAL ;
    PORT
      LAYER M5 ;
        RECT  71.328 128.233 71.352 128.317 ;
    END
  END xq[426]
  PIN xq[427]
    DIRECTION INPUT ;
    USE SIGNAL ;
    PORT
      LAYER M5 ;
        RECT  70.464 128.233 70.488 128.317 ;
    END
  END xq[427]
  PIN xq[428]
    DIRECTION INPUT ;
    USE SIGNAL ;
    PORT
      LAYER M5 ;
        RECT  69.888 128.233 69.912 128.317 ;
    END
  END xq[428]
  PIN xq[429]
    DIRECTION INPUT ;
    USE SIGNAL ;
    PORT
      LAYER M5 ;
        RECT  69.6 128.233 69.624 128.317 ;
    END
  END xq[429]
  PIN xq[42]
    DIRECTION INPUT ;
    USE SIGNAL ;
    PORT
      LAYER M5 ;
        RECT  45.984 0 46.008 0.084 ;
    END
  END xq[42]
  PIN xq[430]
    DIRECTION INPUT ;
    USE SIGNAL ;
    PORT
      LAYER M5 ;
        RECT  69.504 128.233 69.528 128.317 ;
    END
  END xq[430]
  PIN xq[431]
    DIRECTION INPUT ;
    USE SIGNAL ;
    PORT
      LAYER M5 ;
        RECT  73.152 128.233 73.176 128.317 ;
    END
  END xq[431]
  PIN xq[432]
    DIRECTION INPUT ;
    USE SIGNAL ;
    PORT
      LAYER M5 ;
        RECT  85.728 128.233 85.752 128.317 ;
    END
  END xq[432]
  PIN xq[433]
    DIRECTION INPUT ;
    USE SIGNAL ;
    PORT
      LAYER M5 ;
        RECT  86.016 128.233 86.04 128.317 ;
    END
  END xq[433]
  PIN xq[434]
    DIRECTION INPUT ;
    USE SIGNAL ;
    PORT
      LAYER M5 ;
        RECT  82.944 128.233 82.968 128.317 ;
    END
  END xq[434]
  PIN xq[435]
    DIRECTION INPUT ;
    USE SIGNAL ;
    PORT
      LAYER M5 ;
        RECT  80.64 128.233 80.664 128.317 ;
    END
  END xq[435]
  PIN xq[436]
    DIRECTION INPUT ;
    USE SIGNAL ;
    PORT
      LAYER M5 ;
        RECT  80.448 128.233 80.472 128.317 ;
    END
  END xq[436]
  PIN xq[437]
    DIRECTION INPUT ;
    USE SIGNAL ;
    PORT
      LAYER M5 ;
        RECT  80.16 128.233 80.184 128.317 ;
    END
  END xq[437]
  PIN xq[438]
    DIRECTION INPUT ;
    USE SIGNAL ;
    PORT
      LAYER M5 ;
        RECT  80.352 128.233 80.376 128.317 ;
    END
  END xq[438]
  PIN xq[439]
    DIRECTION INPUT ;
    USE SIGNAL ;
    PORT
      LAYER M5 ;
        RECT  85.92 128.233 85.944 128.317 ;
    END
  END xq[439]
  PIN xq[43]
    DIRECTION INPUT ;
    USE SIGNAL ;
    PORT
      LAYER M5 ;
        RECT  45.12 0 45.144 0.084 ;
    END
  END xq[43]
  PIN xq[440]
    DIRECTION INPUT ;
    USE SIGNAL ;
    PORT
      LAYER M5 ;
        RECT  92.256 128.233 92.28 128.317 ;
    END
  END xq[440]
  PIN xq[441]
    DIRECTION INPUT ;
    USE SIGNAL ;
    PORT
      LAYER M5 ;
        RECT  92.064 128.233 92.088 128.317 ;
    END
  END xq[441]
  PIN xq[442]
    DIRECTION INPUT ;
    USE SIGNAL ;
    PORT
      LAYER M5 ;
        RECT  92.16 128.233 92.184 128.317 ;
    END
  END xq[442]
  PIN xq[443]
    DIRECTION INPUT ;
    USE SIGNAL ;
    PORT
      LAYER M5 ;
        RECT  88.032 128.233 88.056 128.317 ;
    END
  END xq[443]
  PIN xq[444]
    DIRECTION INPUT ;
    USE SIGNAL ;
    PORT
      LAYER M5 ;
        RECT  89.088 128.233 89.112 128.317 ;
    END
  END xq[444]
  PIN xq[445]
    DIRECTION INPUT ;
    USE SIGNAL ;
    PORT
      LAYER M5 ;
        RECT  87.936 128.233 87.96 128.317 ;
    END
  END xq[445]
  PIN xq[446]
    DIRECTION INPUT ;
    USE SIGNAL ;
    PORT
      LAYER M5 ;
        RECT  87.744 128.233 87.768 128.317 ;
    END
  END xq[446]
  PIN xq[447]
    DIRECTION INPUT ;
    USE SIGNAL ;
    PORT
      LAYER M5 ;
        RECT  86.304 128.233 86.328 128.317 ;
    END
  END xq[447]
  PIN xq[448]
    DIRECTION INPUT ;
    USE SIGNAL ;
    PORT
      LAYER M5 ;
        RECT  86.688 128.233 86.712 128.317 ;
    END
  END xq[448]
  PIN xq[449]
    DIRECTION INPUT ;
    USE SIGNAL ;
    PORT
      LAYER M5 ;
        RECT  86.88 128.233 86.904 128.317 ;
    END
  END xq[449]
  PIN xq[44]
    DIRECTION INPUT ;
    USE SIGNAL ;
    PORT
      LAYER M5 ;
        RECT  43.488 0 43.512 0.084 ;
    END
  END xq[44]
  PIN xq[450]
    DIRECTION INPUT ;
    USE SIGNAL ;
    PORT
      LAYER M5 ;
        RECT  87.552 128.233 87.576 128.317 ;
    END
  END xq[450]
  PIN xq[451]
    DIRECTION INPUT ;
    USE SIGNAL ;
    PORT
      LAYER M5 ;
        RECT  83.04 128.233 83.064 128.317 ;
    END
  END xq[451]
  PIN xq[452]
    DIRECTION INPUT ;
    USE SIGNAL ;
    PORT
      LAYER M5 ;
        RECT  79.872 128.233 79.896 128.317 ;
    END
  END xq[452]
  PIN xq[453]
    DIRECTION INPUT ;
    USE SIGNAL ;
    PORT
      LAYER M5 ;
        RECT  80.256 128.233 80.28 128.317 ;
    END
  END xq[453]
  PIN xq[454]
    DIRECTION INPUT ;
    USE SIGNAL ;
    PORT
      LAYER M5 ;
        RECT  81.024 128.233 81.048 128.317 ;
    END
  END xq[454]
  PIN xq[455]
    DIRECTION INPUT ;
    USE SIGNAL ;
    PORT
      LAYER M5 ;
        RECT  86.4 128.233 86.424 128.317 ;
    END
  END xq[455]
  PIN xq[456]
    DIRECTION INPUT ;
    USE SIGNAL ;
    PORT
      LAYER M4 ;
        RECT  128.233 85.632 128.317 85.656 ;
    END
  END xq[456]
  PIN xq[457]
    DIRECTION INPUT ;
    USE SIGNAL ;
    PORT
      LAYER M4 ;
        RECT  128.233 85.536 128.317 85.56 ;
    END
  END xq[457]
  PIN xq[458]
    DIRECTION INPUT ;
    USE SIGNAL ;
    PORT
      LAYER M4 ;
        RECT  128.233 85.44 128.317 85.464 ;
    END
  END xq[458]
  PIN xq[459]
    DIRECTION INPUT ;
    USE SIGNAL ;
    PORT
      LAYER M5 ;
        RECT  82.272 128.233 82.296 128.317 ;
    END
  END xq[459]
  PIN xq[45]
    DIRECTION INPUT ;
    USE SIGNAL ;
    PORT
      LAYER M5 ;
        RECT  43.584 0 43.608 0.084 ;
    END
  END xq[45]
  PIN xq[460]
    DIRECTION INPUT ;
    USE SIGNAL ;
    PORT
      LAYER M5 ;
        RECT  80.544 128.233 80.568 128.317 ;
    END
  END xq[460]
  PIN xq[461]
    DIRECTION INPUT ;
    USE SIGNAL ;
    PORT
      LAYER M5 ;
        RECT  79.776 128.233 79.8 128.317 ;
    END
  END xq[461]
  PIN xq[462]
    DIRECTION INPUT ;
    USE SIGNAL ;
    PORT
      LAYER M5 ;
        RECT  80.064 128.233 80.088 128.317 ;
    END
  END xq[462]
  PIN xq[463]
    DIRECTION INPUT ;
    USE SIGNAL ;
    PORT
      LAYER M5 ;
        RECT  83.424 128.233 83.448 128.317 ;
    END
  END xq[463]
  PIN xq[464]
    DIRECTION INPUT ;
    USE SIGNAL ;
    PORT
      LAYER M5 ;
        RECT  89.856 128.233 89.88 128.317 ;
    END
  END xq[464]
  PIN xq[465]
    DIRECTION INPUT ;
    USE SIGNAL ;
    PORT
      LAYER M5 ;
        RECT  88.608 128.233 88.632 128.317 ;
    END
  END xq[465]
  PIN xq[466]
    DIRECTION INPUT ;
    USE SIGNAL ;
    PORT
      LAYER M5 ;
        RECT  88.992 128.233 89.016 128.317 ;
    END
  END xq[466]
  PIN xq[467]
    DIRECTION INPUT ;
    USE SIGNAL ;
    PORT
      LAYER M5 ;
        RECT  87.84 128.233 87.864 128.317 ;
    END
  END xq[467]
  PIN xq[468]
    DIRECTION INPUT ;
    USE SIGNAL ;
    PORT
      LAYER M5 ;
        RECT  83.808 128.233 83.832 128.317 ;
    END
  END xq[468]
  PIN xq[469]
    DIRECTION INPUT ;
    USE SIGNAL ;
    PORT
      LAYER M5 ;
        RECT  85.344 128.233 85.368 128.317 ;
    END
  END xq[469]
  PIN xq[46]
    DIRECTION INPUT ;
    USE SIGNAL ;
    PORT
      LAYER M5 ;
        RECT  44.16 0 44.184 0.084 ;
    END
  END xq[46]
  PIN xq[470]
    DIRECTION INPUT ;
    USE SIGNAL ;
    PORT
      LAYER M5 ;
        RECT  87.264 128.233 87.288 128.317 ;
    END
  END xq[470]
  PIN xq[471]
    DIRECTION INPUT ;
    USE SIGNAL ;
    PORT
      LAYER M5 ;
        RECT  87.648 128.233 87.672 128.317 ;
    END
  END xq[471]
  PIN xq[472]
    DIRECTION INPUT ;
    USE SIGNAL ;
    PORT
      LAYER M5 ;
        RECT  78.528 128.233 78.552 128.317 ;
    END
  END xq[472]
  PIN xq[473]
    DIRECTION INPUT ;
    USE SIGNAL ;
    PORT
      LAYER M5 ;
        RECT  78.144 128.233 78.168 128.317 ;
    END
  END xq[473]
  PIN xq[474]
    DIRECTION INPUT ;
    USE SIGNAL ;
    PORT
      LAYER M5 ;
        RECT  79.68 128.233 79.704 128.317 ;
    END
  END xq[474]
  PIN xq[475]
    DIRECTION INPUT ;
    USE SIGNAL ;
    PORT
      LAYER M5 ;
        RECT  73.92 128.233 73.944 128.317 ;
    END
  END xq[475]
  PIN xq[476]
    DIRECTION INPUT ;
    USE SIGNAL ;
    PORT
      LAYER M5 ;
        RECT  71.616 128.233 71.64 128.317 ;
    END
  END xq[476]
  PIN xq[477]
    DIRECTION INPUT ;
    USE SIGNAL ;
    PORT
      LAYER M5 ;
        RECT  73.056 128.233 73.08 128.317 ;
    END
  END xq[477]
  PIN xq[478]
    DIRECTION INPUT ;
    USE SIGNAL ;
    PORT
      LAYER M5 ;
        RECT  73.248 128.233 73.272 128.317 ;
    END
  END xq[478]
  PIN xq[479]
    DIRECTION INPUT ;
    USE SIGNAL ;
    PORT
      LAYER M5 ;
        RECT  76.128 128.233 76.152 128.317 ;
    END
  END xq[479]
  PIN xq[47]
    DIRECTION INPUT ;
    USE SIGNAL ;
    PORT
      LAYER M5 ;
        RECT  45.888 0 45.912 0.084 ;
    END
  END xq[47]
  PIN xq[480]
    DIRECTION INPUT ;
    USE SIGNAL ;
    PORT
      LAYER M4 ;
        RECT  128.233 65.952 128.317 65.976 ;
    END
  END xq[480]
  PIN xq[481]
    DIRECTION INPUT ;
    USE SIGNAL ;
    PORT
      LAYER M4 ;
        RECT  128.233 66.432 128.317 66.456 ;
    END
  END xq[481]
  PIN xq[482]
    DIRECTION INPUT ;
    USE SIGNAL ;
    PORT
      LAYER M4 ;
        RECT  128.233 65.856 128.317 65.88 ;
    END
  END xq[482]
  PIN xq[483]
    DIRECTION INPUT ;
    USE SIGNAL ;
    PORT
      LAYER M4 ;
        RECT  128.233 69.024 128.317 69.048 ;
    END
  END xq[483]
  PIN xq[484]
    DIRECTION INPUT ;
    USE SIGNAL ;
    PORT
      LAYER M5 ;
        RECT  63.552 128.233 63.576 128.317 ;
    END
  END xq[484]
  PIN xq[485]
    DIRECTION INPUT ;
    USE SIGNAL ;
    PORT
      LAYER M5 ;
        RECT  63.744 128.233 63.768 128.317 ;
    END
  END xq[485]
  PIN xq[486]
    DIRECTION INPUT ;
    USE SIGNAL ;
    PORT
      LAYER M5 ;
        RECT  63.84 128.233 63.864 128.317 ;
    END
  END xq[486]
  PIN xq[487]
    DIRECTION INPUT ;
    USE SIGNAL ;
    PORT
      LAYER M4 ;
        RECT  128.233 71.136 128.317 71.16 ;
    END
  END xq[487]
  PIN xq[488]
    DIRECTION INPUT ;
    USE SIGNAL ;
    PORT
      LAYER M5 ;
        RECT  56.64 128.233 56.664 128.317 ;
    END
  END xq[488]
  PIN xq[489]
    DIRECTION INPUT ;
    USE SIGNAL ;
    PORT
      LAYER M5 ;
        RECT  56.256 128.233 56.28 128.317 ;
    END
  END xq[489]
  PIN xq[48]
    DIRECTION INPUT ;
    USE SIGNAL ;
    PORT
      LAYER M5 ;
        RECT  15.36 0 15.384 0.084 ;
    END
  END xq[48]
  PIN xq[490]
    DIRECTION INPUT ;
    USE SIGNAL ;
    PORT
      LAYER M5 ;
        RECT  56.928 128.233 56.952 128.317 ;
    END
  END xq[490]
  PIN xq[491]
    DIRECTION INPUT ;
    USE SIGNAL ;
    PORT
      LAYER M5 ;
        RECT  57.312 128.233 57.336 128.317 ;
    END
  END xq[491]
  PIN xq[492]
    DIRECTION INPUT ;
    USE SIGNAL ;
    PORT
      LAYER M5 ;
        RECT  56.544 128.233 56.568 128.317 ;
    END
  END xq[492]
  PIN xq[493]
    DIRECTION INPUT ;
    USE SIGNAL ;
    PORT
      LAYER M5 ;
        RECT  56.832 128.233 56.856 128.317 ;
    END
  END xq[493]
  PIN xq[494]
    DIRECTION INPUT ;
    USE SIGNAL ;
    PORT
      LAYER M5 ;
        RECT  56.736 128.233 56.76 128.317 ;
    END
  END xq[494]
  PIN xq[495]
    DIRECTION INPUT ;
    USE SIGNAL ;
    PORT
      LAYER M5 ;
        RECT  56.448 128.233 56.472 128.317 ;
    END
  END xq[495]
  PIN xq[496]
    DIRECTION INPUT ;
    USE SIGNAL ;
    PORT
      LAYER M4 ;
        RECT  0 79.008 0.084 79.032 ;
    END
  END xq[496]
  PIN xq[497]
    DIRECTION INPUT ;
    USE SIGNAL ;
    PORT
      LAYER M4 ;
        RECT  0 79.104 0.084 79.128 ;
    END
  END xq[497]
  PIN xq[498]
    DIRECTION INPUT ;
    USE SIGNAL ;
    PORT
      LAYER M4 ;
        RECT  0 79.2 0.084 79.224 ;
    END
  END xq[498]
  PIN xq[499]
    DIRECTION INPUT ;
    USE SIGNAL ;
    PORT
      LAYER M4 ;
        RECT  0 72.96 0.084 72.984 ;
    END
  END xq[499]
  PIN xq[49]
    DIRECTION INPUT ;
    USE SIGNAL ;
    PORT
      LAYER M4 ;
        RECT  0 18.048 0.084 18.072 ;
    END
  END xq[49]
  PIN xq[4]
    DIRECTION INPUT ;
    USE SIGNAL ;
    PORT
      LAYER M5 ;
        RECT  62.016 0 62.04 0.084 ;
    END
  END xq[4]
  PIN xq[500]
    DIRECTION INPUT ;
    USE SIGNAL ;
    PORT
      LAYER M4 ;
        RECT  0 73.824 0.084 73.848 ;
    END
  END xq[500]
  PIN xq[501]
    DIRECTION INPUT ;
    USE SIGNAL ;
    PORT
      LAYER M4 ;
        RECT  0 73.728 0.084 73.752 ;
    END
  END xq[501]
  PIN xq[502]
    DIRECTION INPUT ;
    USE SIGNAL ;
    PORT
      LAYER M4 ;
        RECT  0 73.632 0.084 73.656 ;
    END
  END xq[502]
  PIN xq[503]
    DIRECTION INPUT ;
    USE SIGNAL ;
    PORT
      LAYER M4 ;
        RECT  0 71.904 0.084 71.928 ;
    END
  END xq[503]
  PIN xq[504]
    DIRECTION INPUT ;
    USE SIGNAL ;
    PORT
      LAYER M4 ;
        RECT  0 76.8 0.084 76.824 ;
    END
  END xq[504]
  PIN xq[505]
    DIRECTION INPUT ;
    USE SIGNAL ;
    PORT
      LAYER M4 ;
        RECT  0 76.416 0.084 76.44 ;
    END
  END xq[505]
  PIN xq[506]
    DIRECTION INPUT ;
    USE SIGNAL ;
    PORT
      LAYER M4 ;
        RECT  0 78.048 0.084 78.072 ;
    END
  END xq[506]
  PIN xq[507]
    DIRECTION INPUT ;
    USE SIGNAL ;
    PORT
      LAYER M4 ;
        RECT  0 77.088 0.084 77.112 ;
    END
  END xq[507]
  PIN xq[508]
    DIRECTION INPUT ;
    USE SIGNAL ;
    PORT
      LAYER M4 ;
        RECT  0 75.648 0.084 75.672 ;
    END
  END xq[508]
  PIN xq[509]
    DIRECTION INPUT ;
    USE SIGNAL ;
    PORT
      LAYER M4 ;
        RECT  0 75.936 0.084 75.96 ;
    END
  END xq[509]
  PIN xq[50]
    DIRECTION INPUT ;
    USE SIGNAL ;
    PORT
      LAYER M5 ;
        RECT  15.456 0 15.48 0.084 ;
    END
  END xq[50]
  PIN xq[510]
    DIRECTION INPUT ;
    USE SIGNAL ;
    PORT
      LAYER M4 ;
        RECT  0 75.84 0.084 75.864 ;
    END
  END xq[510]
  PIN xq[511]
    DIRECTION INPUT ;
    USE SIGNAL ;
    PORT
      LAYER M4 ;
        RECT  0 82.176 0.084 82.2 ;
    END
  END xq[511]
  PIN xq[51]
    DIRECTION INPUT ;
    USE SIGNAL ;
    PORT
      LAYER M4 ;
        RECT  0 21.888 0.084 21.912 ;
    END
  END xq[51]
  PIN xq[52]
    DIRECTION INPUT ;
    USE SIGNAL ;
    PORT
      LAYER M4 ;
        RECT  0 22.272 0.084 22.296 ;
    END
  END xq[52]
  PIN xq[53]
    DIRECTION INPUT ;
    USE SIGNAL ;
    PORT
      LAYER M4 ;
        RECT  0 22.368 0.084 22.392 ;
    END
  END xq[53]
  PIN xq[54]
    DIRECTION INPUT ;
    USE SIGNAL ;
    PORT
      LAYER M4 ;
        RECT  0 22.944 0.084 22.968 ;
    END
  END xq[54]
  PIN xq[55]
    DIRECTION INPUT ;
    USE SIGNAL ;
    PORT
      LAYER M4 ;
        RECT  0 18.912 0.084 18.936 ;
    END
  END xq[55]
  PIN xq[56]
    DIRECTION INPUT ;
    USE SIGNAL ;
    PORT
      LAYER M5 ;
        RECT  23.904 0 23.928 0.084 ;
    END
  END xq[56]
  PIN xq[57]
    DIRECTION INPUT ;
    USE SIGNAL ;
    PORT
      LAYER M5 ;
        RECT  23.712 0 23.736 0.084 ;
    END
  END xq[57]
  PIN xq[58]
    DIRECTION INPUT ;
    USE SIGNAL ;
    PORT
      LAYER M5 ;
        RECT  24.96 0 24.984 0.084 ;
    END
  END xq[58]
  PIN xq[59]
    DIRECTION INPUT ;
    USE SIGNAL ;
    PORT
      LAYER M5 ;
        RECT  25.056 0 25.08 0.084 ;
    END
  END xq[59]
  PIN xq[5]
    DIRECTION INPUT ;
    USE SIGNAL ;
    PORT
      LAYER M5 ;
        RECT  61.92 0 61.944 0.084 ;
    END
  END xq[5]
  PIN xq[60]
    DIRECTION INPUT ;
    USE SIGNAL ;
    PORT
      LAYER M5 ;
        RECT  24 0 24.024 0.084 ;
    END
  END xq[60]
  PIN xq[61]
    DIRECTION INPUT ;
    USE SIGNAL ;
    PORT
      LAYER M5 ;
        RECT  24.384 0 24.408 0.084 ;
    END
  END xq[61]
  PIN xq[62]
    DIRECTION INPUT ;
    USE SIGNAL ;
    PORT
      LAYER M5 ;
        RECT  24.48 0 24.504 0.084 ;
    END
  END xq[62]
  PIN xq[63]
    DIRECTION INPUT ;
    USE SIGNAL ;
    PORT
      LAYER M5 ;
        RECT  23.232 0 23.256 0.084 ;
    END
  END xq[63]
  PIN xq[64]
    DIRECTION INPUT ;
    USE SIGNAL ;
    PORT
      LAYER M5 ;
        RECT  16.512 0 16.536 0.084 ;
    END
  END xq[64]
  PIN xq[65]
    DIRECTION INPUT ;
    USE SIGNAL ;
    PORT
      LAYER M5 ;
        RECT  16.32 0 16.344 0.084 ;
    END
  END xq[65]
  PIN xq[66]
    DIRECTION INPUT ;
    USE SIGNAL ;
    PORT
      LAYER M5 ;
        RECT  16.992 0 17.016 0.084 ;
    END
  END xq[66]
  PIN xq[67]
    DIRECTION INPUT ;
    USE SIGNAL ;
    PORT
      LAYER M5 ;
        RECT  18.144 0 18.168 0.084 ;
    END
  END xq[67]
  PIN xq[68]
    DIRECTION INPUT ;
    USE SIGNAL ;
    PORT
      LAYER M5 ;
        RECT  19.2 0 19.224 0.084 ;
    END
  END xq[68]
  PIN xq[69]
    DIRECTION INPUT ;
    USE SIGNAL ;
    PORT
      LAYER M5 ;
        RECT  19.008 0 19.032 0.084 ;
    END
  END xq[69]
  PIN xq[6]
    DIRECTION INPUT ;
    USE SIGNAL ;
    PORT
      LAYER M5 ;
        RECT  62.112 0 62.136 0.084 ;
    END
  END xq[6]
  PIN xq[70]
    DIRECTION INPUT ;
    USE SIGNAL ;
    PORT
      LAYER M5 ;
        RECT  19.104 0 19.128 0.084 ;
    END
  END xq[70]
  PIN xq[71]
    DIRECTION INPUT ;
    USE SIGNAL ;
    PORT
      LAYER M5 ;
        RECT  16.128 0 16.152 0.084 ;
    END
  END xq[71]
  PIN xq[72]
    DIRECTION INPUT ;
    USE SIGNAL ;
    PORT
      LAYER M4 ;
        RECT  0 12.288 0.084 12.312 ;
    END
  END xq[72]
  PIN xq[73]
    DIRECTION INPUT ;
    USE SIGNAL ;
    PORT
      LAYER M5 ;
        RECT  8.928 0 8.952 0.084 ;
    END
  END xq[73]
  PIN xq[74]
    DIRECTION INPUT ;
    USE SIGNAL ;
    PORT
      LAYER M4 ;
        RECT  0 16.608 0.084 16.632 ;
    END
  END xq[74]
  PIN xq[75]
    DIRECTION INPUT ;
    USE SIGNAL ;
    PORT
      LAYER M4 ;
        RECT  0 18.624 0.084 18.648 ;
    END
  END xq[75]
  PIN xq[76]
    DIRECTION INPUT ;
    USE SIGNAL ;
    PORT
      LAYER M5 ;
        RECT  14.304 0 14.328 0.084 ;
    END
  END xq[76]
  PIN xq[77]
    DIRECTION INPUT ;
    USE SIGNAL ;
    PORT
      LAYER M4 ;
        RECT  0 19.008 0.084 19.032 ;
    END
  END xq[77]
  PIN xq[78]
    DIRECTION INPUT ;
    USE SIGNAL ;
    PORT
      LAYER M4 ;
        RECT  0 18.816 0.084 18.84 ;
    END
  END xq[78]
  PIN xq[79]
    DIRECTION INPUT ;
    USE SIGNAL ;
    PORT
      LAYER M5 ;
        RECT  10.464 0 10.488 0.084 ;
    END
  END xq[79]
  PIN xq[7]
    DIRECTION INPUT ;
    USE SIGNAL ;
    PORT
      LAYER M5 ;
        RECT  65.76 0 65.784 0.084 ;
    END
  END xq[7]
  PIN xq[80]
    DIRECTION INPUT ;
    USE SIGNAL ;
    PORT
      LAYER M4 ;
        RECT  0 33.12 0.084 33.144 ;
    END
  END xq[80]
  PIN xq[81]
    DIRECTION INPUT ;
    USE SIGNAL ;
    PORT
      LAYER M4 ;
        RECT  0 33.408 0.084 33.432 ;
    END
  END xq[81]
  PIN xq[82]
    DIRECTION INPUT ;
    USE SIGNAL ;
    PORT
      LAYER M4 ;
        RECT  0 31.296 0.084 31.32 ;
    END
  END xq[82]
  PIN xq[83]
    DIRECTION INPUT ;
    USE SIGNAL ;
    PORT
      LAYER M4 ;
        RECT  0 33.504 0.084 33.528 ;
    END
  END xq[83]
  PIN xq[84]
    DIRECTION INPUT ;
    USE SIGNAL ;
    PORT
      LAYER M4 ;
        RECT  0 34.272 0.084 34.296 ;
    END
  END xq[84]
  PIN xq[85]
    DIRECTION INPUT ;
    USE SIGNAL ;
    PORT
      LAYER M4 ;
        RECT  0 34.752 0.084 34.776 ;
    END
  END xq[85]
  PIN xq[86]
    DIRECTION INPUT ;
    USE SIGNAL ;
    PORT
      LAYER M4 ;
        RECT  0 34.848 0.084 34.872 ;
    END
  END xq[86]
  PIN xq[87]
    DIRECTION INPUT ;
    USE SIGNAL ;
    PORT
      LAYER M4 ;
        RECT  0 30.144 0.084 30.168 ;
    END
  END xq[87]
  PIN xq[88]
    DIRECTION INPUT ;
    USE SIGNAL ;
    PORT
      LAYER M4 ;
        RECT  0 21.504 0.084 21.528 ;
    END
  END xq[88]
  PIN xq[89]
    DIRECTION INPUT ;
    USE SIGNAL ;
    PORT
      LAYER M4 ;
        RECT  0 22.848 0.084 22.872 ;
    END
  END xq[89]
  PIN xq[8]
    DIRECTION INPUT ;
    USE SIGNAL ;
    PORT
      LAYER M5 ;
        RECT  64.224 0 64.248 0.084 ;
    END
  END xq[8]
  PIN xq[90]
    DIRECTION INPUT ;
    USE SIGNAL ;
    PORT
      LAYER M4 ;
        RECT  0 22.464 0.084 22.488 ;
    END
  END xq[90]
  PIN xq[91]
    DIRECTION INPUT ;
    USE SIGNAL ;
    PORT
      LAYER M4 ;
        RECT  0 25.632 0.084 25.656 ;
    END
  END xq[91]
  PIN xq[92]
    DIRECTION INPUT ;
    USE SIGNAL ;
    PORT
      LAYER M4 ;
        RECT  0 27.168 0.084 27.192 ;
    END
  END xq[92]
  PIN xq[93]
    DIRECTION INPUT ;
    USE SIGNAL ;
    PORT
      LAYER M4 ;
        RECT  0 27.072 0.084 27.096 ;
    END
  END xq[93]
  PIN xq[94]
    DIRECTION INPUT ;
    USE SIGNAL ;
    PORT
      LAYER M4 ;
        RECT  0 26.976 0.084 27 ;
    END
  END xq[94]
  PIN xq[95]
    DIRECTION INPUT ;
    USE SIGNAL ;
    PORT
      LAYER M4 ;
        RECT  0 19.2 0.084 19.224 ;
    END
  END xq[95]
  PIN xq[96]
    DIRECTION INPUT ;
    USE SIGNAL ;
    PORT
      LAYER M4 ;
        RECT  0 42.432 0.084 42.456 ;
    END
  END xq[96]
  PIN xq[97]
    DIRECTION INPUT ;
    USE SIGNAL ;
    PORT
      LAYER M4 ;
        RECT  0 42.912 0.084 42.936 ;
    END
  END xq[97]
  PIN xq[98]
    DIRECTION INPUT ;
    USE SIGNAL ;
    PORT
      LAYER M4 ;
        RECT  0 39.072 0.084 39.096 ;
    END
  END xq[98]
  PIN xq[99]
    DIRECTION INPUT ;
    USE SIGNAL ;
    PORT
      LAYER M4 ;
        RECT  0 41.664 0.084 41.688 ;
    END
  END xq[99]
  PIN xq[9]
    DIRECTION INPUT ;
    USE SIGNAL ;
    PORT
      LAYER M5 ;
        RECT  62.88 0 62.904 0.084 ;
    END
  END xq[9]
  PIN y[0]
    DIRECTION OUTPUT ;
    USE SIGNAL ;
    PORT
      LAYER M4 ;
        RECT  128.233 72.48 128.317 72.504 ;
    END
  END y[0]
  PIN y[10]
    DIRECTION OUTPUT ;
    USE SIGNAL ;
    PORT
      LAYER M4 ;
        RECT  128.233 70.848 128.317 70.872 ;
    END
  END y[10]
  PIN y[11]
    DIRECTION OUTPUT ;
    USE SIGNAL ;
    PORT
      LAYER M4 ;
        RECT  128.233 74.784 128.317 74.808 ;
    END
  END y[11]
  PIN y[12]
    DIRECTION OUTPUT ;
    USE SIGNAL ;
    PORT
      LAYER M4 ;
        RECT  128.233 78.912 128.317 78.936 ;
    END
  END y[12]
  PIN y[13]
    DIRECTION OUTPUT ;
    USE SIGNAL ;
    PORT
      LAYER M4 ;
        RECT  128.233 78.816 128.317 78.84 ;
    END
  END y[13]
  PIN y[14]
    DIRECTION OUTPUT ;
    USE SIGNAL ;
    PORT
      LAYER M4 ;
        RECT  128.233 77.184 128.317 77.208 ;
    END
  END y[14]
  PIN y[15]
    DIRECTION OUTPUT ;
    USE SIGNAL ;
    PORT
      LAYER M4 ;
        RECT  128.233 79.968 128.317 79.992 ;
    END
  END y[15]
  PIN y[16]
    DIRECTION OUTPUT ;
    USE SIGNAL ;
    PORT
      LAYER M4 ;
        RECT  128.233 77.76 128.317 77.784 ;
    END
  END y[16]
  PIN y[17]
    DIRECTION OUTPUT ;
    USE SIGNAL ;
    PORT
      LAYER M4 ;
        RECT  128.233 81.216 128.317 81.24 ;
    END
  END y[17]
  PIN y[18]
    DIRECTION OUTPUT ;
    USE SIGNAL ;
    PORT
      LAYER M4 ;
        RECT  128.233 78.336 128.317 78.36 ;
    END
  END y[18]
  PIN y[19]
    DIRECTION OUTPUT ;
    USE SIGNAL ;
    PORT
      LAYER M4 ;
        RECT  128.233 78.72 128.317 78.744 ;
    END
  END y[19]
  PIN y[1]
    DIRECTION OUTPUT ;
    USE SIGNAL ;
    PORT
      LAYER M4 ;
        RECT  128.233 69.6 128.317 69.624 ;
    END
  END y[1]
  PIN y[20]
    DIRECTION OUTPUT ;
    USE SIGNAL ;
    PORT
      LAYER M4 ;
        RECT  128.233 80.064 128.317 80.088 ;
    END
  END y[20]
  PIN y[21]
    DIRECTION OUTPUT ;
    USE SIGNAL ;
    PORT
      LAYER M4 ;
        RECT  128.233 79.008 128.317 79.032 ;
    END
  END y[21]
  PIN y[22]
    DIRECTION OUTPUT ;
    USE SIGNAL ;
    PORT
      LAYER M4 ;
        RECT  128.233 75.36 128.317 75.384 ;
    END
  END y[22]
  PIN y[23]
    DIRECTION OUTPUT ;
    USE SIGNAL ;
    PORT
      LAYER M4 ;
        RECT  128.233 73.536 128.317 73.56 ;
    END
  END y[23]
  PIN y[24]
    DIRECTION OUTPUT ;
    USE SIGNAL ;
    PORT
      LAYER M4 ;
        RECT  128.233 77.664 128.317 77.688 ;
    END
  END y[24]
  PIN y[25]
    DIRECTION OUTPUT ;
    USE SIGNAL ;
    PORT
      LAYER M4 ;
        RECT  128.233 79.104 128.317 79.128 ;
    END
  END y[25]
  PIN y[26]
    DIRECTION OUTPUT ;
    USE SIGNAL ;
    PORT
      LAYER M4 ;
        RECT  128.233 75.264 128.317 75.288 ;
    END
  END y[26]
  PIN y[27]
    DIRECTION OUTPUT ;
    USE SIGNAL ;
    PORT
      LAYER M4 ;
        RECT  128.233 78.144 128.317 78.168 ;
    END
  END y[27]
  PIN y[28]
    DIRECTION OUTPUT ;
    USE SIGNAL ;
    PORT
      LAYER M4 ;
        RECT  128.233 74.688 128.317 74.712 ;
    END
  END y[28]
  PIN y[29]
    DIRECTION OUTPUT ;
    USE SIGNAL ;
    PORT
      LAYER M4 ;
        RECT  128.233 72.096 128.317 72.12 ;
    END
  END y[29]
  PIN y[2]
    DIRECTION OUTPUT ;
    USE SIGNAL ;
    PORT
      LAYER M4 ;
        RECT  128.233 62.688 128.317 62.712 ;
    END
  END y[2]
  PIN y[30]
    DIRECTION OUTPUT ;
    USE SIGNAL ;
    PORT
      LAYER M4 ;
        RECT  128.233 77.568 128.317 77.592 ;
    END
  END y[30]
  PIN y[31]
    DIRECTION OUTPUT ;
    USE SIGNAL ;
    PORT
      LAYER M4 ;
        RECT  128.233 74.208 128.317 74.232 ;
    END
  END y[31]
  PIN y[3]
    DIRECTION OUTPUT ;
    USE SIGNAL ;
    PORT
      LAYER M4 ;
        RECT  128.233 73.824 128.317 73.848 ;
    END
  END y[3]
  PIN y[4]
    DIRECTION OUTPUT ;
    USE SIGNAL ;
    PORT
      LAYER M4 ;
        RECT  128.233 62.592 128.317 62.616 ;
    END
  END y[4]
  PIN y[5]
    DIRECTION OUTPUT ;
    USE SIGNAL ;
    PORT
      LAYER M4 ;
        RECT  128.233 67.68 128.317 67.704 ;
    END
  END y[5]
  PIN y[6]
    DIRECTION OUTPUT ;
    USE SIGNAL ;
    PORT
      LAYER M4 ;
        RECT  128.233 64.704 128.317 64.728 ;
    END
  END y[6]
  PIN y[7]
    DIRECTION OUTPUT ;
    USE SIGNAL ;
    PORT
      LAYER M4 ;
        RECT  128.233 76.512 128.317 76.536 ;
    END
  END y[7]
  PIN y[8]
    DIRECTION OUTPUT ;
    USE SIGNAL ;
    PORT
      LAYER M4 ;
        RECT  128.233 66.048 128.317 66.072 ;
    END
  END y[8]
  PIN y[9]
    DIRECTION OUTPUT ;
    USE SIGNAL ;
    PORT
      LAYER M4 ;
        RECT  128.233 77.376 128.317 77.4 ;
    END
  END y[9]
  PIN VDD
    DIRECTION INOUT ;
    USE POWER ;
    PORT
      LAYER M6 ;
        RECT  1.44 123.2 126.918 123.488 ;
        RECT  1.44 112.4 126.918 112.688 ;
        RECT  1.44 101.6 126.918 101.888 ;
        RECT  1.44 90.8 126.918 91.088 ;
        RECT  1.44 80 126.918 80.288 ;
        RECT  1.44 69.2 126.918 69.488 ;
        RECT  1.44 58.4 126.918 58.688 ;
        RECT  1.44 47.6 126.918 47.888 ;
        RECT  1.44 36.8 126.918 37.088 ;
        RECT  1.44 26 126.918 26.288 ;
        RECT  1.44 15.2 126.918 15.488 ;
        RECT  1.44 4.4 126.918 4.688 ;
        RECT  1.44 126.774 126.918 127.062 ;
        RECT  1.44 1.188 126.918 1.476 ;
    END
  END VDD
  PIN VSS
    DIRECTION INOUT ;
    USE GROUND ;
    PORT
      LAYER M6 ;
        RECT  1.44 122.816 126.918 123.104 ;
        RECT  1.44 112.016 126.918 112.304 ;
        RECT  1.44 101.216 126.918 101.504 ;
        RECT  1.44 90.416 126.918 90.704 ;
        RECT  1.44 79.616 126.918 79.904 ;
        RECT  1.44 68.816 126.918 69.104 ;
        RECT  1.44 58.016 126.918 58.304 ;
        RECT  1.44 47.216 126.918 47.504 ;
        RECT  1.44 36.416 126.918 36.704 ;
        RECT  1.44 25.616 126.918 25.904 ;
        RECT  1.44 14.816 126.918 15.104 ;
        RECT  1.44 4.016 126.918 4.304 ;
        RECT  1.632 126.39 126.726 126.678 ;
        RECT  1.632 1.572 126.726 1.86 ;
    END
  END VSS
  OBS
    LAYER RVTN ;
     RECT  0 0 128.317 128.317 ;
    LAYER RVTP ;
     RECT  0 0 128.317 128.317 ;
    LAYER M1 ;
     RECT  0 0 128.317 128.317 ;
    LAYER M2 ;
     RECT  0 0 128.317 128.317 ;
    LAYER M3 ;
     RECT  0 0 128.317 128.317 ;
    LAYER M4 ;
     RECT  0 0 128.317 128.317 ;
    LAYER M5 ;
     RECT  0 0 128.317 128.317 ;
    LAYER M6 ;
     RECT  0 0 128.317 128.317 ;
  END
END ot_hbm_accel_bd_col
END LIBRARY
